VERSION 5.8 ;
BUSBITCHARS "[]" ;
DIVIDERCHAR "/" ;
UNITS
    DATABASE MICRONS 1000 ;
END UNITS

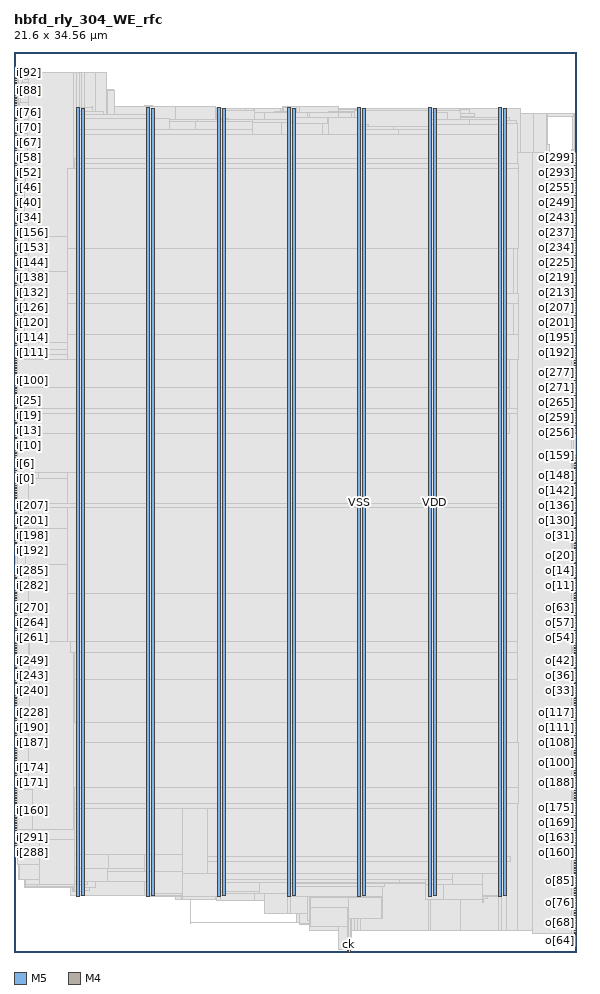
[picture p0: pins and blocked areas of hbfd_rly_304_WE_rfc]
MACRO hbfd_rly_304_WE_rfc
  FOREIGN hbfd_rly_304_WE_rfc 0 0 ;
  CLASS BLOCK ;
  SIZE 21.6 BY 34.56 ;
  PIN ck
    DIRECTION INPUT ;
    USE SIGNAL ;
    PORT
      LAYER M5 ;
        RECT  12.816 0 12.84 0.084 ;
    END
  END ck
  PIN i[0]
    DIRECTION INPUT ;
    USE SIGNAL ;
    PORT
      LAYER M4 ;
        RECT  0 18.48 0.084 18.504 ;
    END
  END i[0]
  PIN i[100]
    DIRECTION INPUT ;
    USE SIGNAL ;
    PORT
      LAYER M4 ;
        RECT  0 21.936 0.084 21.96 ;
    END
  END i[100]
  PIN i[101]
    DIRECTION INPUT ;
    USE SIGNAL ;
    PORT
      LAYER M4 ;
        RECT  0 22.032 0.084 22.056 ;
    END
  END i[101]
  PIN i[102]
    DIRECTION INPUT ;
    USE SIGNAL ;
    PORT
      LAYER M4 ;
        RECT  0 22.128 0.084 22.152 ;
    END
  END i[102]
  PIN i[103]
    DIRECTION INPUT ;
    USE SIGNAL ;
    PORT
      LAYER M4 ;
        RECT  0 22.224 0.084 22.248 ;
    END
  END i[103]
  PIN i[104]
    DIRECTION INPUT ;
    USE SIGNAL ;
    PORT
      LAYER M4 ;
        RECT  0 22.32 0.084 22.344 ;
    END
  END i[104]
  PIN i[105]
    DIRECTION INPUT ;
    USE SIGNAL ;
    PORT
      LAYER M4 ;
        RECT  0 22.416 0.084 22.44 ;
    END
  END i[105]
  PIN i[106]
    DIRECTION INPUT ;
    USE SIGNAL ;
    PORT
      LAYER M4 ;
        RECT  0 22.512 0.084 22.536 ;
    END
  END i[106]
  PIN i[107]
    DIRECTION INPUT ;
    USE SIGNAL ;
    PORT
      LAYER M4 ;
        RECT  0 22.608 0.084 22.632 ;
    END
  END i[107]
  PIN i[108]
    DIRECTION INPUT ;
    USE SIGNAL ;
    PORT
      LAYER M4 ;
        RECT  0 22.704 0.084 22.728 ;
    END
  END i[108]
  PIN i[109]
    DIRECTION INPUT ;
    USE SIGNAL ;
    PORT
      LAYER M4 ;
        RECT  0 22.8 0.084 22.824 ;
    END
  END i[109]
  PIN i[10]
    DIRECTION INPUT ;
    USE SIGNAL ;
    PORT
      LAYER M4 ;
        RECT  0 19.44 0.084 19.464 ;
    END
  END i[10]
  PIN i[110]
    DIRECTION INPUT ;
    USE SIGNAL ;
    PORT
      LAYER M4 ;
        RECT  0 22.896 0.084 22.92 ;
    END
  END i[110]
  PIN i[111]
    DIRECTION INPUT ;
    USE SIGNAL ;
    PORT
      LAYER M4 ;
        RECT  0 22.992 0.084 23.016 ;
    END
  END i[111]
  PIN i[112]
    DIRECTION INPUT ;
    USE SIGNAL ;
    PORT
      LAYER M4 ;
        RECT  0 23.088 0.084 23.112 ;
    END
  END i[112]
  PIN i[113]
    DIRECTION INPUT ;
    USE SIGNAL ;
    PORT
      LAYER M4 ;
        RECT  0 23.184 0.084 23.208 ;
    END
  END i[113]
  PIN i[114]
    DIRECTION INPUT ;
    USE SIGNAL ;
    PORT
      LAYER M4 ;
        RECT  0 23.28 0.084 23.304 ;
    END
  END i[114]
  PIN i[115]
    DIRECTION INPUT ;
    USE SIGNAL ;
    PORT
      LAYER M4 ;
        RECT  0 23.376 0.084 23.4 ;
    END
  END i[115]
  PIN i[116]
    DIRECTION INPUT ;
    USE SIGNAL ;
    PORT
      LAYER M4 ;
        RECT  0 23.472 0.084 23.496 ;
    END
  END i[116]
  PIN i[117]
    DIRECTION INPUT ;
    USE SIGNAL ;
    PORT
      LAYER M4 ;
        RECT  0 23.568 0.084 23.592 ;
    END
  END i[117]
  PIN i[118]
    DIRECTION INPUT ;
    USE SIGNAL ;
    PORT
      LAYER M4 ;
        RECT  0 23.664 0.084 23.688 ;
    END
  END i[118]
  PIN i[119]
    DIRECTION INPUT ;
    USE SIGNAL ;
    PORT
      LAYER M4 ;
        RECT  0 23.76 0.084 23.784 ;
    END
  END i[119]
  PIN i[11]
    DIRECTION INPUT ;
    USE SIGNAL ;
    PORT
      LAYER M4 ;
        RECT  0 19.536 0.084 19.56 ;
    END
  END i[11]
  PIN i[120]
    DIRECTION INPUT ;
    USE SIGNAL ;
    PORT
      LAYER M4 ;
        RECT  0 23.856 0.084 23.88 ;
    END
  END i[120]
  PIN i[121]
    DIRECTION INPUT ;
    USE SIGNAL ;
    PORT
      LAYER M4 ;
        RECT  0 23.952 0.084 23.976 ;
    END
  END i[121]
  PIN i[122]
    DIRECTION INPUT ;
    USE SIGNAL ;
    PORT
      LAYER M4 ;
        RECT  0 24.048 0.084 24.072 ;
    END
  END i[122]
  PIN i[123]
    DIRECTION INPUT ;
    USE SIGNAL ;
    PORT
      LAYER M4 ;
        RECT  0 24.144 0.084 24.168 ;
    END
  END i[123]
  PIN i[124]
    DIRECTION INPUT ;
    USE SIGNAL ;
    PORT
      LAYER M4 ;
        RECT  0 24.24 0.084 24.264 ;
    END
  END i[124]
  PIN i[125]
    DIRECTION INPUT ;
    USE SIGNAL ;
    PORT
      LAYER M4 ;
        RECT  0 24.336 0.084 24.36 ;
    END
  END i[125]
  PIN i[126]
    DIRECTION INPUT ;
    USE SIGNAL ;
    PORT
      LAYER M4 ;
        RECT  0 24.432 0.084 24.456 ;
    END
  END i[126]
  PIN i[127]
    DIRECTION INPUT ;
    USE SIGNAL ;
    PORT
      LAYER M4 ;
        RECT  0 24.528 0.084 24.552 ;
    END
  END i[127]
  PIN i[128]
    DIRECTION INPUT ;
    USE SIGNAL ;
    PORT
      LAYER M4 ;
        RECT  0 24.624 0.084 24.648 ;
    END
  END i[128]
  PIN i[129]
    DIRECTION INPUT ;
    USE SIGNAL ;
    PORT
      LAYER M4 ;
        RECT  0 24.72 0.084 24.744 ;
    END
  END i[129]
  PIN i[12]
    DIRECTION INPUT ;
    USE SIGNAL ;
    PORT
      LAYER M4 ;
        RECT  0 19.632 0.084 19.656 ;
    END
  END i[12]
  PIN i[130]
    DIRECTION INPUT ;
    USE SIGNAL ;
    PORT
      LAYER M4 ;
        RECT  0 24.816 0.084 24.84 ;
    END
  END i[130]
  PIN i[131]
    DIRECTION INPUT ;
    USE SIGNAL ;
    PORT
      LAYER M4 ;
        RECT  0 24.912 0.084 24.936 ;
    END
  END i[131]
  PIN i[132]
    DIRECTION INPUT ;
    USE SIGNAL ;
    PORT
      LAYER M4 ;
        RECT  0 25.008 0.084 25.032 ;
    END
  END i[132]
  PIN i[133]
    DIRECTION INPUT ;
    USE SIGNAL ;
    PORT
      LAYER M4 ;
        RECT  0 25.104 0.084 25.128 ;
    END
  END i[133]
  PIN i[134]
    DIRECTION INPUT ;
    USE SIGNAL ;
    PORT
      LAYER M4 ;
        RECT  0 25.2 0.084 25.224 ;
    END
  END i[134]
  PIN i[135]
    DIRECTION INPUT ;
    USE SIGNAL ;
    PORT
      LAYER M4 ;
        RECT  0 25.296 0.084 25.32 ;
    END
  END i[135]
  PIN i[136]
    DIRECTION INPUT ;
    USE SIGNAL ;
    PORT
      LAYER M4 ;
        RECT  0 25.392 0.084 25.416 ;
    END
  END i[136]
  PIN i[137]
    DIRECTION INPUT ;
    USE SIGNAL ;
    PORT
      LAYER M4 ;
        RECT  0 25.488 0.084 25.512 ;
    END
  END i[137]
  PIN i[138]
    DIRECTION INPUT ;
    USE SIGNAL ;
    PORT
      LAYER M4 ;
        RECT  0 25.584 0.084 25.608 ;
    END
  END i[138]
  PIN i[139]
    DIRECTION INPUT ;
    USE SIGNAL ;
    PORT
      LAYER M4 ;
        RECT  0 25.68 0.084 25.704 ;
    END
  END i[139]
  PIN i[13]
    DIRECTION INPUT ;
    USE SIGNAL ;
    PORT
      LAYER M4 ;
        RECT  0 19.728 0.084 19.752 ;
    END
  END i[13]
  PIN i[140]
    DIRECTION INPUT ;
    USE SIGNAL ;
    PORT
      LAYER M4 ;
        RECT  0 25.776 0.084 25.8 ;
    END
  END i[140]
  PIN i[141]
    DIRECTION INPUT ;
    USE SIGNAL ;
    PORT
      LAYER M4 ;
        RECT  0 25.872 0.084 25.896 ;
    END
  END i[141]
  PIN i[142]
    DIRECTION INPUT ;
    USE SIGNAL ;
    PORT
      LAYER M4 ;
        RECT  0 25.968 0.084 25.992 ;
    END
  END i[142]
  PIN i[143]
    DIRECTION INPUT ;
    USE SIGNAL ;
    PORT
      LAYER M4 ;
        RECT  0 26.064 0.084 26.088 ;
    END
  END i[143]
  PIN i[144]
    DIRECTION INPUT ;
    USE SIGNAL ;
    PORT
      LAYER M4 ;
        RECT  0 26.16 0.084 26.184 ;
    END
  END i[144]
  PIN i[145]
    DIRECTION INPUT ;
    USE SIGNAL ;
    PORT
      LAYER M4 ;
        RECT  0 26.256 0.084 26.28 ;
    END
  END i[145]
  PIN i[146]
    DIRECTION INPUT ;
    USE SIGNAL ;
    PORT
      LAYER M4 ;
        RECT  0 26.352 0.084 26.376 ;
    END
  END i[146]
  PIN i[147]
    DIRECTION INPUT ;
    USE SIGNAL ;
    PORT
      LAYER M4 ;
        RECT  0 26.448 0.084 26.472 ;
    END
  END i[147]
  PIN i[148]
    DIRECTION INPUT ;
    USE SIGNAL ;
    PORT
      LAYER M4 ;
        RECT  0 26.544 0.084 26.568 ;
    END
  END i[148]
  PIN i[149]
    DIRECTION INPUT ;
    USE SIGNAL ;
    PORT
      LAYER M4 ;
        RECT  0 26.64 0.084 26.664 ;
    END
  END i[149]
  PIN i[14]
    DIRECTION INPUT ;
    USE SIGNAL ;
    PORT
      LAYER M4 ;
        RECT  0 19.824 0.084 19.848 ;
    END
  END i[14]
  PIN i[150]
    DIRECTION INPUT ;
    USE SIGNAL ;
    PORT
      LAYER M4 ;
        RECT  0 26.736 0.084 26.76 ;
    END
  END i[150]
  PIN i[151]
    DIRECTION INPUT ;
    USE SIGNAL ;
    PORT
      LAYER M4 ;
        RECT  0 26.832 0.084 26.856 ;
    END
  END i[151]
  PIN i[152]
    DIRECTION INPUT ;
    USE SIGNAL ;
    PORT
      LAYER M4 ;
        RECT  0 26.928 0.084 26.952 ;
    END
  END i[152]
  PIN i[153]
    DIRECTION INPUT ;
    USE SIGNAL ;
    PORT
      LAYER M4 ;
        RECT  0 27.024 0.084 27.048 ;
    END
  END i[153]
  PIN i[154]
    DIRECTION INPUT ;
    USE SIGNAL ;
    PORT
      LAYER M4 ;
        RECT  0 27.12 0.084 27.144 ;
    END
  END i[154]
  PIN i[155]
    DIRECTION INPUT ;
    USE SIGNAL ;
    PORT
      LAYER M4 ;
        RECT  0 27.216 0.084 27.24 ;
    END
  END i[155]
  PIN i[156]
    DIRECTION INPUT ;
    USE SIGNAL ;
    PORT
      LAYER M4 ;
        RECT  0 27.312 0.084 27.336 ;
    END
  END i[156]
  PIN i[157]
    DIRECTION INPUT ;
    USE SIGNAL ;
    PORT
      LAYER M4 ;
        RECT  0 27.408 0.084 27.432 ;
    END
  END i[157]
  PIN i[158]
    DIRECTION INPUT ;
    USE SIGNAL ;
    PORT
      LAYER M4 ;
        RECT  0 27.504 0.084 27.528 ;
    END
  END i[158]
  PIN i[159]
    DIRECTION INPUT ;
    USE SIGNAL ;
    PORT
      LAYER M4 ;
        RECT  0 27.6 0.084 27.624 ;
    END
  END i[159]
  PIN i[15]
    DIRECTION INPUT ;
    USE SIGNAL ;
    PORT
      LAYER M4 ;
        RECT  0 19.92 0.084 19.944 ;
    END
  END i[15]
  PIN i[160]
    DIRECTION INPUT ;
    USE SIGNAL ;
    PORT
      LAYER M4 ;
        RECT  0 5.424 0.084 5.448 ;
    END
  END i[160]
  PIN i[161]
    DIRECTION INPUT ;
    USE SIGNAL ;
    PORT
      LAYER M4 ;
        RECT  0 5.52 0.084 5.544 ;
    END
  END i[161]
  PIN i[162]
    DIRECTION INPUT ;
    USE SIGNAL ;
    PORT
      LAYER M4 ;
        RECT  0 5.616 0.084 5.64 ;
    END
  END i[162]
  PIN i[163]
    DIRECTION INPUT ;
    USE SIGNAL ;
    PORT
      LAYER M4 ;
        RECT  0 5.712 0.084 5.736 ;
    END
  END i[163]
  PIN i[164]
    DIRECTION INPUT ;
    USE SIGNAL ;
    PORT
      LAYER M4 ;
        RECT  0 5.808 0.084 5.832 ;
    END
  END i[164]
  PIN i[165]
    DIRECTION INPUT ;
    USE SIGNAL ;
    PORT
      LAYER M4 ;
        RECT  0 5.904 0.084 5.928 ;
    END
  END i[165]
  PIN i[166]
    DIRECTION INPUT ;
    USE SIGNAL ;
    PORT
      LAYER M4 ;
        RECT  0 6 0.084 6.024 ;
    END
  END i[166]
  PIN i[167]
    DIRECTION INPUT ;
    USE SIGNAL ;
    PORT
      LAYER M4 ;
        RECT  0 6.096 0.084 6.12 ;
    END
  END i[167]
  PIN i[168]
    DIRECTION INPUT ;
    USE SIGNAL ;
    PORT
      LAYER M4 ;
        RECT  0 6.192 0.084 6.216 ;
    END
  END i[168]
  PIN i[169]
    DIRECTION INPUT ;
    USE SIGNAL ;
    PORT
      LAYER M4 ;
        RECT  0 6.288 0.084 6.312 ;
    END
  END i[169]
  PIN i[16]
    DIRECTION INPUT ;
    USE SIGNAL ;
    PORT
      LAYER M4 ;
        RECT  0 20.016 0.084 20.04 ;
    END
  END i[16]
  PIN i[170]
    DIRECTION INPUT ;
    USE SIGNAL ;
    PORT
      LAYER M4 ;
        RECT  0 6.384 0.084 6.408 ;
    END
  END i[170]
  PIN i[171]
    DIRECTION INPUT ;
    USE SIGNAL ;
    PORT
      LAYER M4 ;
        RECT  0 6.48 0.084 6.504 ;
    END
  END i[171]
  PIN i[172]
    DIRECTION INPUT ;
    USE SIGNAL ;
    PORT
      LAYER M4 ;
        RECT  0 6.576 0.084 6.6 ;
    END
  END i[172]
  PIN i[173]
    DIRECTION INPUT ;
    USE SIGNAL ;
    PORT
      LAYER M4 ;
        RECT  0 6.672 0.084 6.696 ;
    END
  END i[173]
  PIN i[174]
    DIRECTION INPUT ;
    USE SIGNAL ;
    PORT
      LAYER M4 ;
        RECT  0 6.768 0.084 6.792 ;
    END
  END i[174]
  PIN i[175]
    DIRECTION INPUT ;
    USE SIGNAL ;
    PORT
      LAYER M4 ;
        RECT  0 6.864 0.084 6.888 ;
    END
  END i[175]
  PIN i[176]
    DIRECTION INPUT ;
    USE SIGNAL ;
    PORT
      LAYER M4 ;
        RECT  0 6.96 0.084 6.984 ;
    END
  END i[176]
  PIN i[177]
    DIRECTION INPUT ;
    USE SIGNAL ;
    PORT
      LAYER M4 ;
        RECT  0 7.056 0.084 7.08 ;
    END
  END i[177]
  PIN i[178]
    DIRECTION INPUT ;
    USE SIGNAL ;
    PORT
      LAYER M4 ;
        RECT  0 7.152 0.084 7.176 ;
    END
  END i[178]
  PIN i[179]
    DIRECTION INPUT ;
    USE SIGNAL ;
    PORT
      LAYER M4 ;
        RECT  0 7.248 0.084 7.272 ;
    END
  END i[179]
  PIN i[17]
    DIRECTION INPUT ;
    USE SIGNAL ;
    PORT
      LAYER M4 ;
        RECT  0 20.112 0.084 20.136 ;
    END
  END i[17]
  PIN i[180]
    DIRECTION INPUT ;
    USE SIGNAL ;
    PORT
      LAYER M4 ;
        RECT  0 7.344 0.084 7.368 ;
    END
  END i[180]
  PIN i[181]
    DIRECTION INPUT ;
    USE SIGNAL ;
    PORT
      LAYER M4 ;
        RECT  0 7.44 0.084 7.464 ;
    END
  END i[181]
  PIN i[182]
    DIRECTION INPUT ;
    USE SIGNAL ;
    PORT
      LAYER M4 ;
        RECT  0 7.536 0.084 7.56 ;
    END
  END i[182]
  PIN i[183]
    DIRECTION INPUT ;
    USE SIGNAL ;
    PORT
      LAYER M4 ;
        RECT  0 7.632 0.084 7.656 ;
    END
  END i[183]
  PIN i[184]
    DIRECTION INPUT ;
    USE SIGNAL ;
    PORT
      LAYER M4 ;
        RECT  0 7.728 0.084 7.752 ;
    END
  END i[184]
  PIN i[185]
    DIRECTION INPUT ;
    USE SIGNAL ;
    PORT
      LAYER M4 ;
        RECT  0 7.824 0.084 7.848 ;
    END
  END i[185]
  PIN i[186]
    DIRECTION INPUT ;
    USE SIGNAL ;
    PORT
      LAYER M4 ;
        RECT  0 7.92 0.084 7.944 ;
    END
  END i[186]
  PIN i[187]
    DIRECTION INPUT ;
    USE SIGNAL ;
    PORT
      LAYER M4 ;
        RECT  0 8.016 0.084 8.04 ;
    END
  END i[187]
  PIN i[188]
    DIRECTION INPUT ;
    USE SIGNAL ;
    PORT
      LAYER M4 ;
        RECT  0 8.112 0.084 8.136 ;
    END
  END i[188]
  PIN i[189]
    DIRECTION INPUT ;
    USE SIGNAL ;
    PORT
      LAYER M4 ;
        RECT  0 8.208 0.084 8.232 ;
    END
  END i[189]
  PIN i[18]
    DIRECTION INPUT ;
    USE SIGNAL ;
    PORT
      LAYER M4 ;
        RECT  0 20.208 0.084 20.232 ;
    END
  END i[18]
  PIN i[190]
    DIRECTION INPUT ;
    USE SIGNAL ;
    PORT
      LAYER M4 ;
        RECT  0 8.304 0.084 8.328 ;
    END
  END i[190]
  PIN i[191]
    DIRECTION INPUT ;
    USE SIGNAL ;
    PORT
      LAYER M4 ;
        RECT  0 8.4 0.084 8.424 ;
    END
  END i[191]
  PIN i[192]
    DIRECTION INPUT ;
    USE SIGNAL ;
    PORT
      LAYER M4 ;
        RECT  0 15.408 0.084 15.432 ;
    END
  END i[192]
  PIN i[193]
    DIRECTION INPUT ;
    USE SIGNAL ;
    PORT
      LAYER M4 ;
        RECT  0 15.504 0.084 15.528 ;
    END
  END i[193]
  PIN i[194]
    DIRECTION INPUT ;
    USE SIGNAL ;
    PORT
      LAYER M4 ;
        RECT  0 15.6 0.084 15.624 ;
    END
  END i[194]
  PIN i[195]
    DIRECTION INPUT ;
    USE SIGNAL ;
    PORT
      LAYER M4 ;
        RECT  0 15.696 0.084 15.72 ;
    END
  END i[195]
  PIN i[196]
    DIRECTION INPUT ;
    USE SIGNAL ;
    PORT
      LAYER M4 ;
        RECT  0 15.792 0.084 15.816 ;
    END
  END i[196]
  PIN i[197]
    DIRECTION INPUT ;
    USE SIGNAL ;
    PORT
      LAYER M4 ;
        RECT  0 15.888 0.084 15.912 ;
    END
  END i[197]
  PIN i[198]
    DIRECTION INPUT ;
    USE SIGNAL ;
    PORT
      LAYER M4 ;
        RECT  0 15.984 0.084 16.008 ;
    END
  END i[198]
  PIN i[199]
    DIRECTION INPUT ;
    USE SIGNAL ;
    PORT
      LAYER M4 ;
        RECT  0 16.08 0.084 16.104 ;
    END
  END i[199]
  PIN i[19]
    DIRECTION INPUT ;
    USE SIGNAL ;
    PORT
      LAYER M4 ;
        RECT  0 20.304 0.084 20.328 ;
    END
  END i[19]
  PIN i[1]
    DIRECTION INPUT ;
    USE SIGNAL ;
    PORT
      LAYER M4 ;
        RECT  0 18.576 0.084 18.6 ;
    END
  END i[1]
  PIN i[200]
    DIRECTION INPUT ;
    USE SIGNAL ;
    PORT
      LAYER M4 ;
        RECT  0 16.176 0.084 16.2 ;
    END
  END i[200]
  PIN i[201]
    DIRECTION INPUT ;
    USE SIGNAL ;
    PORT
      LAYER M4 ;
        RECT  0 16.272 0.084 16.296 ;
    END
  END i[201]
  PIN i[202]
    DIRECTION INPUT ;
    USE SIGNAL ;
    PORT
      LAYER M4 ;
        RECT  0 16.368 0.084 16.392 ;
    END
  END i[202]
  PIN i[203]
    DIRECTION INPUT ;
    USE SIGNAL ;
    PORT
      LAYER M4 ;
        RECT  0 16.464 0.084 16.488 ;
    END
  END i[203]
  PIN i[204]
    DIRECTION INPUT ;
    USE SIGNAL ;
    PORT
      LAYER M4 ;
        RECT  0 16.56 0.084 16.584 ;
    END
  END i[204]
  PIN i[205]
    DIRECTION INPUT ;
    USE SIGNAL ;
    PORT
      LAYER M4 ;
        RECT  0 16.656 0.084 16.68 ;
    END
  END i[205]
  PIN i[206]
    DIRECTION INPUT ;
    USE SIGNAL ;
    PORT
      LAYER M4 ;
        RECT  0 16.752 0.084 16.776 ;
    END
  END i[206]
  PIN i[207]
    DIRECTION INPUT ;
    USE SIGNAL ;
    PORT
      LAYER M4 ;
        RECT  0 16.848 0.084 16.872 ;
    END
  END i[207]
  PIN i[208]
    DIRECTION INPUT ;
    USE SIGNAL ;
    PORT
      LAYER M4 ;
        RECT  0 16.944 0.084 16.968 ;
    END
  END i[208]
  PIN i[209]
    DIRECTION INPUT ;
    USE SIGNAL ;
    PORT
      LAYER M4 ;
        RECT  0 17.04 0.084 17.064 ;
    END
  END i[209]
  PIN i[20]
    DIRECTION INPUT ;
    USE SIGNAL ;
    PORT
      LAYER M4 ;
        RECT  0 20.4 0.084 20.424 ;
    END
  END i[20]
  PIN i[210]
    DIRECTION INPUT ;
    USE SIGNAL ;
    PORT
      LAYER M4 ;
        RECT  0 17.136 0.084 17.16 ;
    END
  END i[210]
  PIN i[211]
    DIRECTION INPUT ;
    USE SIGNAL ;
    PORT
      LAYER M4 ;
        RECT  0 17.232 0.084 17.256 ;
    END
  END i[211]
  PIN i[212]
    DIRECTION INPUT ;
    USE SIGNAL ;
    PORT
      LAYER M4 ;
        RECT  0 17.328 0.084 17.352 ;
    END
  END i[212]
  PIN i[213]
    DIRECTION INPUT ;
    USE SIGNAL ;
    PORT
      LAYER M4 ;
        RECT  0 17.424 0.084 17.448 ;
    END
  END i[213]
  PIN i[214]
    DIRECTION INPUT ;
    USE SIGNAL ;
    PORT
      LAYER M4 ;
        RECT  0 17.52 0.084 17.544 ;
    END
  END i[214]
  PIN i[215]
    DIRECTION INPUT ;
    USE SIGNAL ;
    PORT
      LAYER M4 ;
        RECT  0 17.616 0.084 17.64 ;
    END
  END i[215]
  PIN i[216]
    DIRECTION INPUT ;
    USE SIGNAL ;
    PORT
      LAYER M4 ;
        RECT  0 17.712 0.084 17.736 ;
    END
  END i[216]
  PIN i[217]
    DIRECTION INPUT ;
    USE SIGNAL ;
    PORT
      LAYER M4 ;
        RECT  0 17.808 0.084 17.832 ;
    END
  END i[217]
  PIN i[218]
    DIRECTION INPUT ;
    USE SIGNAL ;
    PORT
      LAYER M4 ;
        RECT  0 17.904 0.084 17.928 ;
    END
  END i[218]
  PIN i[219]
    DIRECTION INPUT ;
    USE SIGNAL ;
    PORT
      LAYER M4 ;
        RECT  0 18 0.084 18.024 ;
    END
  END i[219]
  PIN i[21]
    DIRECTION INPUT ;
    USE SIGNAL ;
    PORT
      LAYER M4 ;
        RECT  0 20.496 0.084 20.52 ;
    END
  END i[21]
  PIN i[220]
    DIRECTION INPUT ;
    USE SIGNAL ;
    PORT
      LAYER M4 ;
        RECT  0 18.096 0.084 18.12 ;
    END
  END i[220]
  PIN i[221]
    DIRECTION INPUT ;
    USE SIGNAL ;
    PORT
      LAYER M4 ;
        RECT  0 18.192 0.084 18.216 ;
    END
  END i[221]
  PIN i[222]
    DIRECTION INPUT ;
    USE SIGNAL ;
    PORT
      LAYER M4 ;
        RECT  0 18.288 0.084 18.312 ;
    END
  END i[222]
  PIN i[223]
    DIRECTION INPUT ;
    USE SIGNAL ;
    PORT
      LAYER M4 ;
        RECT  0 18.384 0.084 18.408 ;
    END
  END i[223]
  PIN i[224]
    DIRECTION INPUT ;
    USE SIGNAL ;
    PORT
      LAYER M4 ;
        RECT  0 8.496 0.084 8.52 ;
    END
  END i[224]
  PIN i[225]
    DIRECTION INPUT ;
    USE SIGNAL ;
    PORT
      LAYER M4 ;
        RECT  0 8.592 0.084 8.616 ;
    END
  END i[225]
  PIN i[226]
    DIRECTION INPUT ;
    USE SIGNAL ;
    PORT
      LAYER M4 ;
        RECT  0 8.688 0.084 8.712 ;
    END
  END i[226]
  PIN i[227]
    DIRECTION INPUT ;
    USE SIGNAL ;
    PORT
      LAYER M4 ;
        RECT  0 8.784 0.084 8.808 ;
    END
  END i[227]
  PIN i[228]
    DIRECTION INPUT ;
    USE SIGNAL ;
    PORT
      LAYER M4 ;
        RECT  0 8.88 0.084 8.904 ;
    END
  END i[228]
  PIN i[229]
    DIRECTION INPUT ;
    USE SIGNAL ;
    PORT
      LAYER M4 ;
        RECT  0 8.976 0.084 9 ;
    END
  END i[229]
  PIN i[22]
    DIRECTION INPUT ;
    USE SIGNAL ;
    PORT
      LAYER M4 ;
        RECT  0 20.592 0.084 20.616 ;
    END
  END i[22]
  PIN i[230]
    DIRECTION INPUT ;
    USE SIGNAL ;
    PORT
      LAYER M4 ;
        RECT  0 9.072 0.084 9.096 ;
    END
  END i[230]
  PIN i[231]
    DIRECTION INPUT ;
    USE SIGNAL ;
    PORT
      LAYER M4 ;
        RECT  0 9.168 0.084 9.192 ;
    END
  END i[231]
  PIN i[232]
    DIRECTION INPUT ;
    USE SIGNAL ;
    PORT
      LAYER M4 ;
        RECT  0 9.264 0.084 9.288 ;
    END
  END i[232]
  PIN i[233]
    DIRECTION INPUT ;
    USE SIGNAL ;
    PORT
      LAYER M4 ;
        RECT  0 9.36 0.084 9.384 ;
    END
  END i[233]
  PIN i[234]
    DIRECTION INPUT ;
    USE SIGNAL ;
    PORT
      LAYER M4 ;
        RECT  0 9.456 0.084 9.48 ;
    END
  END i[234]
  PIN i[235]
    DIRECTION INPUT ;
    USE SIGNAL ;
    PORT
      LAYER M4 ;
        RECT  0 9.552 0.084 9.576 ;
    END
  END i[235]
  PIN i[236]
    DIRECTION INPUT ;
    USE SIGNAL ;
    PORT
      LAYER M4 ;
        RECT  0 9.648 0.084 9.672 ;
    END
  END i[236]
  PIN i[237]
    DIRECTION INPUT ;
    USE SIGNAL ;
    PORT
      LAYER M4 ;
        RECT  0 9.744 0.084 9.768 ;
    END
  END i[237]
  PIN i[238]
    DIRECTION INPUT ;
    USE SIGNAL ;
    PORT
      LAYER M4 ;
        RECT  0 9.84 0.084 9.864 ;
    END
  END i[238]
  PIN i[239]
    DIRECTION INPUT ;
    USE SIGNAL ;
    PORT
      LAYER M4 ;
        RECT  0 9.936 0.084 9.96 ;
    END
  END i[239]
  PIN i[23]
    DIRECTION INPUT ;
    USE SIGNAL ;
    PORT
      LAYER M4 ;
        RECT  0 20.688 0.084 20.712 ;
    END
  END i[23]
  PIN i[240]
    DIRECTION INPUT ;
    USE SIGNAL ;
    PORT
      LAYER M4 ;
        RECT  0 10.032 0.084 10.056 ;
    END
  END i[240]
  PIN i[241]
    DIRECTION INPUT ;
    USE SIGNAL ;
    PORT
      LAYER M4 ;
        RECT  0 10.128 0.084 10.152 ;
    END
  END i[241]
  PIN i[242]
    DIRECTION INPUT ;
    USE SIGNAL ;
    PORT
      LAYER M4 ;
        RECT  0 10.224 0.084 10.248 ;
    END
  END i[242]
  PIN i[243]
    DIRECTION INPUT ;
    USE SIGNAL ;
    PORT
      LAYER M4 ;
        RECT  0 10.32 0.084 10.344 ;
    END
  END i[243]
  PIN i[244]
    DIRECTION INPUT ;
    USE SIGNAL ;
    PORT
      LAYER M4 ;
        RECT  0 10.416 0.084 10.44 ;
    END
  END i[244]
  PIN i[245]
    DIRECTION INPUT ;
    USE SIGNAL ;
    PORT
      LAYER M4 ;
        RECT  0 10.512 0.084 10.536 ;
    END
  END i[245]
  PIN i[246]
    DIRECTION INPUT ;
    USE SIGNAL ;
    PORT
      LAYER M4 ;
        RECT  0 10.608 0.084 10.632 ;
    END
  END i[246]
  PIN i[247]
    DIRECTION INPUT ;
    USE SIGNAL ;
    PORT
      LAYER M4 ;
        RECT  0 10.704 0.084 10.728 ;
    END
  END i[247]
  PIN i[248]
    DIRECTION INPUT ;
    USE SIGNAL ;
    PORT
      LAYER M4 ;
        RECT  0 10.8 0.084 10.824 ;
    END
  END i[248]
  PIN i[249]
    DIRECTION INPUT ;
    USE SIGNAL ;
    PORT
      LAYER M4 ;
        RECT  0 10.896 0.084 10.92 ;
    END
  END i[249]
  PIN i[24]
    DIRECTION INPUT ;
    USE SIGNAL ;
    PORT
      LAYER M4 ;
        RECT  0 20.784 0.084 20.808 ;
    END
  END i[24]
  PIN i[250]
    DIRECTION INPUT ;
    USE SIGNAL ;
    PORT
      LAYER M4 ;
        RECT  0 10.992 0.084 11.016 ;
    END
  END i[250]
  PIN i[251]
    DIRECTION INPUT ;
    USE SIGNAL ;
    PORT
      LAYER M4 ;
        RECT  0 11.088 0.084 11.112 ;
    END
  END i[251]
  PIN i[252]
    DIRECTION INPUT ;
    USE SIGNAL ;
    PORT
      LAYER M4 ;
        RECT  0 11.184 0.084 11.208 ;
    END
  END i[252]
  PIN i[253]
    DIRECTION INPUT ;
    USE SIGNAL ;
    PORT
      LAYER M4 ;
        RECT  0 11.28 0.084 11.304 ;
    END
  END i[253]
  PIN i[254]
    DIRECTION INPUT ;
    USE SIGNAL ;
    PORT
      LAYER M4 ;
        RECT  0 11.376 0.084 11.4 ;
    END
  END i[254]
  PIN i[255]
    DIRECTION INPUT ;
    USE SIGNAL ;
    PORT
      LAYER M4 ;
        RECT  0 11.472 0.084 11.496 ;
    END
  END i[255]
  PIN i[256]
    DIRECTION INPUT ;
    USE SIGNAL ;
    PORT
      LAYER M4 ;
        RECT  0 11.568 0.084 11.592 ;
    END
  END i[256]
  PIN i[257]
    DIRECTION INPUT ;
    USE SIGNAL ;
    PORT
      LAYER M4 ;
        RECT  0 11.664 0.084 11.688 ;
    END
  END i[257]
  PIN i[258]
    DIRECTION INPUT ;
    USE SIGNAL ;
    PORT
      LAYER M4 ;
        RECT  0 11.76 0.084 11.784 ;
    END
  END i[258]
  PIN i[259]
    DIRECTION INPUT ;
    USE SIGNAL ;
    PORT
      LAYER M4 ;
        RECT  0 11.856 0.084 11.88 ;
    END
  END i[259]
  PIN i[25]
    DIRECTION INPUT ;
    USE SIGNAL ;
    PORT
      LAYER M4 ;
        RECT  0 20.88 0.084 20.904 ;
    END
  END i[25]
  PIN i[260]
    DIRECTION INPUT ;
    USE SIGNAL ;
    PORT
      LAYER M4 ;
        RECT  0 11.952 0.084 11.976 ;
    END
  END i[260]
  PIN i[261]
    DIRECTION INPUT ;
    USE SIGNAL ;
    PORT
      LAYER M4 ;
        RECT  0 12.048 0.084 12.072 ;
    END
  END i[261]
  PIN i[262]
    DIRECTION INPUT ;
    USE SIGNAL ;
    PORT
      LAYER M4 ;
        RECT  0 12.144 0.084 12.168 ;
    END
  END i[262]
  PIN i[263]
    DIRECTION INPUT ;
    USE SIGNAL ;
    PORT
      LAYER M4 ;
        RECT  0 12.24 0.084 12.264 ;
    END
  END i[263]
  PIN i[264]
    DIRECTION INPUT ;
    USE SIGNAL ;
    PORT
      LAYER M4 ;
        RECT  0 12.336 0.084 12.36 ;
    END
  END i[264]
  PIN i[265]
    DIRECTION INPUT ;
    USE SIGNAL ;
    PORT
      LAYER M4 ;
        RECT  0 12.432 0.084 12.456 ;
    END
  END i[265]
  PIN i[266]
    DIRECTION INPUT ;
    USE SIGNAL ;
    PORT
      LAYER M4 ;
        RECT  0 12.528 0.084 12.552 ;
    END
  END i[266]
  PIN i[267]
    DIRECTION INPUT ;
    USE SIGNAL ;
    PORT
      LAYER M4 ;
        RECT  0 12.624 0.084 12.648 ;
    END
  END i[267]
  PIN i[268]
    DIRECTION INPUT ;
    USE SIGNAL ;
    PORT
      LAYER M4 ;
        RECT  0 12.72 0.084 12.744 ;
    END
  END i[268]
  PIN i[269]
    DIRECTION INPUT ;
    USE SIGNAL ;
    PORT
      LAYER M4 ;
        RECT  0 12.816 0.084 12.84 ;
    END
  END i[269]
  PIN i[26]
    DIRECTION INPUT ;
    USE SIGNAL ;
    PORT
      LAYER M4 ;
        RECT  0 20.976 0.084 21 ;
    END
  END i[26]
  PIN i[270]
    DIRECTION INPUT ;
    USE SIGNAL ;
    PORT
      LAYER M4 ;
        RECT  0 12.912 0.084 12.936 ;
    END
  END i[270]
  PIN i[271]
    DIRECTION INPUT ;
    USE SIGNAL ;
    PORT
      LAYER M4 ;
        RECT  0 13.008 0.084 13.032 ;
    END
  END i[271]
  PIN i[272]
    DIRECTION INPUT ;
    USE SIGNAL ;
    PORT
      LAYER M4 ;
        RECT  0 13.104 0.084 13.128 ;
    END
  END i[272]
  PIN i[273]
    DIRECTION INPUT ;
    USE SIGNAL ;
    PORT
      LAYER M4 ;
        RECT  0 13.2 0.084 13.224 ;
    END
  END i[273]
  PIN i[274]
    DIRECTION INPUT ;
    USE SIGNAL ;
    PORT
      LAYER M4 ;
        RECT  0 13.296 0.084 13.32 ;
    END
  END i[274]
  PIN i[275]
    DIRECTION INPUT ;
    USE SIGNAL ;
    PORT
      LAYER M4 ;
        RECT  0 13.392 0.084 13.416 ;
    END
  END i[275]
  PIN i[276]
    DIRECTION INPUT ;
    USE SIGNAL ;
    PORT
      LAYER M4 ;
        RECT  0 13.488 0.084 13.512 ;
    END
  END i[276]
  PIN i[277]
    DIRECTION INPUT ;
    USE SIGNAL ;
    PORT
      LAYER M4 ;
        RECT  0 13.584 0.084 13.608 ;
    END
  END i[277]
  PIN i[278]
    DIRECTION INPUT ;
    USE SIGNAL ;
    PORT
      LAYER M4 ;
        RECT  0 13.68 0.084 13.704 ;
    END
  END i[278]
  PIN i[279]
    DIRECTION INPUT ;
    USE SIGNAL ;
    PORT
      LAYER M4 ;
        RECT  0 13.776 0.084 13.8 ;
    END
  END i[279]
  PIN i[27]
    DIRECTION INPUT ;
    USE SIGNAL ;
    PORT
      LAYER M4 ;
        RECT  0 21.072 0.084 21.096 ;
    END
  END i[27]
  PIN i[280]
    DIRECTION INPUT ;
    USE SIGNAL ;
    PORT
      LAYER M4 ;
        RECT  0 13.872 0.084 13.896 ;
    END
  END i[280]
  PIN i[281]
    DIRECTION INPUT ;
    USE SIGNAL ;
    PORT
      LAYER M4 ;
        RECT  0 13.968 0.084 13.992 ;
    END
  END i[281]
  PIN i[282]
    DIRECTION INPUT ;
    USE SIGNAL ;
    PORT
      LAYER M4 ;
        RECT  0 14.064 0.084 14.088 ;
    END
  END i[282]
  PIN i[283]
    DIRECTION INPUT ;
    USE SIGNAL ;
    PORT
      LAYER M4 ;
        RECT  0 14.16 0.084 14.184 ;
    END
  END i[283]
  PIN i[284]
    DIRECTION INPUT ;
    USE SIGNAL ;
    PORT
      LAYER M4 ;
        RECT  0 14.256 0.084 14.28 ;
    END
  END i[284]
  PIN i[285]
    DIRECTION INPUT ;
    USE SIGNAL ;
    PORT
      LAYER M4 ;
        RECT  0 14.352 0.084 14.376 ;
    END
  END i[285]
  PIN i[286]
    DIRECTION INPUT ;
    USE SIGNAL ;
    PORT
      LAYER M4 ;
        RECT  0 14.448 0.084 14.472 ;
    END
  END i[286]
  PIN i[287]
    DIRECTION INPUT ;
    USE SIGNAL ;
    PORT
      LAYER M4 ;
        RECT  0 14.544 0.084 14.568 ;
    END
  END i[287]
  PIN i[288]
    DIRECTION INPUT ;
    USE SIGNAL ;
    PORT
      LAYER M4 ;
        RECT  0 3.792 0.084 3.816 ;
    END
  END i[288]
  PIN i[289]
    DIRECTION INPUT ;
    USE SIGNAL ;
    PORT
      LAYER M4 ;
        RECT  0 3.888 0.084 3.912 ;
    END
  END i[289]
  PIN i[28]
    DIRECTION INPUT ;
    USE SIGNAL ;
    PORT
      LAYER M4 ;
        RECT  0 21.168 0.084 21.192 ;
    END
  END i[28]
  PIN i[290]
    DIRECTION INPUT ;
    USE SIGNAL ;
    PORT
      LAYER M4 ;
        RECT  0 3.984 0.084 4.008 ;
    END
  END i[290]
  PIN i[291]
    DIRECTION INPUT ;
    USE SIGNAL ;
    PORT
      LAYER M4 ;
        RECT  0 4.08 0.084 4.104 ;
    END
  END i[291]
  PIN i[292]
    DIRECTION INPUT ;
    USE SIGNAL ;
    PORT
      LAYER M4 ;
        RECT  0 4.176 0.084 4.2 ;
    END
  END i[292]
  PIN i[293]
    DIRECTION INPUT ;
    USE SIGNAL ;
    PORT
      LAYER M4 ;
        RECT  0 4.272 0.084 4.296 ;
    END
  END i[293]
  PIN i[294]
    DIRECTION INPUT ;
    USE SIGNAL ;
    PORT
      LAYER M4 ;
        RECT  0 4.368 0.084 4.392 ;
    END
  END i[294]
  PIN i[295]
    DIRECTION INPUT ;
    USE SIGNAL ;
    PORT
      LAYER M4 ;
        RECT  0 4.464 0.084 4.488 ;
    END
  END i[295]
  PIN i[296]
    DIRECTION INPUT ;
    USE SIGNAL ;
    PORT
      LAYER M4 ;
        RECT  0 4.56 0.084 4.584 ;
    END
  END i[296]
  PIN i[297]
    DIRECTION INPUT ;
    USE SIGNAL ;
    PORT
      LAYER M4 ;
        RECT  0 4.656 0.084 4.68 ;
    END
  END i[297]
  PIN i[298]
    DIRECTION INPUT ;
    USE SIGNAL ;
    PORT
      LAYER M4 ;
        RECT  0 4.752 0.084 4.776 ;
    END
  END i[298]
  PIN i[299]
    DIRECTION INPUT ;
    USE SIGNAL ;
    PORT
      LAYER M4 ;
        RECT  0 4.848 0.084 4.872 ;
    END
  END i[299]
  PIN i[29]
    DIRECTION INPUT ;
    USE SIGNAL ;
    PORT
      LAYER M4 ;
        RECT  0 21.264 0.084 21.288 ;
    END
  END i[29]
  PIN i[2]
    DIRECTION INPUT ;
    USE SIGNAL ;
    PORT
      LAYER M4 ;
        RECT  0 18.672 0.084 18.696 ;
    END
  END i[2]
  PIN i[300]
    DIRECTION INPUT ;
    USE SIGNAL ;
    PORT
      LAYER M4 ;
        RECT  0 4.944 0.084 4.968 ;
    END
  END i[300]
  PIN i[301]
    DIRECTION INPUT ;
    USE SIGNAL ;
    PORT
      LAYER M4 ;
        RECT  0 5.04 0.084 5.064 ;
    END
  END i[301]
  PIN i[302]
    DIRECTION INPUT ;
    USE SIGNAL ;
    PORT
      LAYER M4 ;
        RECT  0 5.136 0.084 5.16 ;
    END
  END i[302]
  PIN i[303]
    DIRECTION INPUT ;
    USE SIGNAL ;
    PORT
      LAYER M4 ;
        RECT  0 5.232 0.084 5.256 ;
    END
  END i[303]
  PIN i[30]
    DIRECTION INPUT ;
    USE SIGNAL ;
    PORT
      LAYER M4 ;
        RECT  0 21.36 0.084 21.384 ;
    END
  END i[30]
  PIN i[31]
    DIRECTION INPUT ;
    USE SIGNAL ;
    PORT
      LAYER M4 ;
        RECT  0 21.456 0.084 21.48 ;
    END
  END i[31]
  PIN i[32]
    DIRECTION INPUT ;
    USE SIGNAL ;
    PORT
      LAYER M4 ;
        RECT  0 27.696 0.084 27.72 ;
    END
  END i[32]
  PIN i[33]
    DIRECTION INPUT ;
    USE SIGNAL ;
    PORT
      LAYER M4 ;
        RECT  0 27.792 0.084 27.816 ;
    END
  END i[33]
  PIN i[34]
    DIRECTION INPUT ;
    USE SIGNAL ;
    PORT
      LAYER M4 ;
        RECT  0 27.888 0.084 27.912 ;
    END
  END i[34]
  PIN i[35]
    DIRECTION INPUT ;
    USE SIGNAL ;
    PORT
      LAYER M4 ;
        RECT  0 27.984 0.084 28.008 ;
    END
  END i[35]
  PIN i[36]
    DIRECTION INPUT ;
    USE SIGNAL ;
    PORT
      LAYER M4 ;
        RECT  0 28.08 0.084 28.104 ;
    END
  END i[36]
  PIN i[37]
    DIRECTION INPUT ;
    USE SIGNAL ;
    PORT
      LAYER M4 ;
        RECT  0 28.176 0.084 28.2 ;
    END
  END i[37]
  PIN i[38]
    DIRECTION INPUT ;
    USE SIGNAL ;
    PORT
      LAYER M4 ;
        RECT  0 28.272 0.084 28.296 ;
    END
  END i[38]
  PIN i[39]
    DIRECTION INPUT ;
    USE SIGNAL ;
    PORT
      LAYER M4 ;
        RECT  0 28.368 0.084 28.392 ;
    END
  END i[39]
  PIN i[3]
    DIRECTION INPUT ;
    USE SIGNAL ;
    PORT
      LAYER M4 ;
        RECT  0 18.768 0.084 18.792 ;
    END
  END i[3]
  PIN i[40]
    DIRECTION INPUT ;
    USE SIGNAL ;
    PORT
      LAYER M4 ;
        RECT  0 28.464 0.084 28.488 ;
    END
  END i[40]
  PIN i[41]
    DIRECTION INPUT ;
    USE SIGNAL ;
    PORT
      LAYER M4 ;
        RECT  0 28.56 0.084 28.584 ;
    END
  END i[41]
  PIN i[42]
    DIRECTION INPUT ;
    USE SIGNAL ;
    PORT
      LAYER M4 ;
        RECT  0 28.656 0.084 28.68 ;
    END
  END i[42]
  PIN i[43]
    DIRECTION INPUT ;
    USE SIGNAL ;
    PORT
      LAYER M4 ;
        RECT  0 28.752 0.084 28.776 ;
    END
  END i[43]
  PIN i[44]
    DIRECTION INPUT ;
    USE SIGNAL ;
    PORT
      LAYER M4 ;
        RECT  0 28.848 0.084 28.872 ;
    END
  END i[44]
  PIN i[45]
    DIRECTION INPUT ;
    USE SIGNAL ;
    PORT
      LAYER M4 ;
        RECT  0 28.944 0.084 28.968 ;
    END
  END i[45]
  PIN i[46]
    DIRECTION INPUT ;
    USE SIGNAL ;
    PORT
      LAYER M4 ;
        RECT  0 29.04 0.084 29.064 ;
    END
  END i[46]
  PIN i[47]
    DIRECTION INPUT ;
    USE SIGNAL ;
    PORT
      LAYER M4 ;
        RECT  0 29.136 0.084 29.16 ;
    END
  END i[47]
  PIN i[48]
    DIRECTION INPUT ;
    USE SIGNAL ;
    PORT
      LAYER M4 ;
        RECT  0 29.232 0.084 29.256 ;
    END
  END i[48]
  PIN i[49]
    DIRECTION INPUT ;
    USE SIGNAL ;
    PORT
      LAYER M4 ;
        RECT  0 29.328 0.084 29.352 ;
    END
  END i[49]
  PIN i[4]
    DIRECTION INPUT ;
    USE SIGNAL ;
    PORT
      LAYER M4 ;
        RECT  0 18.864 0.084 18.888 ;
    END
  END i[4]
  PIN i[50]
    DIRECTION INPUT ;
    USE SIGNAL ;
    PORT
      LAYER M4 ;
        RECT  0 29.424 0.084 29.448 ;
    END
  END i[50]
  PIN i[51]
    DIRECTION INPUT ;
    USE SIGNAL ;
    PORT
      LAYER M4 ;
        RECT  0 29.52 0.084 29.544 ;
    END
  END i[51]
  PIN i[52]
    DIRECTION INPUT ;
    USE SIGNAL ;
    PORT
      LAYER M4 ;
        RECT  0 29.616 0.084 29.64 ;
    END
  END i[52]
  PIN i[53]
    DIRECTION INPUT ;
    USE SIGNAL ;
    PORT
      LAYER M4 ;
        RECT  0 29.712 0.084 29.736 ;
    END
  END i[53]
  PIN i[54]
    DIRECTION INPUT ;
    USE SIGNAL ;
    PORT
      LAYER M4 ;
        RECT  0 29.808 0.084 29.832 ;
    END
  END i[54]
  PIN i[55]
    DIRECTION INPUT ;
    USE SIGNAL ;
    PORT
      LAYER M4 ;
        RECT  0 29.904 0.084 29.928 ;
    END
  END i[55]
  PIN i[56]
    DIRECTION INPUT ;
    USE SIGNAL ;
    PORT
      LAYER M4 ;
        RECT  0 30 0.084 30.024 ;
    END
  END i[56]
  PIN i[57]
    DIRECTION INPUT ;
    USE SIGNAL ;
    PORT
      LAYER M4 ;
        RECT  0 30.096 0.084 30.12 ;
    END
  END i[57]
  PIN i[58]
    DIRECTION INPUT ;
    USE SIGNAL ;
    PORT
      LAYER M4 ;
        RECT  0 30.192 0.084 30.216 ;
    END
  END i[58]
  PIN i[59]
    DIRECTION INPUT ;
    USE SIGNAL ;
    PORT
      LAYER M4 ;
        RECT  0 30.288 0.084 30.312 ;
    END
  END i[59]
  PIN i[5]
    DIRECTION INPUT ;
    USE SIGNAL ;
    PORT
      LAYER M4 ;
        RECT  0 18.96 0.084 18.984 ;
    END
  END i[5]
  PIN i[60]
    DIRECTION INPUT ;
    USE SIGNAL ;
    PORT
      LAYER M4 ;
        RECT  0 30.384 0.084 30.408 ;
    END
  END i[60]
  PIN i[61]
    DIRECTION INPUT ;
    USE SIGNAL ;
    PORT
      LAYER M4 ;
        RECT  0 30.48 0.084 30.504 ;
    END
  END i[61]
  PIN i[62]
    DIRECTION INPUT ;
    USE SIGNAL ;
    PORT
      LAYER M4 ;
        RECT  0 30.576 0.084 30.6 ;
    END
  END i[62]
  PIN i[63]
    DIRECTION INPUT ;
    USE SIGNAL ;
    PORT
      LAYER M4 ;
        RECT  0 30.672 0.084 30.696 ;
    END
  END i[63]
  PIN i[64]
    DIRECTION INPUT ;
    USE SIGNAL ;
    PORT
      LAYER M4 ;
        RECT  0 30.768 0.084 30.792 ;
    END
  END i[64]
  PIN i[65]
    DIRECTION INPUT ;
    USE SIGNAL ;
    PORT
      LAYER M4 ;
        RECT  0 30.864 0.084 30.888 ;
    END
  END i[65]
  PIN i[66]
    DIRECTION INPUT ;
    USE SIGNAL ;
    PORT
      LAYER M4 ;
        RECT  0 30.96 0.084 30.984 ;
    END
  END i[66]
  PIN i[67]
    DIRECTION INPUT ;
    USE SIGNAL ;
    PORT
      LAYER M4 ;
        RECT  0 31.056 0.084 31.08 ;
    END
  END i[67]
  PIN i[68]
    DIRECTION INPUT ;
    USE SIGNAL ;
    PORT
      LAYER M4 ;
        RECT  0 31.152 0.084 31.176 ;
    END
  END i[68]
  PIN i[69]
    DIRECTION INPUT ;
    USE SIGNAL ;
    PORT
      LAYER M4 ;
        RECT  0 31.248 0.084 31.272 ;
    END
  END i[69]
  PIN i[6]
    DIRECTION INPUT ;
    USE SIGNAL ;
    PORT
      LAYER M4 ;
        RECT  0 19.056 0.084 19.08 ;
    END
  END i[6]
  PIN i[70]
    DIRECTION INPUT ;
    USE SIGNAL ;
    PORT
      LAYER M4 ;
        RECT  0 31.344 0.084 31.368 ;
    END
  END i[70]
  PIN i[71]
    DIRECTION INPUT ;
    USE SIGNAL ;
    PORT
      LAYER M4 ;
        RECT  0 31.44 0.084 31.464 ;
    END
  END i[71]
  PIN i[72]
    DIRECTION INPUT ;
    USE SIGNAL ;
    PORT
      LAYER M4 ;
        RECT  0 31.536 0.084 31.56 ;
    END
  END i[72]
  PIN i[73]
    DIRECTION INPUT ;
    USE SIGNAL ;
    PORT
      LAYER M4 ;
        RECT  0 31.632 0.084 31.656 ;
    END
  END i[73]
  PIN i[74]
    DIRECTION INPUT ;
    USE SIGNAL ;
    PORT
      LAYER M4 ;
        RECT  0 31.728 0.084 31.752 ;
    END
  END i[74]
  PIN i[75]
    DIRECTION INPUT ;
    USE SIGNAL ;
    PORT
      LAYER M4 ;
        RECT  0 31.824 0.084 31.848 ;
    END
  END i[75]
  PIN i[76]
    DIRECTION INPUT ;
    USE SIGNAL ;
    PORT
      LAYER M4 ;
        RECT  0 31.92 0.084 31.944 ;
    END
  END i[76]
  PIN i[77]
    DIRECTION INPUT ;
    USE SIGNAL ;
    PORT
      LAYER M4 ;
        RECT  0 32.016 0.084 32.04 ;
    END
  END i[77]
  PIN i[78]
    DIRECTION INPUT ;
    USE SIGNAL ;
    PORT
      LAYER M4 ;
        RECT  0 32.112 0.084 32.136 ;
    END
  END i[78]
  PIN i[79]
    DIRECTION INPUT ;
    USE SIGNAL ;
    PORT
      LAYER M4 ;
        RECT  0 32.208 0.084 32.232 ;
    END
  END i[79]
  PIN i[7]
    DIRECTION INPUT ;
    USE SIGNAL ;
    PORT
      LAYER M4 ;
        RECT  0 19.152 0.084 19.176 ;
    END
  END i[7]
  PIN i[80]
    DIRECTION INPUT ;
    USE SIGNAL ;
    PORT
      LAYER M4 ;
        RECT  0 32.304 0.084 32.328 ;
    END
  END i[80]
  PIN i[81]
    DIRECTION INPUT ;
    USE SIGNAL ;
    PORT
      LAYER M4 ;
        RECT  0 32.4 0.084 32.424 ;
    END
  END i[81]
  PIN i[82]
    DIRECTION INPUT ;
    USE SIGNAL ;
    PORT
      LAYER M4 ;
        RECT  0 32.496 0.084 32.52 ;
    END
  END i[82]
  PIN i[83]
    DIRECTION INPUT ;
    USE SIGNAL ;
    PORT
      LAYER M4 ;
        RECT  0 32.592 0.084 32.616 ;
    END
  END i[83]
  PIN i[84]
    DIRECTION INPUT ;
    USE SIGNAL ;
    PORT
      LAYER M4 ;
        RECT  0 32.688 0.084 32.712 ;
    END
  END i[84]
  PIN i[85]
    DIRECTION INPUT ;
    USE SIGNAL ;
    PORT
      LAYER M4 ;
        RECT  0 32.784 0.084 32.808 ;
    END
  END i[85]
  PIN i[86]
    DIRECTION INPUT ;
    USE SIGNAL ;
    PORT
      LAYER M4 ;
        RECT  0 32.88 0.084 32.904 ;
    END
  END i[86]
  PIN i[87]
    DIRECTION INPUT ;
    USE SIGNAL ;
    PORT
      LAYER M4 ;
        RECT  0 32.976 0.084 33 ;
    END
  END i[87]
  PIN i[88]
    DIRECTION INPUT ;
    USE SIGNAL ;
    PORT
      LAYER M4 ;
        RECT  0 33.072 0.084 33.096 ;
    END
  END i[88]
  PIN i[89]
    DIRECTION INPUT ;
    USE SIGNAL ;
    PORT
      LAYER M4 ;
        RECT  0 33.168 0.084 33.192 ;
    END
  END i[89]
  PIN i[8]
    DIRECTION INPUT ;
    USE SIGNAL ;
    PORT
      LAYER M4 ;
        RECT  0 19.248 0.084 19.272 ;
    END
  END i[8]
  PIN i[90]
    DIRECTION INPUT ;
    USE SIGNAL ;
    PORT
      LAYER M4 ;
        RECT  0 33.264 0.084 33.288 ;
    END
  END i[90]
  PIN i[91]
    DIRECTION INPUT ;
    USE SIGNAL ;
    PORT
      LAYER M4 ;
        RECT  0 33.36 0.084 33.384 ;
    END
  END i[91]
  PIN i[92]
    DIRECTION INPUT ;
    USE SIGNAL ;
    PORT
      LAYER M4 ;
        RECT  0 33.456 0.084 33.48 ;
    END
  END i[92]
  PIN i[93]
    DIRECTION INPUT ;
    USE SIGNAL ;
    PORT
      LAYER M4 ;
        RECT  0 33.552 0.084 33.576 ;
    END
  END i[93]
  PIN i[94]
    DIRECTION INPUT ;
    USE SIGNAL ;
    PORT
      LAYER M4 ;
        RECT  0 33.648 0.084 33.672 ;
    END
  END i[94]
  PIN i[95]
    DIRECTION INPUT ;
    USE SIGNAL ;
    PORT
      LAYER M4 ;
        RECT  0 33.744 0.084 33.768 ;
    END
  END i[95]
  PIN i[96]
    DIRECTION INPUT ;
    USE SIGNAL ;
    PORT
      LAYER M4 ;
        RECT  0 21.552 0.084 21.576 ;
    END
  END i[96]
  PIN i[97]
    DIRECTION INPUT ;
    USE SIGNAL ;
    PORT
      LAYER M4 ;
        RECT  0 21.648 0.084 21.672 ;
    END
  END i[97]
  PIN i[98]
    DIRECTION INPUT ;
    USE SIGNAL ;
    PORT
      LAYER M4 ;
        RECT  0 21.744 0.084 21.768 ;
    END
  END i[98]
  PIN i[99]
    DIRECTION INPUT ;
    USE SIGNAL ;
    PORT
      LAYER M4 ;
        RECT  0 21.84 0.084 21.864 ;
    END
  END i[99]
  PIN i[9]
    DIRECTION INPUT ;
    USE SIGNAL ;
    PORT
      LAYER M4 ;
        RECT  0 19.344 0.084 19.368 ;
    END
  END i[9]
  PIN o[0]
    DIRECTION OUTPUT ;
    USE SIGNAL ;
    PORT
      LAYER M4 ;
        RECT  21.516 13.008 21.6 13.032 ;
    END
  END o[0]
  PIN o[100]
    DIRECTION OUTPUT ;
    USE SIGNAL ;
    PORT
      LAYER M4 ;
        RECT  21.516 7.248 21.6 7.272 ;
    END
  END o[100]
  PIN o[101]
    DIRECTION OUTPUT ;
    USE SIGNAL ;
    PORT
      LAYER M4 ;
        RECT  21.516 7.344 21.6 7.368 ;
    END
  END o[101]
  PIN o[102]
    DIRECTION OUTPUT ;
    USE SIGNAL ;
    PORT
      LAYER M4 ;
        RECT  21.516 7.44 21.6 7.464 ;
    END
  END o[102]
  PIN o[103]
    DIRECTION OUTPUT ;
    USE SIGNAL ;
    PORT
      LAYER M4 ;
        RECT  21.516 7.536 21.6 7.56 ;
    END
  END o[103]
  PIN o[104]
    DIRECTION OUTPUT ;
    USE SIGNAL ;
    PORT
      LAYER M4 ;
        RECT  21.516 7.632 21.6 7.656 ;
    END
  END o[104]
  PIN o[105]
    DIRECTION OUTPUT ;
    USE SIGNAL ;
    PORT
      LAYER M4 ;
        RECT  21.516 7.728 21.6 7.752 ;
    END
  END o[105]
  PIN o[106]
    DIRECTION OUTPUT ;
    USE SIGNAL ;
    PORT
      LAYER M4 ;
        RECT  21.516 7.824 21.6 7.848 ;
    END
  END o[106]
  PIN o[107]
    DIRECTION OUTPUT ;
    USE SIGNAL ;
    PORT
      LAYER M4 ;
        RECT  21.516 7.92 21.6 7.944 ;
    END
  END o[107]
  PIN o[108]
    DIRECTION OUTPUT ;
    USE SIGNAL ;
    PORT
      LAYER M4 ;
        RECT  21.516 8.016 21.6 8.04 ;
    END
  END o[108]
  PIN o[109]
    DIRECTION OUTPUT ;
    USE SIGNAL ;
    PORT
      LAYER M4 ;
        RECT  21.516 8.112 21.6 8.136 ;
    END
  END o[109]
  PIN o[10]
    DIRECTION OUTPUT ;
    USE SIGNAL ;
    PORT
      LAYER M4 ;
        RECT  21.516 13.968 21.6 13.992 ;
    END
  END o[10]
  PIN o[110]
    DIRECTION OUTPUT ;
    USE SIGNAL ;
    PORT
      LAYER M4 ;
        RECT  21.516 8.208 21.6 8.232 ;
    END
  END o[110]
  PIN o[111]
    DIRECTION OUTPUT ;
    USE SIGNAL ;
    PORT
      LAYER M4 ;
        RECT  21.516 8.304 21.6 8.328 ;
    END
  END o[111]
  PIN o[112]
    DIRECTION OUTPUT ;
    USE SIGNAL ;
    PORT
      LAYER M4 ;
        RECT  21.516 8.4 21.6 8.424 ;
    END
  END o[112]
  PIN o[113]
    DIRECTION OUTPUT ;
    USE SIGNAL ;
    PORT
      LAYER M4 ;
        RECT  21.516 8.496 21.6 8.52 ;
    END
  END o[113]
  PIN o[114]
    DIRECTION OUTPUT ;
    USE SIGNAL ;
    PORT
      LAYER M4 ;
        RECT  21.516 8.592 21.6 8.616 ;
    END
  END o[114]
  PIN o[115]
    DIRECTION OUTPUT ;
    USE SIGNAL ;
    PORT
      LAYER M4 ;
        RECT  21.516 8.688 21.6 8.712 ;
    END
  END o[115]
  PIN o[116]
    DIRECTION OUTPUT ;
    USE SIGNAL ;
    PORT
      LAYER M4 ;
        RECT  21.516 8.784 21.6 8.808 ;
    END
  END o[116]
  PIN o[117]
    DIRECTION OUTPUT ;
    USE SIGNAL ;
    PORT
      LAYER M4 ;
        RECT  21.516 8.88 21.6 8.904 ;
    END
  END o[117]
  PIN o[118]
    DIRECTION OUTPUT ;
    USE SIGNAL ;
    PORT
      LAYER M4 ;
        RECT  21.516 8.976 21.6 9 ;
    END
  END o[118]
  PIN o[119]
    DIRECTION OUTPUT ;
    USE SIGNAL ;
    PORT
      LAYER M4 ;
        RECT  21.516 9.072 21.6 9.096 ;
    END
  END o[119]
  PIN o[11]
    DIRECTION OUTPUT ;
    USE SIGNAL ;
    PORT
      LAYER M4 ;
        RECT  21.516 14.064 21.6 14.088 ;
    END
  END o[11]
  PIN o[120]
    DIRECTION OUTPUT ;
    USE SIGNAL ;
    PORT
      LAYER M4 ;
        RECT  21.516 9.168 21.6 9.192 ;
    END
  END o[120]
  PIN o[121]
    DIRECTION OUTPUT ;
    USE SIGNAL ;
    PORT
      LAYER M4 ;
        RECT  21.516 9.264 21.6 9.288 ;
    END
  END o[121]
  PIN o[122]
    DIRECTION OUTPUT ;
    USE SIGNAL ;
    PORT
      LAYER M4 ;
        RECT  21.516 9.36 21.6 9.384 ;
    END
  END o[122]
  PIN o[123]
    DIRECTION OUTPUT ;
    USE SIGNAL ;
    PORT
      LAYER M4 ;
        RECT  21.516 9.456 21.6 9.48 ;
    END
  END o[123]
  PIN o[124]
    DIRECTION OUTPUT ;
    USE SIGNAL ;
    PORT
      LAYER M4 ;
        RECT  21.516 9.552 21.6 9.576 ;
    END
  END o[124]
  PIN o[125]
    DIRECTION OUTPUT ;
    USE SIGNAL ;
    PORT
      LAYER M4 ;
        RECT  21.516 9.648 21.6 9.672 ;
    END
  END o[125]
  PIN o[126]
    DIRECTION OUTPUT ;
    USE SIGNAL ;
    PORT
      LAYER M4 ;
        RECT  21.516 9.744 21.6 9.768 ;
    END
  END o[126]
  PIN o[127]
    DIRECTION OUTPUT ;
    USE SIGNAL ;
    PORT
      LAYER M4 ;
        RECT  21.516 9.84 21.6 9.864 ;
    END
  END o[127]
  PIN o[128]
    DIRECTION OUTPUT ;
    USE SIGNAL ;
    PORT
      LAYER M4 ;
        RECT  21.516 16.08 21.6 16.104 ;
    END
  END o[128]
  PIN o[129]
    DIRECTION OUTPUT ;
    USE SIGNAL ;
    PORT
      LAYER M4 ;
        RECT  21.516 16.176 21.6 16.2 ;
    END
  END o[129]
  PIN o[12]
    DIRECTION OUTPUT ;
    USE SIGNAL ;
    PORT
      LAYER M4 ;
        RECT  21.516 14.16 21.6 14.184 ;
    END
  END o[12]
  PIN o[130]
    DIRECTION OUTPUT ;
    USE SIGNAL ;
    PORT
      LAYER M4 ;
        RECT  21.516 16.272 21.6 16.296 ;
    END
  END o[130]
  PIN o[131]
    DIRECTION OUTPUT ;
    USE SIGNAL ;
    PORT
      LAYER M4 ;
        RECT  21.516 16.368 21.6 16.392 ;
    END
  END o[131]
  PIN o[132]
    DIRECTION OUTPUT ;
    USE SIGNAL ;
    PORT
      LAYER M4 ;
        RECT  21.516 16.464 21.6 16.488 ;
    END
  END o[132]
  PIN o[133]
    DIRECTION OUTPUT ;
    USE SIGNAL ;
    PORT
      LAYER M4 ;
        RECT  21.516 16.56 21.6 16.584 ;
    END
  END o[133]
  PIN o[134]
    DIRECTION OUTPUT ;
    USE SIGNAL ;
    PORT
      LAYER M4 ;
        RECT  21.516 16.656 21.6 16.68 ;
    END
  END o[134]
  PIN o[135]
    DIRECTION OUTPUT ;
    USE SIGNAL ;
    PORT
      LAYER M4 ;
        RECT  21.516 16.752 21.6 16.776 ;
    END
  END o[135]
  PIN o[136]
    DIRECTION OUTPUT ;
    USE SIGNAL ;
    PORT
      LAYER M4 ;
        RECT  21.516 16.848 21.6 16.872 ;
    END
  END o[136]
  PIN o[137]
    DIRECTION OUTPUT ;
    USE SIGNAL ;
    PORT
      LAYER M4 ;
        RECT  21.516 16.944 21.6 16.968 ;
    END
  END o[137]
  PIN o[138]
    DIRECTION OUTPUT ;
    USE SIGNAL ;
    PORT
      LAYER M4 ;
        RECT  21.516 17.04 21.6 17.064 ;
    END
  END o[138]
  PIN o[139]
    DIRECTION OUTPUT ;
    USE SIGNAL ;
    PORT
      LAYER M4 ;
        RECT  21.516 17.136 21.6 17.16 ;
    END
  END o[139]
  PIN o[13]
    DIRECTION OUTPUT ;
    USE SIGNAL ;
    PORT
      LAYER M4 ;
        RECT  21.516 14.256 21.6 14.28 ;
    END
  END o[13]
  PIN o[140]
    DIRECTION OUTPUT ;
    USE SIGNAL ;
    PORT
      LAYER M4 ;
        RECT  21.516 17.232 21.6 17.256 ;
    END
  END o[140]
  PIN o[141]
    DIRECTION OUTPUT ;
    USE SIGNAL ;
    PORT
      LAYER M4 ;
        RECT  21.516 17.328 21.6 17.352 ;
    END
  END o[141]
  PIN o[142]
    DIRECTION OUTPUT ;
    USE SIGNAL ;
    PORT
      LAYER M4 ;
        RECT  21.516 17.424 21.6 17.448 ;
    END
  END o[142]
  PIN o[143]
    DIRECTION OUTPUT ;
    USE SIGNAL ;
    PORT
      LAYER M4 ;
        RECT  21.516 17.52 21.6 17.544 ;
    END
  END o[143]
  PIN o[144]
    DIRECTION OUTPUT ;
    USE SIGNAL ;
    PORT
      LAYER M4 ;
        RECT  21.516 17.616 21.6 17.64 ;
    END
  END o[144]
  PIN o[145]
    DIRECTION OUTPUT ;
    USE SIGNAL ;
    PORT
      LAYER M4 ;
        RECT  21.516 17.712 21.6 17.736 ;
    END
  END o[145]
  PIN o[146]
    DIRECTION OUTPUT ;
    USE SIGNAL ;
    PORT
      LAYER M4 ;
        RECT  21.516 17.808 21.6 17.832 ;
    END
  END o[146]
  PIN o[147]
    DIRECTION OUTPUT ;
    USE SIGNAL ;
    PORT
      LAYER M4 ;
        RECT  21.516 17.904 21.6 17.928 ;
    END
  END o[147]
  PIN o[148]
    DIRECTION OUTPUT ;
    USE SIGNAL ;
    PORT
      LAYER M4 ;
        RECT  21.516 18 21.6 18.024 ;
    END
  END o[148]
  PIN o[149]
    DIRECTION OUTPUT ;
    USE SIGNAL ;
    PORT
      LAYER M4 ;
        RECT  21.516 18.096 21.6 18.12 ;
    END
  END o[149]
  PIN o[14]
    DIRECTION OUTPUT ;
    USE SIGNAL ;
    PORT
      LAYER M4 ;
        RECT  21.516 14.352 21.6 14.376 ;
    END
  END o[14]
  PIN o[150]
    DIRECTION OUTPUT ;
    USE SIGNAL ;
    PORT
      LAYER M4 ;
        RECT  21.516 18.192 21.6 18.216 ;
    END
  END o[150]
  PIN o[151]
    DIRECTION OUTPUT ;
    USE SIGNAL ;
    PORT
      LAYER M4 ;
        RECT  21.516 18.288 21.6 18.312 ;
    END
  END o[151]
  PIN o[152]
    DIRECTION OUTPUT ;
    USE SIGNAL ;
    PORT
      LAYER M4 ;
        RECT  21.516 18.384 21.6 18.408 ;
    END
  END o[152]
  PIN o[153]
    DIRECTION OUTPUT ;
    USE SIGNAL ;
    PORT
      LAYER M4 ;
        RECT  21.516 18.48 21.6 18.504 ;
    END
  END o[153]
  PIN o[154]
    DIRECTION OUTPUT ;
    USE SIGNAL ;
    PORT
      LAYER M4 ;
        RECT  21.516 18.576 21.6 18.6 ;
    END
  END o[154]
  PIN o[155]
    DIRECTION OUTPUT ;
    USE SIGNAL ;
    PORT
      LAYER M4 ;
        RECT  21.516 18.672 21.6 18.696 ;
    END
  END o[155]
  PIN o[156]
    DIRECTION OUTPUT ;
    USE SIGNAL ;
    PORT
      LAYER M4 ;
        RECT  21.516 18.768 21.6 18.792 ;
    END
  END o[156]
  PIN o[157]
    DIRECTION OUTPUT ;
    USE SIGNAL ;
    PORT
      LAYER M4 ;
        RECT  21.516 18.864 21.6 18.888 ;
    END
  END o[157]
  PIN o[158]
    DIRECTION OUTPUT ;
    USE SIGNAL ;
    PORT
      LAYER M4 ;
        RECT  21.516 18.96 21.6 18.984 ;
    END
  END o[158]
  PIN o[159]
    DIRECTION OUTPUT ;
    USE SIGNAL ;
    PORT
      LAYER M4 ;
        RECT  21.516 19.056 21.6 19.08 ;
    END
  END o[159]
  PIN o[15]
    DIRECTION OUTPUT ;
    USE SIGNAL ;
    PORT
      LAYER M4 ;
        RECT  21.516 14.448 21.6 14.472 ;
    END
  END o[15]
  PIN o[160]
    DIRECTION OUTPUT ;
    USE SIGNAL ;
    PORT
      LAYER M4 ;
        RECT  21.516 3.792 21.6 3.816 ;
    END
  END o[160]
  PIN o[161]
    DIRECTION OUTPUT ;
    USE SIGNAL ;
    PORT
      LAYER M4 ;
        RECT  21.516 3.888 21.6 3.912 ;
    END
  END o[161]
  PIN o[162]
    DIRECTION OUTPUT ;
    USE SIGNAL ;
    PORT
      LAYER M4 ;
        RECT  21.516 3.984 21.6 4.008 ;
    END
  END o[162]
  PIN o[163]
    DIRECTION OUTPUT ;
    USE SIGNAL ;
    PORT
      LAYER M4 ;
        RECT  21.516 4.08 21.6 4.104 ;
    END
  END o[163]
  PIN o[164]
    DIRECTION OUTPUT ;
    USE SIGNAL ;
    PORT
      LAYER M4 ;
        RECT  21.516 4.176 21.6 4.2 ;
    END
  END o[164]
  PIN o[165]
    DIRECTION OUTPUT ;
    USE SIGNAL ;
    PORT
      LAYER M4 ;
        RECT  21.516 4.272 21.6 4.296 ;
    END
  END o[165]
  PIN o[166]
    DIRECTION OUTPUT ;
    USE SIGNAL ;
    PORT
      LAYER M4 ;
        RECT  21.516 4.368 21.6 4.392 ;
    END
  END o[166]
  PIN o[167]
    DIRECTION OUTPUT ;
    USE SIGNAL ;
    PORT
      LAYER M4 ;
        RECT  21.516 4.464 21.6 4.488 ;
    END
  END o[167]
  PIN o[168]
    DIRECTION OUTPUT ;
    USE SIGNAL ;
    PORT
      LAYER M4 ;
        RECT  21.516 4.56 21.6 4.584 ;
    END
  END o[168]
  PIN o[169]
    DIRECTION OUTPUT ;
    USE SIGNAL ;
    PORT
      LAYER M4 ;
        RECT  21.516 4.656 21.6 4.68 ;
    END
  END o[169]
  PIN o[16]
    DIRECTION OUTPUT ;
    USE SIGNAL ;
    PORT
      LAYER M4 ;
        RECT  21.516 14.544 21.6 14.568 ;
    END
  END o[16]
  PIN o[170]
    DIRECTION OUTPUT ;
    USE SIGNAL ;
    PORT
      LAYER M4 ;
        RECT  21.516 4.752 21.6 4.776 ;
    END
  END o[170]
  PIN o[171]
    DIRECTION OUTPUT ;
    USE SIGNAL ;
    PORT
      LAYER M4 ;
        RECT  21.516 4.848 21.6 4.872 ;
    END
  END o[171]
  PIN o[172]
    DIRECTION OUTPUT ;
    USE SIGNAL ;
    PORT
      LAYER M4 ;
        RECT  21.516 4.944 21.6 4.968 ;
    END
  END o[172]
  PIN o[173]
    DIRECTION OUTPUT ;
    USE SIGNAL ;
    PORT
      LAYER M4 ;
        RECT  21.516 5.04 21.6 5.064 ;
    END
  END o[173]
  PIN o[174]
    DIRECTION OUTPUT ;
    USE SIGNAL ;
    PORT
      LAYER M4 ;
        RECT  21.516 5.136 21.6 5.16 ;
    END
  END o[174]
  PIN o[175]
    DIRECTION OUTPUT ;
    USE SIGNAL ;
    PORT
      LAYER M4 ;
        RECT  21.516 5.232 21.6 5.256 ;
    END
  END o[175]
  PIN o[176]
    DIRECTION OUTPUT ;
    USE SIGNAL ;
    PORT
      LAYER M4 ;
        RECT  21.516 5.328 21.6 5.352 ;
    END
  END o[176]
  PIN o[177]
    DIRECTION OUTPUT ;
    USE SIGNAL ;
    PORT
      LAYER M4 ;
        RECT  21.516 5.424 21.6 5.448 ;
    END
  END o[177]
  PIN o[178]
    DIRECTION OUTPUT ;
    USE SIGNAL ;
    PORT
      LAYER M4 ;
        RECT  21.516 5.52 21.6 5.544 ;
    END
  END o[178]
  PIN o[179]
    DIRECTION OUTPUT ;
    USE SIGNAL ;
    PORT
      LAYER M4 ;
        RECT  21.516 5.616 21.6 5.64 ;
    END
  END o[179]
  PIN o[17]
    DIRECTION OUTPUT ;
    USE SIGNAL ;
    PORT
      LAYER M4 ;
        RECT  21.516 14.64 21.6 14.664 ;
    END
  END o[17]
  PIN o[180]
    DIRECTION OUTPUT ;
    USE SIGNAL ;
    PORT
      LAYER M4 ;
        RECT  21.516 5.712 21.6 5.736 ;
    END
  END o[180]
  PIN o[181]
    DIRECTION OUTPUT ;
    USE SIGNAL ;
    PORT
      LAYER M4 ;
        RECT  21.516 5.808 21.6 5.832 ;
    END
  END o[181]
  PIN o[182]
    DIRECTION OUTPUT ;
    USE SIGNAL ;
    PORT
      LAYER M4 ;
        RECT  21.516 5.904 21.6 5.928 ;
    END
  END o[182]
  PIN o[183]
    DIRECTION OUTPUT ;
    USE SIGNAL ;
    PORT
      LAYER M4 ;
        RECT  21.516 6 21.6 6.024 ;
    END
  END o[183]
  PIN o[184]
    DIRECTION OUTPUT ;
    USE SIGNAL ;
    PORT
      LAYER M4 ;
        RECT  21.516 6.096 21.6 6.12 ;
    END
  END o[184]
  PIN o[185]
    DIRECTION OUTPUT ;
    USE SIGNAL ;
    PORT
      LAYER M4 ;
        RECT  21.516 6.192 21.6 6.216 ;
    END
  END o[185]
  PIN o[186]
    DIRECTION OUTPUT ;
    USE SIGNAL ;
    PORT
      LAYER M4 ;
        RECT  21.516 6.288 21.6 6.312 ;
    END
  END o[186]
  PIN o[187]
    DIRECTION OUTPUT ;
    USE SIGNAL ;
    PORT
      LAYER M4 ;
        RECT  21.516 6.384 21.6 6.408 ;
    END
  END o[187]
  PIN o[188]
    DIRECTION OUTPUT ;
    USE SIGNAL ;
    PORT
      LAYER M4 ;
        RECT  21.516 6.48 21.6 6.504 ;
    END
  END o[188]
  PIN o[189]
    DIRECTION OUTPUT ;
    USE SIGNAL ;
    PORT
      LAYER M4 ;
        RECT  21.516 6.576 21.6 6.6 ;
    END
  END o[189]
  PIN o[18]
    DIRECTION OUTPUT ;
    USE SIGNAL ;
    PORT
      LAYER M4 ;
        RECT  21.516 14.736 21.6 14.76 ;
    END
  END o[18]
  PIN o[190]
    DIRECTION OUTPUT ;
    USE SIGNAL ;
    PORT
      LAYER M4 ;
        RECT  21.516 6.672 21.6 6.696 ;
    END
  END o[190]
  PIN o[191]
    DIRECTION OUTPUT ;
    USE SIGNAL ;
    PORT
      LAYER M4 ;
        RECT  21.516 6.768 21.6 6.792 ;
    END
  END o[191]
  PIN o[192]
    DIRECTION OUTPUT ;
    USE SIGNAL ;
    PORT
      LAYER M4 ;
        RECT  21.516 22.992 21.6 23.016 ;
    END
  END o[192]
  PIN o[193]
    DIRECTION OUTPUT ;
    USE SIGNAL ;
    PORT
      LAYER M4 ;
        RECT  21.516 23.088 21.6 23.112 ;
    END
  END o[193]
  PIN o[194]
    DIRECTION OUTPUT ;
    USE SIGNAL ;
    PORT
      LAYER M4 ;
        RECT  21.516 23.184 21.6 23.208 ;
    END
  END o[194]
  PIN o[195]
    DIRECTION OUTPUT ;
    USE SIGNAL ;
    PORT
      LAYER M4 ;
        RECT  21.516 23.28 21.6 23.304 ;
    END
  END o[195]
  PIN o[196]
    DIRECTION OUTPUT ;
    USE SIGNAL ;
    PORT
      LAYER M4 ;
        RECT  21.516 23.376 21.6 23.4 ;
    END
  END o[196]
  PIN o[197]
    DIRECTION OUTPUT ;
    USE SIGNAL ;
    PORT
      LAYER M4 ;
        RECT  21.516 23.472 21.6 23.496 ;
    END
  END o[197]
  PIN o[198]
    DIRECTION OUTPUT ;
    USE SIGNAL ;
    PORT
      LAYER M4 ;
        RECT  21.516 23.568 21.6 23.592 ;
    END
  END o[198]
  PIN o[199]
    DIRECTION OUTPUT ;
    USE SIGNAL ;
    PORT
      LAYER M4 ;
        RECT  21.516 23.664 21.6 23.688 ;
    END
  END o[199]
  PIN o[19]
    DIRECTION OUTPUT ;
    USE SIGNAL ;
    PORT
      LAYER M4 ;
        RECT  21.516 14.832 21.6 14.856 ;
    END
  END o[19]
  PIN o[1]
    DIRECTION OUTPUT ;
    USE SIGNAL ;
    PORT
      LAYER M4 ;
        RECT  21.516 13.104 21.6 13.128 ;
    END
  END o[1]
  PIN o[200]
    DIRECTION OUTPUT ;
    USE SIGNAL ;
    PORT
      LAYER M4 ;
        RECT  21.516 23.76 21.6 23.784 ;
    END
  END o[200]
  PIN o[201]
    DIRECTION OUTPUT ;
    USE SIGNAL ;
    PORT
      LAYER M4 ;
        RECT  21.516 23.856 21.6 23.88 ;
    END
  END o[201]
  PIN o[202]
    DIRECTION OUTPUT ;
    USE SIGNAL ;
    PORT
      LAYER M4 ;
        RECT  21.516 23.952 21.6 23.976 ;
    END
  END o[202]
  PIN o[203]
    DIRECTION OUTPUT ;
    USE SIGNAL ;
    PORT
      LAYER M4 ;
        RECT  21.516 24.048 21.6 24.072 ;
    END
  END o[203]
  PIN o[204]
    DIRECTION OUTPUT ;
    USE SIGNAL ;
    PORT
      LAYER M4 ;
        RECT  21.516 24.144 21.6 24.168 ;
    END
  END o[204]
  PIN o[205]
    DIRECTION OUTPUT ;
    USE SIGNAL ;
    PORT
      LAYER M4 ;
        RECT  21.516 24.24 21.6 24.264 ;
    END
  END o[205]
  PIN o[206]
    DIRECTION OUTPUT ;
    USE SIGNAL ;
    PORT
      LAYER M4 ;
        RECT  21.516 24.336 21.6 24.36 ;
    END
  END o[206]
  PIN o[207]
    DIRECTION OUTPUT ;
    USE SIGNAL ;
    PORT
      LAYER M4 ;
        RECT  21.516 24.432 21.6 24.456 ;
    END
  END o[207]
  PIN o[208]
    DIRECTION OUTPUT ;
    USE SIGNAL ;
    PORT
      LAYER M4 ;
        RECT  21.516 24.528 21.6 24.552 ;
    END
  END o[208]
  PIN o[209]
    DIRECTION OUTPUT ;
    USE SIGNAL ;
    PORT
      LAYER M4 ;
        RECT  21.516 24.624 21.6 24.648 ;
    END
  END o[209]
  PIN o[20]
    DIRECTION OUTPUT ;
    USE SIGNAL ;
    PORT
      LAYER M4 ;
        RECT  21.516 14.928 21.6 14.952 ;
    END
  END o[20]
  PIN o[210]
    DIRECTION OUTPUT ;
    USE SIGNAL ;
    PORT
      LAYER M4 ;
        RECT  21.516 24.72 21.6 24.744 ;
    END
  END o[210]
  PIN o[211]
    DIRECTION OUTPUT ;
    USE SIGNAL ;
    PORT
      LAYER M4 ;
        RECT  21.516 24.816 21.6 24.84 ;
    END
  END o[211]
  PIN o[212]
    DIRECTION OUTPUT ;
    USE SIGNAL ;
    PORT
      LAYER M4 ;
        RECT  21.516 24.912 21.6 24.936 ;
    END
  END o[212]
  PIN o[213]
    DIRECTION OUTPUT ;
    USE SIGNAL ;
    PORT
      LAYER M4 ;
        RECT  21.516 25.008 21.6 25.032 ;
    END
  END o[213]
  PIN o[214]
    DIRECTION OUTPUT ;
    USE SIGNAL ;
    PORT
      LAYER M4 ;
        RECT  21.516 25.104 21.6 25.128 ;
    END
  END o[214]
  PIN o[215]
    DIRECTION OUTPUT ;
    USE SIGNAL ;
    PORT
      LAYER M4 ;
        RECT  21.516 25.2 21.6 25.224 ;
    END
  END o[215]
  PIN o[216]
    DIRECTION OUTPUT ;
    USE SIGNAL ;
    PORT
      LAYER M4 ;
        RECT  21.516 25.296 21.6 25.32 ;
    END
  END o[216]
  PIN o[217]
    DIRECTION OUTPUT ;
    USE SIGNAL ;
    PORT
      LAYER M4 ;
        RECT  21.516 25.392 21.6 25.416 ;
    END
  END o[217]
  PIN o[218]
    DIRECTION OUTPUT ;
    USE SIGNAL ;
    PORT
      LAYER M4 ;
        RECT  21.516 25.488 21.6 25.512 ;
    END
  END o[218]
  PIN o[219]
    DIRECTION OUTPUT ;
    USE SIGNAL ;
    PORT
      LAYER M4 ;
        RECT  21.516 25.584 21.6 25.608 ;
    END
  END o[219]
  PIN o[21]
    DIRECTION OUTPUT ;
    USE SIGNAL ;
    PORT
      LAYER M4 ;
        RECT  21.516 15.024 21.6 15.048 ;
    END
  END o[21]
  PIN o[220]
    DIRECTION OUTPUT ;
    USE SIGNAL ;
    PORT
      LAYER M4 ;
        RECT  21.516 25.68 21.6 25.704 ;
    END
  END o[220]
  PIN o[221]
    DIRECTION OUTPUT ;
    USE SIGNAL ;
    PORT
      LAYER M4 ;
        RECT  21.516 25.776 21.6 25.8 ;
    END
  END o[221]
  PIN o[222]
    DIRECTION OUTPUT ;
    USE SIGNAL ;
    PORT
      LAYER M4 ;
        RECT  21.516 25.872 21.6 25.896 ;
    END
  END o[222]
  PIN o[223]
    DIRECTION OUTPUT ;
    USE SIGNAL ;
    PORT
      LAYER M4 ;
        RECT  21.516 25.968 21.6 25.992 ;
    END
  END o[223]
  PIN o[224]
    DIRECTION OUTPUT ;
    USE SIGNAL ;
    PORT
      LAYER M4 ;
        RECT  21.516 26.064 21.6 26.088 ;
    END
  END o[224]
  PIN o[225]
    DIRECTION OUTPUT ;
    USE SIGNAL ;
    PORT
      LAYER M4 ;
        RECT  21.516 26.16 21.6 26.184 ;
    END
  END o[225]
  PIN o[226]
    DIRECTION OUTPUT ;
    USE SIGNAL ;
    PORT
      LAYER M4 ;
        RECT  21.516 26.256 21.6 26.28 ;
    END
  END o[226]
  PIN o[227]
    DIRECTION OUTPUT ;
    USE SIGNAL ;
    PORT
      LAYER M4 ;
        RECT  21.516 26.352 21.6 26.376 ;
    END
  END o[227]
  PIN o[228]
    DIRECTION OUTPUT ;
    USE SIGNAL ;
    PORT
      LAYER M4 ;
        RECT  21.516 26.448 21.6 26.472 ;
    END
  END o[228]
  PIN o[229]
    DIRECTION OUTPUT ;
    USE SIGNAL ;
    PORT
      LAYER M4 ;
        RECT  21.516 26.544 21.6 26.568 ;
    END
  END o[229]
  PIN o[22]
    DIRECTION OUTPUT ;
    USE SIGNAL ;
    PORT
      LAYER M4 ;
        RECT  21.516 15.12 21.6 15.144 ;
    END
  END o[22]
  PIN o[230]
    DIRECTION OUTPUT ;
    USE SIGNAL ;
    PORT
      LAYER M4 ;
        RECT  21.516 26.64 21.6 26.664 ;
    END
  END o[230]
  PIN o[231]
    DIRECTION OUTPUT ;
    USE SIGNAL ;
    PORT
      LAYER M4 ;
        RECT  21.516 26.736 21.6 26.76 ;
    END
  END o[231]
  PIN o[232]
    DIRECTION OUTPUT ;
    USE SIGNAL ;
    PORT
      LAYER M4 ;
        RECT  21.516 26.832 21.6 26.856 ;
    END
  END o[232]
  PIN o[233]
    DIRECTION OUTPUT ;
    USE SIGNAL ;
    PORT
      LAYER M4 ;
        RECT  21.516 26.928 21.6 26.952 ;
    END
  END o[233]
  PIN o[234]
    DIRECTION OUTPUT ;
    USE SIGNAL ;
    PORT
      LAYER M4 ;
        RECT  21.516 27.024 21.6 27.048 ;
    END
  END o[234]
  PIN o[235]
    DIRECTION OUTPUT ;
    USE SIGNAL ;
    PORT
      LAYER M4 ;
        RECT  21.516 27.12 21.6 27.144 ;
    END
  END o[235]
  PIN o[236]
    DIRECTION OUTPUT ;
    USE SIGNAL ;
    PORT
      LAYER M4 ;
        RECT  21.516 27.216 21.6 27.24 ;
    END
  END o[236]
  PIN o[237]
    DIRECTION OUTPUT ;
    USE SIGNAL ;
    PORT
      LAYER M4 ;
        RECT  21.516 27.312 21.6 27.336 ;
    END
  END o[237]
  PIN o[238]
    DIRECTION OUTPUT ;
    USE SIGNAL ;
    PORT
      LAYER M4 ;
        RECT  21.516 27.408 21.6 27.432 ;
    END
  END o[238]
  PIN o[239]
    DIRECTION OUTPUT ;
    USE SIGNAL ;
    PORT
      LAYER M4 ;
        RECT  21.516 27.504 21.6 27.528 ;
    END
  END o[239]
  PIN o[23]
    DIRECTION OUTPUT ;
    USE SIGNAL ;
    PORT
      LAYER M4 ;
        RECT  21.516 15.216 21.6 15.24 ;
    END
  END o[23]
  PIN o[240]
    DIRECTION OUTPUT ;
    USE SIGNAL ;
    PORT
      LAYER M4 ;
        RECT  21.516 27.6 21.6 27.624 ;
    END
  END o[240]
  PIN o[241]
    DIRECTION OUTPUT ;
    USE SIGNAL ;
    PORT
      LAYER M4 ;
        RECT  21.516 27.696 21.6 27.72 ;
    END
  END o[241]
  PIN o[242]
    DIRECTION OUTPUT ;
    USE SIGNAL ;
    PORT
      LAYER M4 ;
        RECT  21.516 27.792 21.6 27.816 ;
    END
  END o[242]
  PIN o[243]
    DIRECTION OUTPUT ;
    USE SIGNAL ;
    PORT
      LAYER M4 ;
        RECT  21.516 27.888 21.6 27.912 ;
    END
  END o[243]
  PIN o[244]
    DIRECTION OUTPUT ;
    USE SIGNAL ;
    PORT
      LAYER M4 ;
        RECT  21.516 27.984 21.6 28.008 ;
    END
  END o[244]
  PIN o[245]
    DIRECTION OUTPUT ;
    USE SIGNAL ;
    PORT
      LAYER M4 ;
        RECT  21.516 28.08 21.6 28.104 ;
    END
  END o[245]
  PIN o[246]
    DIRECTION OUTPUT ;
    USE SIGNAL ;
    PORT
      LAYER M4 ;
        RECT  21.516 28.176 21.6 28.2 ;
    END
  END o[246]
  PIN o[247]
    DIRECTION OUTPUT ;
    USE SIGNAL ;
    PORT
      LAYER M4 ;
        RECT  21.516 28.272 21.6 28.296 ;
    END
  END o[247]
  PIN o[248]
    DIRECTION OUTPUT ;
    USE SIGNAL ;
    PORT
      LAYER M4 ;
        RECT  21.516 28.368 21.6 28.392 ;
    END
  END o[248]
  PIN o[249]
    DIRECTION OUTPUT ;
    USE SIGNAL ;
    PORT
      LAYER M4 ;
        RECT  21.516 28.464 21.6 28.488 ;
    END
  END o[249]
  PIN o[24]
    DIRECTION OUTPUT ;
    USE SIGNAL ;
    PORT
      LAYER M4 ;
        RECT  21.516 15.312 21.6 15.336 ;
    END
  END o[24]
  PIN o[250]
    DIRECTION OUTPUT ;
    USE SIGNAL ;
    PORT
      LAYER M4 ;
        RECT  21.516 28.56 21.6 28.584 ;
    END
  END o[250]
  PIN o[251]
    DIRECTION OUTPUT ;
    USE SIGNAL ;
    PORT
      LAYER M4 ;
        RECT  21.516 28.656 21.6 28.68 ;
    END
  END o[251]
  PIN o[252]
    DIRECTION OUTPUT ;
    USE SIGNAL ;
    PORT
      LAYER M4 ;
        RECT  21.516 28.752 21.6 28.776 ;
    END
  END o[252]
  PIN o[253]
    DIRECTION OUTPUT ;
    USE SIGNAL ;
    PORT
      LAYER M4 ;
        RECT  21.516 28.848 21.6 28.872 ;
    END
  END o[253]
  PIN o[254]
    DIRECTION OUTPUT ;
    USE SIGNAL ;
    PORT
      LAYER M4 ;
        RECT  21.516 28.944 21.6 28.968 ;
    END
  END o[254]
  PIN o[255]
    DIRECTION OUTPUT ;
    USE SIGNAL ;
    PORT
      LAYER M4 ;
        RECT  21.516 29.04 21.6 29.064 ;
    END
  END o[255]
  PIN o[256]
    DIRECTION OUTPUT ;
    USE SIGNAL ;
    PORT
      LAYER M4 ;
        RECT  21.516 19.92 21.6 19.944 ;
    END
  END o[256]
  PIN o[257]
    DIRECTION OUTPUT ;
    USE SIGNAL ;
    PORT
      LAYER M4 ;
        RECT  21.516 20.016 21.6 20.04 ;
    END
  END o[257]
  PIN o[258]
    DIRECTION OUTPUT ;
    USE SIGNAL ;
    PORT
      LAYER M4 ;
        RECT  21.516 20.112 21.6 20.136 ;
    END
  END o[258]
  PIN o[259]
    DIRECTION OUTPUT ;
    USE SIGNAL ;
    PORT
      LAYER M4 ;
        RECT  21.516 20.208 21.6 20.232 ;
    END
  END o[259]
  PIN o[25]
    DIRECTION OUTPUT ;
    USE SIGNAL ;
    PORT
      LAYER M4 ;
        RECT  21.516 15.408 21.6 15.432 ;
    END
  END o[25]
  PIN o[260]
    DIRECTION OUTPUT ;
    USE SIGNAL ;
    PORT
      LAYER M4 ;
        RECT  21.516 20.304 21.6 20.328 ;
    END
  END o[260]
  PIN o[261]
    DIRECTION OUTPUT ;
    USE SIGNAL ;
    PORT
      LAYER M4 ;
        RECT  21.516 20.4 21.6 20.424 ;
    END
  END o[261]
  PIN o[262]
    DIRECTION OUTPUT ;
    USE SIGNAL ;
    PORT
      LAYER M4 ;
        RECT  21.516 20.496 21.6 20.52 ;
    END
  END o[262]
  PIN o[263]
    DIRECTION OUTPUT ;
    USE SIGNAL ;
    PORT
      LAYER M4 ;
        RECT  21.516 20.592 21.6 20.616 ;
    END
  END o[263]
  PIN o[264]
    DIRECTION OUTPUT ;
    USE SIGNAL ;
    PORT
      LAYER M4 ;
        RECT  21.516 20.688 21.6 20.712 ;
    END
  END o[264]
  PIN o[265]
    DIRECTION OUTPUT ;
    USE SIGNAL ;
    PORT
      LAYER M4 ;
        RECT  21.516 20.784 21.6 20.808 ;
    END
  END o[265]
  PIN o[266]
    DIRECTION OUTPUT ;
    USE SIGNAL ;
    PORT
      LAYER M4 ;
        RECT  21.516 20.88 21.6 20.904 ;
    END
  END o[266]
  PIN o[267]
    DIRECTION OUTPUT ;
    USE SIGNAL ;
    PORT
      LAYER M4 ;
        RECT  21.516 20.976 21.6 21 ;
    END
  END o[267]
  PIN o[268]
    DIRECTION OUTPUT ;
    USE SIGNAL ;
    PORT
      LAYER M4 ;
        RECT  21.516 21.072 21.6 21.096 ;
    END
  END o[268]
  PIN o[269]
    DIRECTION OUTPUT ;
    USE SIGNAL ;
    PORT
      LAYER M4 ;
        RECT  21.516 21.168 21.6 21.192 ;
    END
  END o[269]
  PIN o[26]
    DIRECTION OUTPUT ;
    USE SIGNAL ;
    PORT
      LAYER M4 ;
        RECT  21.516 15.504 21.6 15.528 ;
    END
  END o[26]
  PIN o[270]
    DIRECTION OUTPUT ;
    USE SIGNAL ;
    PORT
      LAYER M4 ;
        RECT  21.516 21.264 21.6 21.288 ;
    END
  END o[270]
  PIN o[271]
    DIRECTION OUTPUT ;
    USE SIGNAL ;
    PORT
      LAYER M4 ;
        RECT  21.516 21.36 21.6 21.384 ;
    END
  END o[271]
  PIN o[272]
    DIRECTION OUTPUT ;
    USE SIGNAL ;
    PORT
      LAYER M4 ;
        RECT  21.516 21.456 21.6 21.48 ;
    END
  END o[272]
  PIN o[273]
    DIRECTION OUTPUT ;
    USE SIGNAL ;
    PORT
      LAYER M4 ;
        RECT  21.516 21.552 21.6 21.576 ;
    END
  END o[273]
  PIN o[274]
    DIRECTION OUTPUT ;
    USE SIGNAL ;
    PORT
      LAYER M4 ;
        RECT  21.516 21.648 21.6 21.672 ;
    END
  END o[274]
  PIN o[275]
    DIRECTION OUTPUT ;
    USE SIGNAL ;
    PORT
      LAYER M4 ;
        RECT  21.516 21.744 21.6 21.768 ;
    END
  END o[275]
  PIN o[276]
    DIRECTION OUTPUT ;
    USE SIGNAL ;
    PORT
      LAYER M4 ;
        RECT  21.516 21.84 21.6 21.864 ;
    END
  END o[276]
  PIN o[277]
    DIRECTION OUTPUT ;
    USE SIGNAL ;
    PORT
      LAYER M4 ;
        RECT  21.516 21.936 21.6 21.96 ;
    END
  END o[277]
  PIN o[278]
    DIRECTION OUTPUT ;
    USE SIGNAL ;
    PORT
      LAYER M4 ;
        RECT  21.516 22.032 21.6 22.056 ;
    END
  END o[278]
  PIN o[279]
    DIRECTION OUTPUT ;
    USE SIGNAL ;
    PORT
      LAYER M4 ;
        RECT  21.516 22.128 21.6 22.152 ;
    END
  END o[279]
  PIN o[27]
    DIRECTION OUTPUT ;
    USE SIGNAL ;
    PORT
      LAYER M4 ;
        RECT  21.516 15.6 21.6 15.624 ;
    END
  END o[27]
  PIN o[280]
    DIRECTION OUTPUT ;
    USE SIGNAL ;
    PORT
      LAYER M4 ;
        RECT  21.516 22.224 21.6 22.248 ;
    END
  END o[280]
  PIN o[281]
    DIRECTION OUTPUT ;
    USE SIGNAL ;
    PORT
      LAYER M4 ;
        RECT  21.516 22.32 21.6 22.344 ;
    END
  END o[281]
  PIN o[282]
    DIRECTION OUTPUT ;
    USE SIGNAL ;
    PORT
      LAYER M4 ;
        RECT  21.516 22.416 21.6 22.44 ;
    END
  END o[282]
  PIN o[283]
    DIRECTION OUTPUT ;
    USE SIGNAL ;
    PORT
      LAYER M4 ;
        RECT  21.516 22.512 21.6 22.536 ;
    END
  END o[283]
  PIN o[284]
    DIRECTION OUTPUT ;
    USE SIGNAL ;
    PORT
      LAYER M4 ;
        RECT  21.516 22.608 21.6 22.632 ;
    END
  END o[284]
  PIN o[285]
    DIRECTION OUTPUT ;
    USE SIGNAL ;
    PORT
      LAYER M4 ;
        RECT  21.516 22.704 21.6 22.728 ;
    END
  END o[285]
  PIN o[286]
    DIRECTION OUTPUT ;
    USE SIGNAL ;
    PORT
      LAYER M4 ;
        RECT  21.516 22.8 21.6 22.824 ;
    END
  END o[286]
  PIN o[287]
    DIRECTION OUTPUT ;
    USE SIGNAL ;
    PORT
      LAYER M4 ;
        RECT  21.516 22.896 21.6 22.92 ;
    END
  END o[287]
  PIN o[288]
    DIRECTION OUTPUT ;
    USE SIGNAL ;
    PORT
      LAYER M4 ;
        RECT  21.516 29.136 21.6 29.16 ;
    END
  END o[288]
  PIN o[289]
    DIRECTION OUTPUT ;
    USE SIGNAL ;
    PORT
      LAYER M4 ;
        RECT  21.516 29.232 21.6 29.256 ;
    END
  END o[289]
  PIN o[28]
    DIRECTION OUTPUT ;
    USE SIGNAL ;
    PORT
      LAYER M4 ;
        RECT  21.516 15.696 21.6 15.72 ;
    END
  END o[28]
  PIN o[290]
    DIRECTION OUTPUT ;
    USE SIGNAL ;
    PORT
      LAYER M4 ;
        RECT  21.516 29.328 21.6 29.352 ;
    END
  END o[290]
  PIN o[291]
    DIRECTION OUTPUT ;
    USE SIGNAL ;
    PORT
      LAYER M4 ;
        RECT  21.516 29.424 21.6 29.448 ;
    END
  END o[291]
  PIN o[292]
    DIRECTION OUTPUT ;
    USE SIGNAL ;
    PORT
      LAYER M4 ;
        RECT  21.516 29.52 21.6 29.544 ;
    END
  END o[292]
  PIN o[293]
    DIRECTION OUTPUT ;
    USE SIGNAL ;
    PORT
      LAYER M4 ;
        RECT  21.516 29.616 21.6 29.64 ;
    END
  END o[293]
  PIN o[294]
    DIRECTION OUTPUT ;
    USE SIGNAL ;
    PORT
      LAYER M4 ;
        RECT  21.516 29.712 21.6 29.736 ;
    END
  END o[294]
  PIN o[295]
    DIRECTION OUTPUT ;
    USE SIGNAL ;
    PORT
      LAYER M4 ;
        RECT  21.516 29.808 21.6 29.832 ;
    END
  END o[295]
  PIN o[296]
    DIRECTION OUTPUT ;
    USE SIGNAL ;
    PORT
      LAYER M4 ;
        RECT  21.516 29.904 21.6 29.928 ;
    END
  END o[296]
  PIN o[297]
    DIRECTION OUTPUT ;
    USE SIGNAL ;
    PORT
      LAYER M4 ;
        RECT  21.516 30 21.6 30.024 ;
    END
  END o[297]
  PIN o[298]
    DIRECTION OUTPUT ;
    USE SIGNAL ;
    PORT
      LAYER M4 ;
        RECT  21.516 30.096 21.6 30.12 ;
    END
  END o[298]
  PIN o[299]
    DIRECTION OUTPUT ;
    USE SIGNAL ;
    PORT
      LAYER M4 ;
        RECT  21.516 30.192 21.6 30.216 ;
    END
  END o[299]
  PIN o[29]
    DIRECTION OUTPUT ;
    USE SIGNAL ;
    PORT
      LAYER M4 ;
        RECT  21.516 15.792 21.6 15.816 ;
    END
  END o[29]
  PIN o[2]
    DIRECTION OUTPUT ;
    USE SIGNAL ;
    PORT
      LAYER M4 ;
        RECT  21.516 13.2 21.6 13.224 ;
    END
  END o[2]
  PIN o[300]
    DIRECTION OUTPUT ;
    USE SIGNAL ;
    PORT
      LAYER M4 ;
        RECT  21.516 30.288 21.6 30.312 ;
    END
  END o[300]
  PIN o[301]
    DIRECTION OUTPUT ;
    USE SIGNAL ;
    PORT
      LAYER M4 ;
        RECT  21.516 30.384 21.6 30.408 ;
    END
  END o[301]
  PIN o[302]
    DIRECTION OUTPUT ;
    USE SIGNAL ;
    PORT
      LAYER M4 ;
        RECT  21.516 30.48 21.6 30.504 ;
    END
  END o[302]
  PIN o[303]
    DIRECTION OUTPUT ;
    USE SIGNAL ;
    PORT
      LAYER M4 ;
        RECT  21.516 30.576 21.6 30.6 ;
    END
  END o[303]
  PIN o[30]
    DIRECTION OUTPUT ;
    USE SIGNAL ;
    PORT
      LAYER M4 ;
        RECT  21.516 15.888 21.6 15.912 ;
    END
  END o[30]
  PIN o[31]
    DIRECTION OUTPUT ;
    USE SIGNAL ;
    PORT
      LAYER M4 ;
        RECT  21.516 15.984 21.6 16.008 ;
    END
  END o[31]
  PIN o[32]
    DIRECTION OUTPUT ;
    USE SIGNAL ;
    PORT
      LAYER M4 ;
        RECT  21.516 9.936 21.6 9.96 ;
    END
  END o[32]
  PIN o[33]
    DIRECTION OUTPUT ;
    USE SIGNAL ;
    PORT
      LAYER M4 ;
        RECT  21.516 10.032 21.6 10.056 ;
    END
  END o[33]
  PIN o[34]
    DIRECTION OUTPUT ;
    USE SIGNAL ;
    PORT
      LAYER M4 ;
        RECT  21.516 10.128 21.6 10.152 ;
    END
  END o[34]
  PIN o[35]
    DIRECTION OUTPUT ;
    USE SIGNAL ;
    PORT
      LAYER M4 ;
        RECT  21.516 10.224 21.6 10.248 ;
    END
  END o[35]
  PIN o[36]
    DIRECTION OUTPUT ;
    USE SIGNAL ;
    PORT
      LAYER M4 ;
        RECT  21.516 10.32 21.6 10.344 ;
    END
  END o[36]
  PIN o[37]
    DIRECTION OUTPUT ;
    USE SIGNAL ;
    PORT
      LAYER M4 ;
        RECT  21.516 10.416 21.6 10.44 ;
    END
  END o[37]
  PIN o[38]
    DIRECTION OUTPUT ;
    USE SIGNAL ;
    PORT
      LAYER M4 ;
        RECT  21.516 10.512 21.6 10.536 ;
    END
  END o[38]
  PIN o[39]
    DIRECTION OUTPUT ;
    USE SIGNAL ;
    PORT
      LAYER M4 ;
        RECT  21.516 10.608 21.6 10.632 ;
    END
  END o[39]
  PIN o[3]
    DIRECTION OUTPUT ;
    USE SIGNAL ;
    PORT
      LAYER M4 ;
        RECT  21.516 13.296 21.6 13.32 ;
    END
  END o[3]
  PIN o[40]
    DIRECTION OUTPUT ;
    USE SIGNAL ;
    PORT
      LAYER M4 ;
        RECT  21.516 10.704 21.6 10.728 ;
    END
  END o[40]
  PIN o[41]
    DIRECTION OUTPUT ;
    USE SIGNAL ;
    PORT
      LAYER M4 ;
        RECT  21.516 10.8 21.6 10.824 ;
    END
  END o[41]
  PIN o[42]
    DIRECTION OUTPUT ;
    USE SIGNAL ;
    PORT
      LAYER M4 ;
        RECT  21.516 10.896 21.6 10.92 ;
    END
  END o[42]
  PIN o[43]
    DIRECTION OUTPUT ;
    USE SIGNAL ;
    PORT
      LAYER M4 ;
        RECT  21.516 10.992 21.6 11.016 ;
    END
  END o[43]
  PIN o[44]
    DIRECTION OUTPUT ;
    USE SIGNAL ;
    PORT
      LAYER M4 ;
        RECT  21.516 11.088 21.6 11.112 ;
    END
  END o[44]
  PIN o[45]
    DIRECTION OUTPUT ;
    USE SIGNAL ;
    PORT
      LAYER M4 ;
        RECT  21.516 11.184 21.6 11.208 ;
    END
  END o[45]
  PIN o[46]
    DIRECTION OUTPUT ;
    USE SIGNAL ;
    PORT
      LAYER M4 ;
        RECT  21.516 11.28 21.6 11.304 ;
    END
  END o[46]
  PIN o[47]
    DIRECTION OUTPUT ;
    USE SIGNAL ;
    PORT
      LAYER M4 ;
        RECT  21.516 11.376 21.6 11.4 ;
    END
  END o[47]
  PIN o[48]
    DIRECTION OUTPUT ;
    USE SIGNAL ;
    PORT
      LAYER M4 ;
        RECT  21.516 11.472 21.6 11.496 ;
    END
  END o[48]
  PIN o[49]
    DIRECTION OUTPUT ;
    USE SIGNAL ;
    PORT
      LAYER M4 ;
        RECT  21.516 11.568 21.6 11.592 ;
    END
  END o[49]
  PIN o[4]
    DIRECTION OUTPUT ;
    USE SIGNAL ;
    PORT
      LAYER M4 ;
        RECT  21.516 13.392 21.6 13.416 ;
    END
  END o[4]
  PIN o[50]
    DIRECTION OUTPUT ;
    USE SIGNAL ;
    PORT
      LAYER M4 ;
        RECT  21.516 11.664 21.6 11.688 ;
    END
  END o[50]
  PIN o[51]
    DIRECTION OUTPUT ;
    USE SIGNAL ;
    PORT
      LAYER M4 ;
        RECT  21.516 11.76 21.6 11.784 ;
    END
  END o[51]
  PIN o[52]
    DIRECTION OUTPUT ;
    USE SIGNAL ;
    PORT
      LAYER M4 ;
        RECT  21.516 11.856 21.6 11.88 ;
    END
  END o[52]
  PIN o[53]
    DIRECTION OUTPUT ;
    USE SIGNAL ;
    PORT
      LAYER M4 ;
        RECT  21.516 11.952 21.6 11.976 ;
    END
  END o[53]
  PIN o[54]
    DIRECTION OUTPUT ;
    USE SIGNAL ;
    PORT
      LAYER M4 ;
        RECT  21.516 12.048 21.6 12.072 ;
    END
  END o[54]
  PIN o[55]
    DIRECTION OUTPUT ;
    USE SIGNAL ;
    PORT
      LAYER M4 ;
        RECT  21.516 12.144 21.6 12.168 ;
    END
  END o[55]
  PIN o[56]
    DIRECTION OUTPUT ;
    USE SIGNAL ;
    PORT
      LAYER M4 ;
        RECT  21.516 12.24 21.6 12.264 ;
    END
  END o[56]
  PIN o[57]
    DIRECTION OUTPUT ;
    USE SIGNAL ;
    PORT
      LAYER M4 ;
        RECT  21.516 12.336 21.6 12.36 ;
    END
  END o[57]
  PIN o[58]
    DIRECTION OUTPUT ;
    USE SIGNAL ;
    PORT
      LAYER M4 ;
        RECT  21.516 12.432 21.6 12.456 ;
    END
  END o[58]
  PIN o[59]
    DIRECTION OUTPUT ;
    USE SIGNAL ;
    PORT
      LAYER M4 ;
        RECT  21.516 12.528 21.6 12.552 ;
    END
  END o[59]
  PIN o[5]
    DIRECTION OUTPUT ;
    USE SIGNAL ;
    PORT
      LAYER M4 ;
        RECT  21.516 13.488 21.6 13.512 ;
    END
  END o[5]
  PIN o[60]
    DIRECTION OUTPUT ;
    USE SIGNAL ;
    PORT
      LAYER M4 ;
        RECT  21.516 12.624 21.6 12.648 ;
    END
  END o[60]
  PIN o[61]
    DIRECTION OUTPUT ;
    USE SIGNAL ;
    PORT
      LAYER M4 ;
        RECT  21.516 12.72 21.6 12.744 ;
    END
  END o[61]
  PIN o[62]
    DIRECTION OUTPUT ;
    USE SIGNAL ;
    PORT
      LAYER M4 ;
        RECT  21.516 12.816 21.6 12.84 ;
    END
  END o[62]
  PIN o[63]
    DIRECTION OUTPUT ;
    USE SIGNAL ;
    PORT
      LAYER M4 ;
        RECT  21.516 12.912 21.6 12.936 ;
    END
  END o[63]
  PIN o[64]
    DIRECTION OUTPUT ;
    USE SIGNAL ;
    PORT
      LAYER M4 ;
        RECT  21.516 0.72 21.6 0.744 ;
    END
  END o[64]
  PIN o[65]
    DIRECTION OUTPUT ;
    USE SIGNAL ;
    PORT
      LAYER M4 ;
        RECT  21.516 0.816 21.6 0.84 ;
    END
  END o[65]
  PIN o[66]
    DIRECTION OUTPUT ;
    USE SIGNAL ;
    PORT
      LAYER M4 ;
        RECT  21.516 0.912 21.6 0.936 ;
    END
  END o[66]
  PIN o[67]
    DIRECTION OUTPUT ;
    USE SIGNAL ;
    PORT
      LAYER M4 ;
        RECT  21.516 1.008 21.6 1.032 ;
    END
  END o[67]
  PIN o[68]
    DIRECTION OUTPUT ;
    USE SIGNAL ;
    PORT
      LAYER M4 ;
        RECT  21.516 1.104 21.6 1.128 ;
    END
  END o[68]
  PIN o[69]
    DIRECTION OUTPUT ;
    USE SIGNAL ;
    PORT
      LAYER M4 ;
        RECT  21.516 1.2 21.6 1.224 ;
    END
  END o[69]
  PIN o[6]
    DIRECTION OUTPUT ;
    USE SIGNAL ;
    PORT
      LAYER M4 ;
        RECT  21.516 13.584 21.6 13.608 ;
    END
  END o[6]
  PIN o[70]
    DIRECTION OUTPUT ;
    USE SIGNAL ;
    PORT
      LAYER M4 ;
        RECT  21.516 1.296 21.6 1.32 ;
    END
  END o[70]
  PIN o[71]
    DIRECTION OUTPUT ;
    USE SIGNAL ;
    PORT
      LAYER M4 ;
        RECT  21.516 1.392 21.6 1.416 ;
    END
  END o[71]
  PIN o[72]
    DIRECTION OUTPUT ;
    USE SIGNAL ;
    PORT
      LAYER M4 ;
        RECT  21.516 1.488 21.6 1.512 ;
    END
  END o[72]
  PIN o[73]
    DIRECTION OUTPUT ;
    USE SIGNAL ;
    PORT
      LAYER M4 ;
        RECT  21.516 1.584 21.6 1.608 ;
    END
  END o[73]
  PIN o[74]
    DIRECTION OUTPUT ;
    USE SIGNAL ;
    PORT
      LAYER M4 ;
        RECT  21.516 1.68 21.6 1.704 ;
    END
  END o[74]
  PIN o[75]
    DIRECTION OUTPUT ;
    USE SIGNAL ;
    PORT
      LAYER M4 ;
        RECT  21.516 1.776 21.6 1.8 ;
    END
  END o[75]
  PIN o[76]
    DIRECTION OUTPUT ;
    USE SIGNAL ;
    PORT
      LAYER M4 ;
        RECT  21.516 1.872 21.6 1.896 ;
    END
  END o[76]
  PIN o[77]
    DIRECTION OUTPUT ;
    USE SIGNAL ;
    PORT
      LAYER M4 ;
        RECT  21.516 1.968 21.6 1.992 ;
    END
  END o[77]
  PIN o[78]
    DIRECTION OUTPUT ;
    USE SIGNAL ;
    PORT
      LAYER M4 ;
        RECT  21.516 2.064 21.6 2.088 ;
    END
  END o[78]
  PIN o[79]
    DIRECTION OUTPUT ;
    USE SIGNAL ;
    PORT
      LAYER M4 ;
        RECT  21.516 2.16 21.6 2.184 ;
    END
  END o[79]
  PIN o[7]
    DIRECTION OUTPUT ;
    USE SIGNAL ;
    PORT
      LAYER M4 ;
        RECT  21.516 13.68 21.6 13.704 ;
    END
  END o[7]
  PIN o[80]
    DIRECTION OUTPUT ;
    USE SIGNAL ;
    PORT
      LAYER M4 ;
        RECT  21.516 2.256 21.6 2.28 ;
    END
  END o[80]
  PIN o[81]
    DIRECTION OUTPUT ;
    USE SIGNAL ;
    PORT
      LAYER M4 ;
        RECT  21.516 2.352 21.6 2.376 ;
    END
  END o[81]
  PIN o[82]
    DIRECTION OUTPUT ;
    USE SIGNAL ;
    PORT
      LAYER M4 ;
        RECT  21.516 2.448 21.6 2.472 ;
    END
  END o[82]
  PIN o[83]
    DIRECTION OUTPUT ;
    USE SIGNAL ;
    PORT
      LAYER M4 ;
        RECT  21.516 2.544 21.6 2.568 ;
    END
  END o[83]
  PIN o[84]
    DIRECTION OUTPUT ;
    USE SIGNAL ;
    PORT
      LAYER M4 ;
        RECT  21.516 2.64 21.6 2.664 ;
    END
  END o[84]
  PIN o[85]
    DIRECTION OUTPUT ;
    USE SIGNAL ;
    PORT
      LAYER M4 ;
        RECT  21.516 2.736 21.6 2.76 ;
    END
  END o[85]
  PIN o[86]
    DIRECTION OUTPUT ;
    USE SIGNAL ;
    PORT
      LAYER M4 ;
        RECT  21.516 2.832 21.6 2.856 ;
    END
  END o[86]
  PIN o[87]
    DIRECTION OUTPUT ;
    USE SIGNAL ;
    PORT
      LAYER M4 ;
        RECT  21.516 2.928 21.6 2.952 ;
    END
  END o[87]
  PIN o[88]
    DIRECTION OUTPUT ;
    USE SIGNAL ;
    PORT
      LAYER M4 ;
        RECT  21.516 3.024 21.6 3.048 ;
    END
  END o[88]
  PIN o[89]
    DIRECTION OUTPUT ;
    USE SIGNAL ;
    PORT
      LAYER M4 ;
        RECT  21.516 3.12 21.6 3.144 ;
    END
  END o[89]
  PIN o[8]
    DIRECTION OUTPUT ;
    USE SIGNAL ;
    PORT
      LAYER M4 ;
        RECT  21.516 13.776 21.6 13.8 ;
    END
  END o[8]
  PIN o[90]
    DIRECTION OUTPUT ;
    USE SIGNAL ;
    PORT
      LAYER M4 ;
        RECT  21.516 3.216 21.6 3.24 ;
    END
  END o[90]
  PIN o[91]
    DIRECTION OUTPUT ;
    USE SIGNAL ;
    PORT
      LAYER M4 ;
        RECT  21.516 3.312 21.6 3.336 ;
    END
  END o[91]
  PIN o[92]
    DIRECTION OUTPUT ;
    USE SIGNAL ;
    PORT
      LAYER M4 ;
        RECT  21.516 3.408 21.6 3.432 ;
    END
  END o[92]
  PIN o[93]
    DIRECTION OUTPUT ;
    USE SIGNAL ;
    PORT
      LAYER M4 ;
        RECT  21.516 3.504 21.6 3.528 ;
    END
  END o[93]
  PIN o[94]
    DIRECTION OUTPUT ;
    USE SIGNAL ;
    PORT
      LAYER M4 ;
        RECT  21.516 3.6 21.6 3.624 ;
    END
  END o[94]
  PIN o[95]
    DIRECTION OUTPUT ;
    USE SIGNAL ;
    PORT
      LAYER M4 ;
        RECT  21.516 3.696 21.6 3.72 ;
    END
  END o[95]
  PIN o[96]
    DIRECTION OUTPUT ;
    USE SIGNAL ;
    PORT
      LAYER M4 ;
        RECT  21.516 6.864 21.6 6.888 ;
    END
  END o[96]
  PIN o[97]
    DIRECTION OUTPUT ;
    USE SIGNAL ;
    PORT
      LAYER M4 ;
        RECT  21.516 6.96 21.6 6.984 ;
    END
  END o[97]
  PIN o[98]
    DIRECTION OUTPUT ;
    USE SIGNAL ;
    PORT
      LAYER M4 ;
        RECT  21.516 7.056 21.6 7.08 ;
    END
  END o[98]
  PIN o[99]
    DIRECTION OUTPUT ;
    USE SIGNAL ;
    PORT
      LAYER M4 ;
        RECT  21.516 7.152 21.6 7.176 ;
    END
  END o[99]
  PIN o[9]
    DIRECTION OUTPUT ;
    USE SIGNAL ;
    PORT
      LAYER M4 ;
        RECT  21.516 13.872 21.6 13.896 ;
    END
  END o[9]
  PIN rfi
    DIRECTION INPUT ;
    USE SIGNAL ;
    PORT
      LAYER M4 ;
        RECT  0 5.328 0.084 5.352 ;
    END
  END rfi
  PIN rfo
    DIRECTION OUTPUT ;
    USE SIGNAL ;
    PORT
      LAYER M4 ;
        RECT  21.516 30.672 21.6 30.696 ;
    END
  END rfo
  PIN rs
    DIRECTION INPUT ;
    USE SIGNAL ;
    PORT
      LAYER M5 ;
        RECT  12.912 0 12.936 0.084 ;
    END
  END rs
  PIN VDD
    DIRECTION INOUT ;
    USE POWER ;
    PORT
      LAYER M5 ;
        RECT  18.792 2.151 18.912 32.409 ;
        RECT  16.092 2.151 16.212 32.409 ;
        RECT  13.392 2.151 13.512 32.409 ;
        RECT  10.692 2.151 10.812 32.409 ;
        RECT  7.992 2.151 8.112 32.409 ;
        RECT  5.292 2.151 5.412 32.409 ;
        RECT  2.592 2.151 2.712 32.409 ;
    END
  END VDD
  PIN VSS
    DIRECTION INOUT ;
    USE GROUND ;
    PORT
      LAYER M5 ;
        RECT  18.6 2.137 18.72 32.423 ;
        RECT  15.9 2.137 16.02 32.423 ;
        RECT  13.2 2.137 13.32 32.423 ;
        RECT  10.5 2.137 10.62 32.423 ;
        RECT  7.8 2.137 7.92 32.423 ;
        RECT  5.1 2.137 5.22 32.423 ;
        RECT  2.4 2.137 2.52 32.423 ;
    END
  END VSS
  # OT_OBS_CLOSED layer=M5 d_um=1.536 added=47
  OBS
    LAYER RVTN ;
     RECT  2.16 2.16 19.44 2.295 ;
     RECT  2.16 2.565 19.44 2.835 ;
     RECT  2.16 3.105 19.44 3.375 ;
     RECT  2.16 3.645 19.44 3.915 ;
     RECT  2.16 4.185 19.44 4.455 ;
     RECT  2.16 4.725 19.44 4.995 ;
     RECT  2.16 5.265 19.44 5.535 ;
     RECT  2.16 5.805 19.44 6.075 ;
     RECT  2.16 6.345 19.44 6.615 ;
     RECT  2.16 6.885 19.44 7.155 ;
     RECT  2.16 7.425 19.44 7.695 ;
     RECT  2.16 7.965 19.44 8.235 ;
     RECT  2.16 8.505 19.44 8.775 ;
     RECT  2.16 9.045 19.44 9.315 ;
     RECT  2.16 9.585 19.44 9.855 ;
     RECT  2.16 10.125 19.44 10.395 ;
     RECT  2.16 10.665 19.44 10.935 ;
     RECT  2.16 11.205 19.44 11.475 ;
     RECT  2.16 11.745 19.44 12.015 ;
     RECT  2.16 12.285 19.44 12.555 ;
     RECT  2.16 12.825 19.44 13.095 ;
     RECT  2.16 13.365 19.44 13.635 ;
     RECT  2.16 13.905 19.44 14.175 ;
     RECT  2.16 14.445 19.44 14.715 ;
     RECT  2.16 14.985 19.44 15.255 ;
     RECT  2.16 15.525 19.44 15.795 ;
     RECT  2.16 16.065 19.44 16.335 ;
     RECT  2.16 16.605 19.44 16.875 ;
     RECT  2.16 17.145 19.44 17.415 ;
     RECT  2.16 17.685 19.44 17.955 ;
     RECT  2.16 18.225 19.44 18.495 ;
     RECT  2.16 18.765 19.44 19.035 ;
     RECT  2.16 19.305 19.44 19.575 ;
     RECT  2.16 19.845 19.44 20.115 ;
     RECT  2.16 20.385 19.44 20.655 ;
     RECT  2.16 20.925 19.44 21.195 ;
     RECT  2.16 21.465 19.44 21.735 ;
     RECT  2.16 22.005 19.44 22.275 ;
     RECT  2.16 22.545 19.44 22.815 ;
     RECT  2.16 23.085 19.44 23.355 ;
     RECT  2.16 23.625 19.44 23.895 ;
     RECT  2.16 24.165 19.44 24.435 ;
     RECT  2.16 24.705 19.44 24.975 ;
     RECT  2.16 25.245 19.44 25.515 ;
     RECT  2.16 25.785 19.44 26.055 ;
     RECT  2.16 26.325 19.44 26.595 ;
     RECT  2.16 26.865 19.44 27.135 ;
     RECT  2.16 27.405 19.44 27.675 ;
     RECT  2.16 27.945 19.44 28.215 ;
     RECT  2.16 28.485 19.44 28.755 ;
     RECT  2.16 29.025 19.44 29.295 ;
     RECT  2.16 29.565 19.44 29.835 ;
     RECT  2.16 30.105 19.44 30.375 ;
     RECT  2.16 30.645 19.44 30.915 ;
     RECT  2.16 31.185 19.44 31.455 ;
     RECT  2.16 31.725 19.44 31.995 ;
     RECT  2.16 32.265 19.44 32.4 ;
    LAYER RVTP ;
     RECT  2.16 2.295 19.44 2.565 ;
     RECT  2.16 2.835 19.44 3.105 ;
     RECT  2.16 3.375 19.44 3.645 ;
     RECT  2.16 3.915 19.44 4.185 ;
     RECT  2.16 4.455 19.44 4.725 ;
     RECT  2.16 4.995 19.44 5.265 ;
     RECT  2.16 5.535 19.44 5.805 ;
     RECT  2.16 6.075 19.44 6.345 ;
     RECT  2.16 6.615 19.44 6.885 ;
     RECT  2.16 7.155 19.44 7.425 ;
     RECT  2.16 7.695 19.44 7.965 ;
     RECT  2.16 8.235 19.44 8.505 ;
     RECT  2.16 8.775 19.44 9.045 ;
     RECT  2.16 9.315 19.44 9.585 ;
     RECT  2.16 9.855 19.44 10.125 ;
     RECT  2.16 10.395 19.44 10.665 ;
     RECT  2.16 10.935 19.44 11.205 ;
     RECT  2.16 11.475 19.44 11.745 ;
     RECT  2.16 12.015 19.44 12.285 ;
     RECT  2.16 12.555 19.44 12.825 ;
     RECT  2.16 13.095 19.44 13.365 ;
     RECT  2.16 13.635 19.44 13.905 ;
     RECT  2.16 14.175 19.44 14.445 ;
     RECT  2.16 14.715 19.44 14.985 ;
     RECT  2.16 15.255 19.44 15.525 ;
     RECT  2.16 15.795 19.44 16.065 ;
     RECT  2.16 16.335 19.44 16.605 ;
     RECT  2.16 16.875 19.44 17.145 ;
     RECT  2.16 17.415 19.44 17.685 ;
     RECT  2.16 17.955 19.44 18.225 ;
     RECT  2.16 18.495 19.44 18.765 ;
     RECT  2.16 19.035 19.44 19.305 ;
     RECT  2.16 19.575 19.44 19.845 ;
     RECT  2.16 20.115 19.44 20.385 ;
     RECT  2.16 20.655 19.44 20.925 ;
     RECT  2.16 21.195 19.44 21.465 ;
     RECT  2.16 21.735 19.44 22.005 ;
     RECT  2.16 22.275 19.44 22.545 ;
     RECT  2.16 22.815 19.44 23.085 ;
     RECT  2.16 23.355 19.44 23.625 ;
     RECT  2.16 23.895 19.44 24.165 ;
     RECT  2.16 24.435 19.44 24.705 ;
     RECT  2.16 24.975 19.44 25.245 ;
     RECT  2.16 25.515 19.44 25.785 ;
     RECT  2.16 26.055 19.44 26.325 ;
     RECT  2.16 26.595 19.44 26.865 ;
     RECT  2.16 27.135 19.44 27.405 ;
     RECT  2.16 27.675 19.44 27.945 ;
     RECT  2.16 28.215 19.44 28.485 ;
     RECT  2.16 28.755 19.44 29.025 ;
     RECT  2.16 29.295 19.44 29.565 ;
     RECT  2.16 29.835 19.44 30.105 ;
     RECT  2.16 30.375 19.44 30.645 ;
     RECT  2.16 30.915 19.44 31.185 ;
     RECT  2.16 31.455 19.44 31.725 ;
     RECT  2.16 31.995 19.44 32.265 ;
    LAYER M1 ;
     RECT  2.16 2.151 19.44 32.409 ;
    LAYER M2 ;
     RECT  0.103 11.601 0.139 12.429 ;
     RECT  0.103 21.204 0.175 21.762 ;
     RECT  0.175 19.044 0.211 19.062 ;
     RECT  0.139 27.108 0.211 27.126 ;
     RECT  0.139 11.601 0.239 12.969 ;
     RECT  0.139 13.842 0.239 13.86 ;
     RECT  0.211 18.972 0.319 19.404 ;
     RECT  0.211 10.296 0.347 10.314 ;
     RECT  0.239 11.754 0.347 11.772 ;
     RECT  0.239 12.951 0.347 12.969 ;
     RECT  0.319 18.81 0.347 19.404 ;
     RECT  0.175 21.204 0.347 21.834 ;
     RECT  0.211 27.108 0.347 27.198 ;
     RECT  0.283 16.578 0.383 16.596 ;
     RECT  0.347 21.744 0.383 21.834 ;
     RECT  0.347 27.18 0.419 27.198 ;
     RECT  0.347 18.81 0.491 18.828 ;
     RECT  0.103 32.31 0.499 32.328 ;
     RECT  0.383 21.744 0.527 21.762 ;
     RECT  0.499 32.31 0.535 32.454 ;
     RECT  1.147 17.082 2.16 17.1 ;
     RECT  0.535 31.968 2.16 32.454 ;
     RECT  2.16 2.151 4.999 32.454 ;
     RECT  4.999 2.151 5.315 32.49 ;
     RECT  5.315 2.151 6.359 32.454 ;
     RECT  6.359 2.151 7.951 32.409 ;
     RECT  7.951 2.106 8.879 32.409 ;
     RECT  8.879 2.151 10.219 32.409 ;
     RECT  10.219 2.034 10.327 32.409 ;
     RECT  6.763 1.116 10.831 1.134 ;
     RECT  10.327 2.034 10.831 32.454 ;
     RECT  10.831 1.116 10.975 32.454 ;
     RECT  10.975 1.071 12.479 32.454 ;
     RECT  12.479 1.071 19.44 32.409 ;
     RECT  19.44 10.026 19.931 11.394 ;
     RECT  19.44 20.16 19.931 21.492 ;
     RECT  19.44 24.75 19.931 29.124 ;
     RECT  19.44 30.114 19.931 32.184 ;
     RECT  19.44 14.454 19.967 15.048 ;
     RECT  19.44 16.11 19.967 18.216 ;
     RECT  19.967 14.454 20.003 14.976 ;
     RECT  19.931 26.262 20.219 29.124 ;
     RECT  20.219 26.64 20.291 29.124 ;
     RECT  19.931 11.016 20.371 11.394 ;
     RECT  20.291 27.846 20.407 29.124 ;
     RECT  19.967 16.11 20.435 18.144 ;
     RECT  20.291 26.64 20.435 26.694 ;
     RECT  19.931 30.546 20.435 32.184 ;
     RECT  19.44 3.384 20.471 3.402 ;
     RECT  19.44 12.186 20.471 13.59 ;
     RECT  19.44 19.044 20.471 19.062 ;
     RECT  20.407 27.846 20.471 29.628 ;
     RECT  20.435 30.654 20.471 32.184 ;
     RECT  19.44 1.071 20.507 2.628 ;
     RECT  19.44 4.266 20.507 5.904 ;
     RECT  19.931 10.026 20.507 10.044 ;
     RECT  20.471 12.186 20.507 12.204 ;
     RECT  20.471 13.176 20.507 13.59 ;
     RECT  20.435 16.11 20.507 17.442 ;
     RECT  19.931 20.16 20.507 20.844 ;
     RECT  19.931 24.75 20.507 25.344 ;
     RECT  20.471 27.846 20.507 27.864 ;
     RECT  20.471 30.654 20.507 31.014 ;
     RECT  20.507 4.266 20.543 5.058 ;
     RECT  19.44 7.236 20.543 8.532 ;
     RECT  20.371 11.016 20.543 11.43 ;
     RECT  20.003 14.886 20.543 14.976 ;
     RECT  20.507 20.16 20.543 20.178 ;
     RECT  20.507 24.75 20.543 24.768 ;
     RECT  20.471 28.8 20.543 29.628 ;
     RECT  20.507 30.924 20.543 31.014 ;
     RECT  20.507 1.071 20.579 2.052 ;
     RECT  20.507 17.388 20.579 17.442 ;
     RECT  20.435 26.676 20.579 26.694 ;
     RECT  20.543 30.996 20.579 31.014 ;
     RECT  20.579 1.071 20.615 1.71 ;
     RECT  19.44 23.166 21.199 23.184 ;
     RECT  19.44 23.976 21.199 23.994 ;
     RECT  20.543 29.106 21.271 29.628 ;
     RECT  20.543 14.886 21.307 14.904 ;
     RECT  20.507 5.886 21.379 5.904 ;
     RECT  21.307 20.196 21.379 20.214 ;
     RECT  21.271 20.97 21.379 20.988 ;
     RECT  21.307 14.652 21.407 14.904 ;
     RECT  21.199 23.058 21.407 23.184 ;
     RECT  21.199 23.976 21.407 24.66 ;
     RECT  21.379 5.886 21.415 6.84 ;
     RECT  20.543 7.776 21.415 8.532 ;
     RECT  21.407 14.652 21.415 14.67 ;
     RECT  20.507 16.416 21.415 16.434 ;
     RECT  21.379 20.196 21.415 20.988 ;
     RECT  21.379 25.488 21.415 25.506 ;
     RECT  21.343 3.114 21.443 3.132 ;
     RECT  21.415 20.196 21.443 21.186 ;
     RECT  21.407 23.166 21.443 23.184 ;
     RECT  21.271 28.881 21.443 29.628 ;
     RECT  20.543 4.266 21.479 4.284 ;
     RECT  21.415 5.886 21.479 8.532 ;
     RECT  20.543 11.016 21.479 11.394 ;
     RECT  21.415 14.076 21.479 14.67 ;
     RECT  21.443 28.926 21.479 29.628 ;
     RECT  20.471 32.076 21.479 32.184 ;
     RECT  20.615 1.071 21.515 1.089 ;
     RECT  21.379 5.04 21.515 5.058 ;
     RECT  21.479 5.886 21.515 5.904 ;
     RECT  21.479 6.822 21.515 8.532 ;
     RECT  21.415 10.206 21.515 10.224 ;
     RECT  21.479 11.214 21.515 11.232 ;
     RECT  20.507 13.176 21.515 13.194 ;
     RECT  21.479 14.076 21.515 14.508 ;
     RECT  21.415 16.002 21.515 16.434 ;
     RECT  20.579 17.424 21.515 17.442 ;
     RECT  21.443 20.322 21.515 21.186 ;
     RECT  21.415 21.942 21.515 21.96 ;
     RECT  21.407 23.976 21.515 23.994 ;
     RECT  21.415 25.488 21.515 26.154 ;
     RECT  21.235 27.684 21.515 27.702 ;
     RECT  21.479 29.106 21.515 29.124 ;
     RECT  21.479 32.166 21.515 32.184 ;
    LAYER M3 ;
     RECT  11.34 0.811 11.358 1.066 ;
     RECT  10.98 1.066 11.358 1.099 ;
     RECT  12.456 0.091 12.474 1.099 ;
     RECT  9.648 1.483 9.666 1.579 ;
     RECT  13.644 0.907 13.662 1.675 ;
     RECT  9.648 1.579 10.206 1.687 ;
     RECT  10.98 1.099 12.474 1.687 ;
     RECT  19.908 0.715 19.926 1.687 ;
     RECT  18.396 1.111 18.414 1.723 ;
     RECT  18.396 1.723 18.45 1.759 ;
     RECT  15.192 1.759 15.21 1.771 ;
     RECT  15.192 1.771 15.894 1.819 ;
     RECT  21.492 1.066 21.51 1.819 ;
     RECT  13.536 1.675 13.662 1.831 ;
     RECT  14.796 1.819 15.894 1.831 ;
     RECT  18.072 1.759 18.45 1.831 ;
     RECT  9.648 1.687 12.474 1.867 ;
     RECT  13.536 1.831 15.894 1.867 ;
     RECT  17.82 1.831 18.45 1.876 ;
     RECT  9.648 1.867 15.894 1.915 ;
     RECT  17.82 1.876 18.81 1.957 ;
     RECT  6.768 1.111 6.786 2.011 ;
     RECT  17.46 1.957 18.81 2.029 ;
     RECT  7.776 1.963 7.794 2.059 ;
     RECT  7.776 2.059 8.262 2.101 ;
     RECT  19.908 1.687 20.61 2.129 ;
     RECT  9.612 1.915 15.894 2.143 ;
     RECT  5.115 2.143 5.205 2.191 ;
     RECT  6.228 2.011 6.786 2.191 ;
     RECT  17.388 2.029 18.81 2.191 ;
     RECT  7.776 2.101 8.874 2.227 ;
     RECT  9.612 2.143 16.005 2.227 ;
     RECT  7.776 2.227 16.005 2.251 ;
     RECT  7.776 2.251 16.362 2.263 ;
     RECT  7.776 2.263 16.47 2.299 ;
     RECT  17.388 2.191 18.846 2.299 ;
     RECT  2.415 2.143 2.505 2.335 ;
     RECT  7.632 2.299 16.47 2.335 ;
     RECT  17.352 2.299 18.846 2.335 ;
     RECT  2.232 2.335 2.505 2.347 ;
     RECT  2.232 2.347 2.574 2.371 ;
     RECT  7.56 2.335 18.846 2.371 ;
     RECT  2.232 2.371 2.898 2.491 ;
     RECT  5.115 2.191 6.786 2.533 ;
     RECT  7.56 2.371 19.314 2.533 ;
     RECT  2.232 2.491 3.114 2.731 ;
     RECT  20.448 2.129 20.61 2.875 ;
     RECT  21.42 1.819 21.51 2.875 ;
     RECT  2.232 2.731 3.582 3.109 ;
     RECT  20.448 2.875 21.51 3.245 ;
     RECT  5.115 2.533 19.314 3.271 ;
     RECT  2.232 3.109 3.654 3.299 ;
     RECT  2.304 3.299 3.654 3.343 ;
     RECT  4.5 3.271 19.314 3.343 ;
     RECT  20.448 3.245 20.466 3.407 ;
     RECT  2.304 3.343 19.314 3.499 ;
     RECT  2.304 3.499 19.386 3.677 ;
     RECT  21.42 3.245 21.51 3.917 ;
     RECT  21.42 3.917 21.474 3.979 ;
     RECT  21.348 3.979 21.474 4.075 ;
     RECT  21.276 4.075 21.474 4.205 ;
     RECT  21.384 4.205 21.474 4.289 ;
     RECT  20.52 4.423 20.538 4.459 ;
     RECT  2.304 3.677 19.278 4.487 ;
     RECT  21.384 4.289 21.438 4.939 ;
     RECT  21.348 4.939 21.438 5.035 ;
     RECT  0.144 4.699 0.162 5.069 ;
     RECT  2.304 4.487 19.098 5.227 ;
     RECT  20.484 4.459 20.538 5.305 ;
     RECT  20.448 5.305 20.538 5.357 ;
     RECT  20.484 5.357 20.538 5.369 ;
     RECT  20.52 5.369 20.538 5.645 ;
     RECT  21.348 5.035 21.51 5.995 ;
     RECT  21.276 5.995 21.51 6.283 ;
     RECT  0.144 6.139 0.162 6.317 ;
     RECT  21.24 6.283 21.51 6.413 ;
     RECT  21.312 6.413 21.51 7.243 ;
     RECT  2.304 5.227 19.314 7.357 ;
     RECT  21.276 7.243 21.51 7.373 ;
     RECT  2.232 7.357 19.314 7.435 ;
     RECT  20.52 7.231 20.538 7.435 ;
     RECT  2.232 7.435 20.538 7.493 ;
     RECT  2.232 7.493 19.314 7.565 ;
     RECT  0.324 7.531 0.342 7.661 ;
     RECT  20.52 7.493 20.538 7.949 ;
     RECT  2.268 7.565 19.314 8.195 ;
     RECT  21.312 7.373 21.51 8.537 ;
     RECT  2.304 8.195 19.314 8.573 ;
     RECT  2.304 8.573 19.098 8.699 ;
     RECT  2.304 8.699 18.99 8.861 ;
     RECT  21.312 8.537 21.474 9.005 ;
     RECT  0.144 8.011 0.162 9.019 ;
     RECT  2.304 8.861 18.954 9.211 ;
     RECT  2.268 9.211 18.954 9.247 ;
     RECT  2.196 9.247 18.954 9.293 ;
     RECT  19.908 9.163 19.926 9.547 ;
     RECT  2.268 9.293 18.954 9.617 ;
     RECT  2.304 9.617 18.954 9.661 ;
     RECT  19.908 9.547 20.502 9.661 ;
     RECT  21.348 9.005 21.438 9.739 ;
     RECT  0.144 9.019 0.234 10.027 ;
     RECT  2.304 9.661 20.502 10.049 ;
     RECT  21.24 9.739 21.438 10.157 ;
     RECT  21.42 10.157 21.438 10.201 ;
     RECT  0.144 10.027 0.342 10.219 ;
     RECT  0.144 10.219 0.594 10.397 ;
     RECT  2.304 10.049 19.926 10.463 ;
     RECT  2.304 10.463 19.386 10.471 ;
     RECT  2.232 10.471 19.386 10.499 ;
     RECT  21.42 10.201 21.51 11.237 ;
     RECT  2.232 10.499 19.35 11.261 ;
     RECT  20.376 11.371 20.502 11.407 ;
     RECT  20.376 11.407 20.538 11.435 ;
     RECT  0.144 10.397 0.342 11.563 ;
     RECT  21.42 11.237 21.474 11.563 ;
     RECT  21.276 11.563 21.474 11.693 ;
     RECT  0.108 11.563 0.342 11.789 ;
     RECT  21.348 11.693 21.474 11.981 ;
     RECT  20.448 11.435 20.538 12.269 ;
     RECT  2.304 11.261 19.35 12.389 ;
     RECT  0.108 11.789 0.234 12.557 ;
     RECT  20.448 12.269 20.466 12.659 ;
     RECT  12.312 12.389 19.35 12.715 ;
     RECT  12.312 12.715 19.386 12.901 ;
     RECT  0.144 12.557 0.234 12.946 ;
     RECT  0.144 12.946 0.342 13.037 ;
     RECT  21.384 11.981 21.474 13.099 ;
     RECT  21.312 13.099 21.51 13.199 ;
     RECT  21.312 13.199 21.474 13.325 ;
     RECT  2.304 12.389 11.43 13.333 ;
     RECT  12.312 12.901 19.422 13.333 ;
     RECT  2.304 13.333 19.422 13.405 ;
     RECT  2.268 13.405 19.422 13.421 ;
     RECT  20.484 13.567 20.502 13.613 ;
     RECT  2.268 13.421 19.386 13.639 ;
     RECT  2.232 13.639 19.386 13.667 ;
     RECT  21.312 13.325 21.438 13.675 ;
     RECT  21.204 13.675 21.438 13.805 ;
     RECT  21.312 13.805 21.438 14.059 ;
     RECT  2.232 13.667 19.314 14.099 ;
     RECT  2.232 14.099 19.062 14.135 ;
     RECT  18.252 14.135 19.062 14.243 ;
     RECT  0.144 13.037 0.234 14.429 ;
     RECT  21.312 14.059 21.51 14.513 ;
     RECT  1.152 14.539 1.17 14.669 ;
     RECT  21.312 14.513 21.474 14.675 ;
     RECT  0.216 14.429 0.234 14.717 ;
     RECT  21.312 14.675 21.402 14.909 ;
     RECT  19.944 14.449 19.998 14.953 ;
     RECT  19.944 14.953 20.538 15.053 ;
     RECT  2.232 14.135 17.406 15.259 ;
     RECT  18.288 14.243 19.062 15.259 ;
     RECT  2.232 15.259 19.062 15.295 ;
     RECT  21.312 14.909 21.33 15.533 ;
     RECT  2.232 15.295 19.134 15.557 ;
     RECT  2.268 15.557 19.134 15.629 ;
     RECT  19.944 15.053 20.43 15.883 ;
     RECT  2.304 15.629 19.134 16.069 ;
     RECT  19.944 15.883 20.502 16.069 ;
     RECT  2.304 16.069 20.502 16.301 ;
     RECT  21.42 15.979 21.51 16.363 ;
     RECT  21.312 16.363 21.51 16.493 ;
     RECT  0.144 16.363 0.162 16.555 ;
     RECT  0.144 16.555 0.306 16.573 ;
     RECT  2.304 16.301 19.386 16.645 ;
     RECT  2.268 16.645 19.386 16.781 ;
     RECT  2.304 16.781 19.386 16.979 ;
     RECT  1.152 17.077 1.17 17.213 ;
     RECT  20.484 16.301 20.502 17.383 ;
     RECT  21.42 16.493 21.51 17.447 ;
     RECT  20.484 17.383 20.574 17.515 ;
     RECT  21.42 17.447 21.438 17.645 ;
     RECT  20.448 17.515 20.574 17.851 ;
     RECT  2.304 16.979 19.026 17.887 ;
     RECT  0.144 16.573 0.378 18.029 ;
     RECT  0.144 18.029 0.306 18.077 ;
     RECT  20.16 17.851 20.574 18.193 ;
     RECT  19.944 18.193 20.574 18.221 ;
     RECT  2.304 17.887 19.098 18.301 ;
     RECT  19.944 18.221 20.466 18.317 ;
     RECT  2.268 18.301 19.098 18.427 ;
     RECT  1.152 18.427 1.17 18.605 ;
     RECT  0.252 18.077 0.306 18.763 ;
     RECT  21.312 17.899 21.33 18.797 ;
     RECT  0.252 18.763 0.342 18.805 ;
     RECT  2.268 18.427 19.386 18.869 ;
     RECT  0.252 18.805 0.486 18.893 ;
     RECT  0.252 18.893 0.342 18.955 ;
     RECT  20.448 18.317 20.466 19.067 ;
     RECT  2.304 18.869 19.386 19.139 ;
     RECT  0.18 18.955 0.342 19.339 ;
     RECT  0.144 19.339 0.342 19.613 ;
     RECT  0.252 19.613 0.342 19.723 ;
     RECT  1.152 19.723 1.17 19.853 ;
     RECT  0.252 19.723 0.378 19.963 ;
     RECT  21.312 20.011 21.33 20.107 ;
     RECT  2.304 19.139 19.35 20.191 ;
     RECT  20.52 20.155 20.538 20.191 ;
     RECT  0.252 19.963 0.414 20.285 ;
     RECT  21.312 20.107 21.438 20.299 ;
     RECT  2.304 20.191 20.538 20.429 ;
     RECT  21.312 20.299 21.51 20.779 ;
     RECT  2.304 20.429 20.502 20.849 ;
     RECT  1.152 20.875 1.17 21.005 ;
     RECT  21.276 20.779 21.51 21.005 ;
     RECT  0.288 20.285 0.414 21.163 ;
     RECT  21.42 21.005 21.51 21.197 ;
     RECT  0.108 21.163 0.414 21.355 ;
     RECT  2.304 20.849 19.962 21.497 ;
     RECT  0.108 21.355 0.522 21.767 ;
     RECT  0.108 21.767 0.378 21.773 ;
     RECT  0.144 21.773 0.378 21.839 ;
     RECT  0.144 21.839 0.198 21.869 ;
     RECT  21.42 21.197 21.438 21.931 ;
     RECT  21.42 21.931 21.51 21.965 ;
     RECT  2.304 21.497 19.386 22.081 ;
     RECT  0.144 21.869 0.162 22.109 ;
     RECT  2.268 22.081 19.386 22.171 ;
     RECT  2.232 22.171 19.386 22.253 ;
     RECT  21.42 21.965 21.438 22.267 ;
     RECT  21.348 22.267 21.438 22.459 ;
     RECT  0.324 22.795 0.342 22.925 ;
     RECT  21.276 22.459 21.438 23.035 ;
     RECT  21.204 23.035 21.438 23.081 ;
     RECT  21.276 23.081 21.438 23.117 ;
     RECT  21.312 23.117 21.438 23.309 ;
     RECT  21.348 23.309 21.438 23.563 ;
     RECT  20.196 21.835 20.214 23.755 ;
     RECT  2.232 22.253 19.314 23.963 ;
     RECT  21.348 23.563 21.51 23.999 ;
     RECT  2.304 23.963 19.314 24.043 ;
     RECT  2.304 24.043 19.422 24.269 ;
     RECT  21.348 23.999 21.438 24.523 ;
     RECT  20.196 23.755 20.502 24.637 ;
     RECT  21.276 24.523 21.438 24.637 ;
     RECT  0.144 24.475 0.162 24.653 ;
     RECT  20.196 24.637 21.438 24.701 ;
     RECT  20.196 24.701 20.538 24.781 ;
     RECT  2.304 24.269 19.17 24.811 ;
     RECT  19.944 24.781 20.538 24.845 ;
     RECT  19.944 24.845 20.502 24.941 ;
     RECT  2.268 24.811 19.17 25.291 ;
     RECT  0.18 25.051 0.198 25.325 ;
     RECT  20.196 24.941 20.502 25.349 ;
     RECT  21.348 24.701 21.438 25.483 ;
     RECT  20.196 25.349 20.214 25.771 ;
     RECT  0.144 25.531 0.162 25.997 ;
     RECT  21.348 25.483 21.51 26.045 ;
     RECT  19.908 25.771 20.214 26.087 ;
     RECT  21.42 26.045 21.51 26.189 ;
     RECT  20.196 26.087 20.214 26.251 ;
     RECT  20.196 26.251 20.502 26.285 ;
     RECT  20.268 26.285 20.502 26.347 ;
     RECT  2.232 25.291 19.17 26.573 ;
     RECT  2.304 26.573 19.17 26.599 ;
     RECT  20.268 26.347 20.538 26.671 ;
     RECT  20.268 26.671 20.574 26.765 ;
     RECT  0.18 26.347 0.198 26.827 ;
     RECT  0.144 26.827 0.198 26.923 ;
     RECT  21.384 26.779 21.402 26.923 ;
     RECT  0.144 26.923 0.306 27.103 ;
     RECT  2.304 26.599 19.278 27.115 ;
     RECT  0.144 27.103 0.342 27.163 ;
     RECT  0.144 27.163 0.414 27.203 ;
     RECT  2.304 27.115 19.314 27.211 ;
     RECT  20.268 26.765 20.538 27.211 ;
     RECT  0.144 27.203 0.342 27.245 ;
     RECT  21.384 26.923 21.438 27.451 ;
     RECT  0.144 27.245 0.306 27.581 ;
     RECT  2.304 27.211 20.538 27.595 ;
     RECT  21.312 27.451 21.438 27.595 ;
     RECT  0.288 27.581 0.306 27.629 ;
     RECT  2.304 27.595 21.438 27.679 ;
     RECT  2.304 27.679 21.51 27.707 ;
     RECT  2.304 27.707 20.538 27.913 ;
     RECT  0.324 27.979 0.342 28.781 ;
     RECT  21.312 27.707 21.51 28.876 ;
     RECT  2.232 27.913 20.538 29.093 ;
     RECT  21.276 28.876 21.51 29.129 ;
     RECT  21.276 29.129 21.474 29.645 ;
     RECT  21.348 29.645 21.474 29.995 ;
     RECT  2.304 29.093 20.538 30.137 ;
     RECT  21.348 29.995 21.51 30.221 ;
     RECT  2.304 30.137 19.314 30.283 ;
     RECT  20.412 30.137 20.538 30.283 ;
     RECT  2.232 30.283 19.314 30.443 ;
     RECT  20.412 30.283 20.574 30.569 ;
     RECT  0.324 30.475 0.342 30.571 ;
     RECT  0.144 30.571 0.342 30.605 ;
     RECT  2.268 30.443 19.314 30.749 ;
     RECT  21.42 30.221 21.51 30.797 ;
     RECT  20.448 30.569 20.574 31.019 ;
     RECT  0.144 30.605 0.198 31.133 ;
     RECT  0.18 31.133 0.198 31.339 ;
     RECT  20.448 31.019 20.466 31.487 ;
     RECT  0.18 31.339 0.342 31.723 ;
     RECT  2.304 30.749 19.314 31.805 ;
     RECT  2.34 31.805 19.314 31.829 ;
     RECT  15.372 31.829 19.314 31.919 ;
     RECT  0.18 31.723 0.522 31.963 ;
     RECT  15.372 31.919 19.026 32.027 ;
     RECT  18.615 32.027 19.026 32.063 ;
     RECT  15.372 32.027 17.694 32.099 ;
     RECT  21.456 30.797 21.51 32.099 ;
     RECT  2.34 31.829 14.634 32.147 ;
     RECT  18.615 32.063 18.897 32.147 ;
     RECT  2.34 32.147 13.305 32.189 ;
     RECT  14.184 32.147 14.634 32.189 ;
     RECT  15.876 32.099 17.694 32.189 ;
     RECT  21.492 32.099 21.51 32.189 ;
     RECT  9.216 32.189 10.962 32.225 ;
     RECT  11.808 32.189 13.305 32.225 ;
     RECT  14.616 32.189 14.634 32.237 ;
     RECT  0.18 31.963 0.558 32.251 ;
     RECT  10.008 32.225 10.605 32.261 ;
     RECT  12.06 32.225 13.305 32.261 ;
     RECT  15.876 32.189 16.005 32.261 ;
     RECT  2.34 32.189 6.966 32.297 ;
     RECT  0.144 32.251 0.558 32.305 ;
     RECT  2.34 32.297 5.31 32.333 ;
     RECT  6.336 32.297 6.966 32.333 ;
     RECT  12.456 32.261 13.305 32.333 ;
     RECT  17.1 32.189 17.478 32.333 ;
     RECT  9.216 32.225 9.234 32.369 ;
     RECT  17.46 32.333 17.478 32.369 ;
     RECT  7.704 32.189 7.905 32.417 ;
     RECT  10.332 32.261 10.605 32.417 ;
     RECT  13.215 32.333 13.305 32.417 ;
     RECT  15.915 32.261 16.005 32.417 ;
     RECT  18.615 32.147 18.705 32.417 ;
     RECT  4.932 32.333 5.31 32.429 ;
     RECT  6.336 32.333 6.354 32.459 ;
     RECT  10.332 32.417 10.35 32.459 ;
     RECT  12.456 32.333 12.474 32.459 ;
     RECT  7.704 32.417 7.722 32.477 ;
     RECT  5.004 32.429 5.31 32.495 ;
     RECT  0.108 32.305 0.558 32.525 ;
     RECT  0.108 32.525 0.522 32.717 ;
     RECT  0.504 32.717 0.522 32.813 ;
     RECT  2.34 32.333 3.834 32.909 ;
     RECT  2.88 32.909 3.834 33.101 ;
     RECT  2.88 33.101 3.546 33.293 ;
     RECT  3.528 33.293 3.546 33.773 ;
    LAYER M4 ;
     RECT  0.084 3.792 0.133 3.816 ;
     RECT  0.06 3.816 0.133 3.888 ;
     RECT  0.084 3.888 0.133 3.912 ;
     RECT  0.06 3.912 0.133 3.984 ;
     RECT  0.084 3.984 0.133 4.008 ;
     RECT  0.06 4.008 0.133 4.08 ;
     RECT  0.084 4.08 0.133 4.104 ;
     RECT  0.06 4.104 0.133 4.176 ;
     RECT  0.084 4.176 0.133 4.2 ;
     RECT  0.06 4.2 0.133 4.272 ;
     RECT  0.084 4.272 0.133 4.296 ;
     RECT  0.06 4.296 0.133 4.368 ;
     RECT  0.084 4.368 0.133 4.392 ;
     RECT  0.06 4.392 0.133 4.464 ;
     RECT  0.084 4.464 0.133 4.488 ;
     RECT  0.06 4.488 0.133 4.56 ;
     RECT  0.084 4.56 0.133 4.584 ;
     RECT  0.06 4.584 0.133 4.656 ;
     RECT  0.084 4.656 0.133 4.68 ;
     RECT  0.06 4.68 0.133 4.752 ;
     RECT  0.084 4.752 0.133 4.776 ;
     RECT  0.06 4.776 0.133 4.848 ;
     RECT  0.084 4.848 0.133 4.872 ;
     RECT  0.06 4.872 0.133 4.944 ;
     RECT  0.084 4.944 0.133 4.968 ;
     RECT  0.06 4.968 0.133 5.04 ;
     RECT  0.084 5.04 0.133 5.064 ;
     RECT  0.06 5.064 0.133 5.136 ;
     RECT  0.084 5.136 0.133 5.16 ;
     RECT  0.06 5.16 0.133 5.232 ;
     RECT  0.084 5.232 0.133 5.256 ;
     RECT  0.06 5.256 0.133 5.328 ;
     RECT  0.084 5.328 0.133 5.352 ;
     RECT  0.06 5.352 0.133 5.424 ;
     RECT  0.084 5.424 0.133 5.448 ;
     RECT  0.06 5.448 0.133 5.52 ;
     RECT  0.084 5.52 0.133 5.544 ;
     RECT  0.06 5.544 0.133 5.616 ;
     RECT  0.084 5.616 0.133 5.64 ;
     RECT  0.06 5.64 0.133 5.712 ;
     RECT  0.084 5.712 0.133 5.736 ;
     RECT  0.06 5.736 0.133 5.808 ;
     RECT  0.084 5.808 0.133 5.832 ;
     RECT  0.06 5.832 0.133 5.904 ;
     RECT  0.084 5.904 0.133 5.928 ;
     RECT  0.06 5.928 0.133 6 ;
     RECT  0.084 6 0.133 6.024 ;
     RECT  0.06 6.024 0.133 6.096 ;
     RECT  0.084 6.096 0.133 6.12 ;
     RECT  0.06 6.12 0.133 6.192 ;
     RECT  0.084 6.192 0.133 6.216 ;
     RECT  0.06 6.216 0.133 6.288 ;
     RECT  0.084 6.288 0.133 6.312 ;
     RECT  0.06 6.312 0.133 6.384 ;
     RECT  0.084 6.384 0.133 6.408 ;
     RECT  0.06 6.408 0.133 6.48 ;
     RECT  0.084 6.48 0.133 6.504 ;
     RECT  0.06 6.504 0.133 6.576 ;
     RECT  0.084 6.576 0.133 6.6 ;
     RECT  0.06 6.6 0.133 6.672 ;
     RECT  0.084 6.672 0.133 6.696 ;
     RECT  0.06 6.696 0.133 6.768 ;
     RECT  0.084 6.768 0.133 6.792 ;
     RECT  0.06 6.792 0.133 6.864 ;
     RECT  0.084 6.864 0.133 6.888 ;
     RECT  0.06 6.888 0.133 6.96 ;
     RECT  0.084 6.96 0.133 6.984 ;
     RECT  0.06 6.984 0.133 7.056 ;
     RECT  0.084 7.056 0.133 7.08 ;
     RECT  0.06 7.08 0.133 7.152 ;
     RECT  0.084 7.152 0.133 7.176 ;
     RECT  0.06 7.176 0.133 7.248 ;
     RECT  0.084 7.248 0.133 7.272 ;
     RECT  0.06 7.272 0.133 7.344 ;
     RECT  0.084 7.344 0.133 7.368 ;
     RECT  0.06 7.368 0.133 7.44 ;
     RECT  0.084 7.44 0.133 7.464 ;
     RECT  0.06 7.464 0.133 7.536 ;
     RECT  0.084 7.536 0.133 7.56 ;
     RECT  0.06 7.56 0.133 7.632 ;
     RECT  0.084 7.632 0.133 7.656 ;
     RECT  0.06 7.656 0.133 7.728 ;
     RECT  0.084 7.728 0.133 7.752 ;
     RECT  0.06 7.752 0.133 7.824 ;
     RECT  0.084 7.824 0.133 7.848 ;
     RECT  0.06 7.848 0.133 7.92 ;
     RECT  0.084 7.92 0.133 7.944 ;
     RECT  0.06 7.944 0.133 8.016 ;
     RECT  0.084 8.016 0.133 8.04 ;
     RECT  0.06 8.04 0.133 8.112 ;
     RECT  0.084 8.112 0.133 8.136 ;
     RECT  0.06 8.136 0.133 8.208 ;
     RECT  0.084 8.208 0.133 8.232 ;
     RECT  0.06 8.232 0.133 8.304 ;
     RECT  0.084 8.304 0.133 8.328 ;
     RECT  0.06 8.328 0.133 8.4 ;
     RECT  0.084 8.4 0.133 8.424 ;
     RECT  0.06 8.424 0.133 8.496 ;
     RECT  0.084 8.496 0.133 8.52 ;
     RECT  0.06 8.52 0.133 8.592 ;
     RECT  0.084 8.592 0.133 8.616 ;
     RECT  0.06 8.616 0.133 8.688 ;
     RECT  0.084 8.688 0.133 8.712 ;
     RECT  0.06 8.712 0.133 8.784 ;
     RECT  0.084 8.784 0.133 8.808 ;
     RECT  0.06 8.808 0.133 8.88 ;
     RECT  0.084 8.88 0.133 8.904 ;
     RECT  0.06 8.904 0.133 8.976 ;
     RECT  0.084 8.976 0.133 9 ;
     RECT  0.06 9 0.133 9.072 ;
     RECT  0.084 9.072 0.133 9.096 ;
     RECT  0.06 9.096 0.133 9.168 ;
     RECT  0.084 9.168 0.133 9.192 ;
     RECT  0.06 9.192 0.133 9.264 ;
     RECT  0.084 9.264 0.133 9.288 ;
     RECT  0.06 9.288 0.133 9.36 ;
     RECT  0.084 9.36 0.133 9.384 ;
     RECT  0.06 9.384 0.133 9.456 ;
     RECT  0.084 9.456 0.133 9.48 ;
     RECT  0.06 9.48 0.133 9.552 ;
     RECT  0.084 9.552 0.133 9.576 ;
     RECT  0.06 9.576 0.133 9.648 ;
     RECT  0.084 9.648 0.133 9.672 ;
     RECT  0.06 9.672 0.133 9.744 ;
     RECT  0.084 9.744 0.133 9.768 ;
     RECT  0.06 9.768 0.133 9.84 ;
     RECT  0.084 9.84 0.133 9.864 ;
     RECT  0.06 9.864 0.133 9.936 ;
     RECT  0.084 9.936 0.133 9.96 ;
     RECT  0.06 9.96 0.133 10.032 ;
     RECT  0.084 10.032 0.133 10.056 ;
     RECT  0.06 10.056 0.133 10.128 ;
     RECT  0.084 10.128 0.133 10.152 ;
     RECT  0.06 10.152 0.133 10.224 ;
     RECT  0.084 10.224 0.133 10.248 ;
     RECT  0.06 10.248 0.133 10.32 ;
     RECT  0.084 10.32 0.133 10.344 ;
     RECT  0.06 10.344 0.133 10.416 ;
     RECT  0.084 10.416 0.133 10.44 ;
     RECT  0.06 10.44 0.133 10.512 ;
     RECT  0.084 10.512 0.133 10.536 ;
     RECT  0.06 10.536 0.133 10.608 ;
     RECT  0.084 10.608 0.133 10.632 ;
     RECT  0.06 10.632 0.133 10.704 ;
     RECT  0.084 10.704 0.133 10.728 ;
     RECT  0.06 10.728 0.133 10.8 ;
     RECT  0.084 10.8 0.133 10.824 ;
     RECT  0.06 10.824 0.133 10.896 ;
     RECT  0.084 10.896 0.133 10.92 ;
     RECT  0.06 10.92 0.133 10.992 ;
     RECT  0.084 10.992 0.133 11.016 ;
     RECT  0.06 11.016 0.133 11.088 ;
     RECT  0.084 11.088 0.133 11.112 ;
     RECT  0.06 11.112 0.133 11.184 ;
     RECT  0.084 11.184 0.133 11.208 ;
     RECT  0.06 11.208 0.133 11.28 ;
     RECT  0.084 11.28 0.133 11.304 ;
     RECT  0.06 11.304 0.133 11.376 ;
     RECT  0.084 11.376 0.133 11.4 ;
     RECT  0.06 11.4 0.133 11.472 ;
     RECT  0.084 11.472 0.133 11.496 ;
     RECT  0.06 11.496 0.133 11.568 ;
     RECT  0.084 11.568 0.133 11.592 ;
     RECT  0.06 11.592 0.133 11.664 ;
     RECT  0.084 11.664 0.133 11.688 ;
     RECT  0.06 11.688 0.133 11.76 ;
     RECT  0.084 11.76 0.133 11.784 ;
     RECT  0.06 11.784 0.133 11.856 ;
     RECT  0.084 11.856 0.133 11.88 ;
     RECT  0.06 11.88 0.133 11.952 ;
     RECT  0.084 11.952 0.133 11.976 ;
     RECT  0.06 11.976 0.133 12.048 ;
     RECT  0.084 12.048 0.133 12.072 ;
     RECT  0.06 12.072 0.133 12.144 ;
     RECT  0.084 12.144 0.133 12.168 ;
     RECT  0.06 12.168 0.133 12.24 ;
     RECT  0.084 12.24 0.133 12.264 ;
     RECT  0.06 12.264 0.133 12.336 ;
     RECT  0.084 12.336 0.133 12.36 ;
     RECT  0.06 12.36 0.133 12.432 ;
     RECT  0.084 12.432 0.133 12.456 ;
     RECT  0.06 12.456 0.133 12.528 ;
     RECT  0.084 12.528 0.133 12.552 ;
     RECT  0.06 12.552 0.133 12.624 ;
     RECT  0.084 12.624 0.133 12.648 ;
     RECT  0.06 12.648 0.133 12.72 ;
     RECT  0.084 12.72 0.133 12.744 ;
     RECT  0.06 12.744 0.133 12.816 ;
     RECT  0.084 12.816 0.133 12.84 ;
     RECT  0.06 12.84 0.133 12.912 ;
     RECT  0.084 12.912 0.133 12.936 ;
     RECT  0.06 12.936 0.133 13.008 ;
     RECT  0.084 13.008 0.133 13.032 ;
     RECT  0.06 13.032 0.133 13.104 ;
     RECT  0.084 13.104 0.133 13.128 ;
     RECT  0.06 13.128 0.133 13.2 ;
     RECT  0.084 13.2 0.133 13.224 ;
     RECT  0.06 13.224 0.133 13.296 ;
     RECT  0.084 13.296 0.133 13.32 ;
     RECT  0.06 13.32 0.133 13.392 ;
     RECT  0.084 13.392 0.133 13.416 ;
     RECT  0.06 13.416 0.133 13.488 ;
     RECT  0.084 13.488 0.133 13.512 ;
     RECT  0.06 13.512 0.133 13.584 ;
     RECT  0.084 13.584 0.133 13.608 ;
     RECT  0.06 13.608 0.133 13.68 ;
     RECT  0.084 13.68 0.133 13.704 ;
     RECT  0.06 13.704 0.133 13.776 ;
     RECT  0.084 13.776 0.133 13.8 ;
     RECT  0.06 13.8 0.133 13.872 ;
     RECT  0.084 13.872 0.133 13.896 ;
     RECT  0.06 13.896 0.133 13.968 ;
     RECT  0.084 13.968 0.133 13.992 ;
     RECT  0.06 13.992 0.133 14.064 ;
     RECT  0.084 14.064 0.133 14.088 ;
     RECT  0.06 14.088 0.133 14.16 ;
     RECT  0.084 14.16 0.133 14.184 ;
     RECT  0.06 14.184 0.133 14.256 ;
     RECT  0.084 14.256 0.133 14.28 ;
     RECT  0.06 14.28 0.133 14.352 ;
     RECT  0.084 14.352 0.133 14.376 ;
     RECT  0.06 14.376 0.133 14.448 ;
     RECT  0.084 14.448 0.133 14.472 ;
     RECT  0.06 14.472 0.133 14.544 ;
     RECT  0.084 14.544 0.133 14.568 ;
     RECT  0.06 14.568 0.133 15.408 ;
     RECT  0.084 15.408 0.133 15.432 ;
     RECT  0.06 15.432 0.133 15.504 ;
     RECT  0.084 15.504 0.133 15.528 ;
     RECT  0.06 15.528 0.133 15.6 ;
     RECT  0.084 15.6 0.133 15.624 ;
     RECT  0.06 15.624 0.133 15.696 ;
     RECT  0.084 15.696 0.133 15.72 ;
     RECT  0.06 15.72 0.133 15.792 ;
     RECT  0.084 15.792 0.133 15.816 ;
     RECT  0.06 15.816 0.133 15.888 ;
     RECT  0.084 15.888 0.133 15.912 ;
     RECT  0.06 15.912 0.133 15.984 ;
     RECT  0.084 15.984 0.133 16.008 ;
     RECT  0.06 16.008 0.133 16.08 ;
     RECT  0.084 16.08 0.133 16.104 ;
     RECT  0.06 16.104 0.133 16.176 ;
     RECT  0.084 16.176 0.133 16.2 ;
     RECT  0.06 16.2 0.133 16.272 ;
     RECT  0.084 16.272 0.133 16.296 ;
     RECT  0.06 16.296 0.133 16.368 ;
     RECT  0.084 16.368 0.133 16.392 ;
     RECT  0.06 16.392 0.133 16.464 ;
     RECT  0.084 16.464 0.133 16.488 ;
     RECT  0.06 16.488 0.133 16.56 ;
     RECT  0.084 16.56 0.133 16.584 ;
     RECT  0.06 16.584 0.133 16.656 ;
     RECT  0.084 16.656 0.133 16.68 ;
     RECT  0.06 16.68 0.133 16.752 ;
     RECT  0.084 16.752 0.133 16.776 ;
     RECT  0.06 16.776 0.133 16.848 ;
     RECT  0.084 16.848 0.133 16.872 ;
     RECT  0.06 16.872 0.133 16.944 ;
     RECT  0.084 16.944 0.133 16.968 ;
     RECT  0.06 16.968 0.133 17.04 ;
     RECT  0.084 17.04 0.133 17.064 ;
     RECT  0.06 17.064 0.133 17.136 ;
     RECT  0.084 17.136 0.133 17.16 ;
     RECT  0.06 17.16 0.133 17.232 ;
     RECT  0.084 17.232 0.133 17.256 ;
     RECT  0.06 17.256 0.133 17.328 ;
     RECT  0.084 17.328 0.133 17.352 ;
     RECT  0.06 17.352 0.133 17.424 ;
     RECT  0.084 17.424 0.133 17.448 ;
     RECT  0.06 17.448 0.133 17.52 ;
     RECT  0.084 17.52 0.133 17.544 ;
     RECT  0.06 17.544 0.133 17.616 ;
     RECT  0.084 17.616 0.133 17.64 ;
     RECT  0.06 17.64 0.133 17.712 ;
     RECT  0.084 17.712 0.133 17.736 ;
     RECT  0.06 17.736 0.133 17.808 ;
     RECT  0.084 17.808 0.133 17.832 ;
     RECT  0.06 17.832 0.133 17.904 ;
     RECT  0.084 17.904 0.133 17.928 ;
     RECT  0.06 17.928 0.133 18 ;
     RECT  0.084 18 0.133 18.024 ;
     RECT  0.06 18.024 0.133 18.096 ;
     RECT  0.084 18.096 0.133 18.12 ;
     RECT  0.06 18.12 0.133 18.192 ;
     RECT  0.084 18.192 0.133 18.216 ;
     RECT  0.06 18.216 0.133 18.288 ;
     RECT  0.084 18.288 0.133 18.312 ;
     RECT  0.06 18.312 0.133 18.384 ;
     RECT  0.084 18.384 0.133 18.408 ;
     RECT  0.06 18.408 0.133 18.48 ;
     RECT  0.084 18.48 0.133 18.504 ;
     RECT  0.06 18.504 0.133 18.576 ;
     RECT  0.084 18.576 0.133 18.6 ;
     RECT  0.06 18.6 0.133 18.672 ;
     RECT  0.084 18.672 0.133 18.696 ;
     RECT  0.06 18.696 0.133 18.768 ;
     RECT  0.084 18.768 0.133 18.792 ;
     RECT  0.06 18.792 0.133 18.864 ;
     RECT  0.084 18.864 0.133 18.888 ;
     RECT  0.06 18.888 0.133 18.96 ;
     RECT  0.084 18.96 0.133 18.984 ;
     RECT  0.06 18.984 0.133 19.056 ;
     RECT  0.084 19.056 0.133 19.08 ;
     RECT  0.06 19.08 0.133 19.152 ;
     RECT  0.084 19.152 0.133 19.176 ;
     RECT  0.06 19.176 0.133 19.248 ;
     RECT  0.084 19.248 0.133 19.272 ;
     RECT  0.06 19.272 0.133 19.344 ;
     RECT  0.084 19.344 0.133 19.368 ;
     RECT  0.06 19.368 0.133 19.44 ;
     RECT  0.084 19.44 0.133 19.464 ;
     RECT  0.06 19.464 0.133 19.536 ;
     RECT  0.084 19.536 0.133 19.56 ;
     RECT  0.06 19.56 0.133 19.632 ;
     RECT  0.084 19.632 0.133 19.656 ;
     RECT  0.06 19.656 0.133 19.728 ;
     RECT  0.084 19.728 0.133 19.752 ;
     RECT  0.06 19.752 0.133 19.824 ;
     RECT  0.084 19.824 0.133 19.848 ;
     RECT  0.06 19.848 0.133 19.92 ;
     RECT  0.084 19.92 0.133 19.944 ;
     RECT  0.06 19.944 0.133 20.016 ;
     RECT  0.084 20.016 0.133 20.04 ;
     RECT  0.06 20.04 0.133 20.112 ;
     RECT  0.084 20.112 0.133 20.136 ;
     RECT  0.06 20.136 0.133 20.208 ;
     RECT  0.084 20.208 0.133 20.232 ;
     RECT  0.06 20.232 0.133 20.304 ;
     RECT  0.084 20.304 0.133 20.328 ;
     RECT  0.06 20.328 0.133 20.4 ;
     RECT  0.084 20.4 0.133 20.424 ;
     RECT  0.06 20.424 0.133 20.496 ;
     RECT  0.084 20.496 0.133 20.52 ;
     RECT  0.06 20.52 0.133 20.592 ;
     RECT  0.084 20.592 0.133 20.616 ;
     RECT  0.06 20.616 0.133 20.688 ;
     RECT  0.084 20.688 0.133 20.712 ;
     RECT  0.06 20.712 0.133 20.784 ;
     RECT  0.084 20.784 0.133 20.808 ;
     RECT  0.06 20.808 0.133 20.88 ;
     RECT  0.084 20.88 0.133 20.904 ;
     RECT  0.06 20.904 0.133 20.976 ;
     RECT  0.084 20.976 0.133 21 ;
     RECT  0.06 21 0.133 21.072 ;
     RECT  0.084 21.072 0.133 21.096 ;
     RECT  0.06 21.096 0.133 21.168 ;
     RECT  0.084 21.168 0.133 21.192 ;
     RECT  0.06 21.192 0.133 21.264 ;
     RECT  0.084 21.264 0.133 21.288 ;
     RECT  0.06 21.288 0.133 21.36 ;
     RECT  0.084 21.36 0.133 21.384 ;
     RECT  0.06 21.384 0.133 21.456 ;
     RECT  0.084 21.456 0.133 21.48 ;
     RECT  0.06 21.48 0.133 21.552 ;
     RECT  0.084 21.552 0.133 21.576 ;
     RECT  0.06 21.576 0.133 21.648 ;
     RECT  0.084 21.648 0.133 21.672 ;
     RECT  0.06 21.672 0.133 21.744 ;
     RECT  0.084 21.744 0.133 21.768 ;
     RECT  0.06 21.768 0.133 21.84 ;
     RECT  0.084 21.84 0.133 21.864 ;
     RECT  0.06 21.864 0.133 21.936 ;
     RECT  0.084 21.936 0.133 21.96 ;
     RECT  0.06 21.96 0.133 22.032 ;
     RECT  0.084 22.032 0.133 22.056 ;
     RECT  0.06 22.056 0.133 22.128 ;
     RECT  0.084 22.128 0.133 22.152 ;
     RECT  0.06 22.152 0.133 22.224 ;
     RECT  0.084 22.224 0.133 22.248 ;
     RECT  0.06 22.248 0.133 22.32 ;
     RECT  0.084 22.32 0.133 22.344 ;
     RECT  0.06 22.344 0.133 22.416 ;
     RECT  0.084 22.416 0.133 22.44 ;
     RECT  0.06 22.44 0.133 22.512 ;
     RECT  0.084 22.512 0.133 22.536 ;
     RECT  0.06 22.536 0.133 22.608 ;
     RECT  0.084 22.608 0.133 22.632 ;
     RECT  0.06 22.632 0.133 22.704 ;
     RECT  0.084 22.704 0.133 22.728 ;
     RECT  0.06 22.728 0.133 22.8 ;
     RECT  0.084 22.8 0.133 22.824 ;
     RECT  0.06 22.824 0.133 22.896 ;
     RECT  0.084 22.896 0.133 22.92 ;
     RECT  0.06 22.92 0.133 22.992 ;
     RECT  0.084 22.992 0.133 23.016 ;
     RECT  0.06 23.016 0.133 23.088 ;
     RECT  0.084 23.088 0.133 23.112 ;
     RECT  0.06 23.112 0.133 23.184 ;
     RECT  0.084 23.184 0.133 23.208 ;
     RECT  0.06 23.208 0.133 23.28 ;
     RECT  0.084 23.28 0.133 23.304 ;
     RECT  0.06 23.304 0.133 23.376 ;
     RECT  0.084 23.376 0.133 23.4 ;
     RECT  0.06 23.4 0.133 23.472 ;
     RECT  0.084 23.472 0.133 23.496 ;
     RECT  0.06 23.496 0.133 23.568 ;
     RECT  0.084 23.568 0.133 23.592 ;
     RECT  0.06 23.592 0.133 23.664 ;
     RECT  0.084 23.664 0.133 23.688 ;
     RECT  0.06 23.688 0.133 23.76 ;
     RECT  0.084 23.76 0.133 23.784 ;
     RECT  0.06 23.784 0.133 23.856 ;
     RECT  0.084 23.856 0.133 23.88 ;
     RECT  0.06 23.88 0.133 23.952 ;
     RECT  0.084 23.952 0.133 23.976 ;
     RECT  0.06 23.976 0.133 24.048 ;
     RECT  0.084 24.048 0.133 24.072 ;
     RECT  0.06 24.072 0.133 24.144 ;
     RECT  0.084 24.144 0.133 24.168 ;
     RECT  0.06 24.168 0.133 24.24 ;
     RECT  0.084 24.24 0.133 24.264 ;
     RECT  0.06 24.264 0.133 24.336 ;
     RECT  0.084 24.336 0.133 24.36 ;
     RECT  0.06 24.36 0.133 24.432 ;
     RECT  0.084 24.432 0.133 24.456 ;
     RECT  0.06 24.456 0.133 24.528 ;
     RECT  0.084 24.528 0.133 24.552 ;
     RECT  0.06 24.552 0.133 24.624 ;
     RECT  0.084 24.624 0.133 24.648 ;
     RECT  0.06 24.648 0.133 24.72 ;
     RECT  0.084 24.72 0.133 24.744 ;
     RECT  0.06 24.744 0.133 24.816 ;
     RECT  0.084 24.816 0.133 24.84 ;
     RECT  0.06 24.84 0.133 24.912 ;
     RECT  0.084 24.912 0.133 24.936 ;
     RECT  0.06 24.936 0.133 25.008 ;
     RECT  0.084 25.008 0.133 25.032 ;
     RECT  0.06 25.032 0.133 25.104 ;
     RECT  0.084 25.104 0.133 25.128 ;
     RECT  0.06 25.128 0.133 25.2 ;
     RECT  0.084 25.2 0.133 25.224 ;
     RECT  0.06 25.224 0.133 25.296 ;
     RECT  0.084 25.296 0.133 25.32 ;
     RECT  0.06 25.32 0.133 25.392 ;
     RECT  0.084 25.392 0.133 25.416 ;
     RECT  0.06 25.416 0.133 25.488 ;
     RECT  0.084 25.488 0.133 25.512 ;
     RECT  0.06 25.512 0.133 25.584 ;
     RECT  0.084 25.584 0.133 25.608 ;
     RECT  0.06 25.608 0.133 25.68 ;
     RECT  0.084 25.68 0.133 25.704 ;
     RECT  0.06 25.704 0.133 25.776 ;
     RECT  0.084 25.776 0.133 25.8 ;
     RECT  0.06 25.8 0.133 25.872 ;
     RECT  0.084 25.872 0.133 25.896 ;
     RECT  0.06 25.896 0.133 25.968 ;
     RECT  0.084 25.968 0.133 25.992 ;
     RECT  0.06 25.992 0.133 26.064 ;
     RECT  0.084 26.064 0.133 26.088 ;
     RECT  0.06 26.088 0.133 26.16 ;
     RECT  0.084 26.16 0.133 26.184 ;
     RECT  0.06 26.184 0.133 26.256 ;
     RECT  0.084 26.256 0.133 26.28 ;
     RECT  0.06 26.28 0.133 26.352 ;
     RECT  0.084 26.352 0.133 26.376 ;
     RECT  0.06 26.376 0.133 26.448 ;
     RECT  0.084 26.448 0.133 26.472 ;
     RECT  0.06 26.472 0.133 26.544 ;
     RECT  0.084 26.544 0.133 26.568 ;
     RECT  0.06 26.568 0.133 26.64 ;
     RECT  0.084 26.64 0.133 26.664 ;
     RECT  0.06 26.664 0.133 26.736 ;
     RECT  0.084 26.736 0.133 26.76 ;
     RECT  0.06 26.76 0.133 26.832 ;
     RECT  0.084 26.832 0.133 26.856 ;
     RECT  0.06 26.856 0.133 26.928 ;
     RECT  0.084 26.928 0.133 26.952 ;
     RECT  0.06 26.952 0.133 27.024 ;
     RECT  0.084 27.024 0.133 27.048 ;
     RECT  0.06 27.048 0.133 27.12 ;
     RECT  0.084 27.12 0.133 27.144 ;
     RECT  0.06 27.144 0.133 27.216 ;
     RECT  0.084 27.216 0.133 27.24 ;
     RECT  0.06 27.24 0.133 27.312 ;
     RECT  0.084 27.312 0.133 27.336 ;
     RECT  0.06 27.336 0.133 27.408 ;
     RECT  0.084 27.408 0.133 27.432 ;
     RECT  0.06 27.432 0.133 27.504 ;
     RECT  0.084 27.504 0.133 27.528 ;
     RECT  0.06 27.528 0.133 27.6 ;
     RECT  0.084 27.6 0.133 27.624 ;
     RECT  0.06 27.624 0.133 27.696 ;
     RECT  0.084 27.696 0.133 27.72 ;
     RECT  0.06 27.72 0.133 27.792 ;
     RECT  0.084 27.792 0.133 27.816 ;
     RECT  0.06 27.816 0.133 27.888 ;
     RECT  0.084 27.888 0.133 27.912 ;
     RECT  0.06 27.912 0.133 27.984 ;
     RECT  0.084 27.984 0.133 28.008 ;
     RECT  0.06 28.008 0.133 28.08 ;
     RECT  0.084 28.08 0.133 28.104 ;
     RECT  0.06 28.104 0.133 28.176 ;
     RECT  0.084 28.176 0.133 28.2 ;
     RECT  0.06 28.2 0.133 28.272 ;
     RECT  0.084 28.272 0.133 28.296 ;
     RECT  0.06 28.296 0.133 28.368 ;
     RECT  0.084 28.368 0.133 28.392 ;
     RECT  0.06 28.392 0.133 28.464 ;
     RECT  0.084 28.464 0.133 28.488 ;
     RECT  0.06 28.488 0.133 28.56 ;
     RECT  0.084 28.56 0.133 28.584 ;
     RECT  0.06 28.584 0.133 28.656 ;
     RECT  0.084 28.656 0.133 28.68 ;
     RECT  0.06 28.68 0.133 28.752 ;
     RECT  0.084 28.752 0.133 28.776 ;
     RECT  0.06 28.776 0.133 28.848 ;
     RECT  0.084 28.848 0.133 28.872 ;
     RECT  0.06 28.872 0.133 28.944 ;
     RECT  0.084 28.944 0.133 28.968 ;
     RECT  0.06 28.968 0.133 29.04 ;
     RECT  0.084 29.04 0.133 29.064 ;
     RECT  0.06 29.064 0.133 29.136 ;
     RECT  0.084 29.136 0.133 29.16 ;
     RECT  0.06 29.16 0.133 29.232 ;
     RECT  0.084 29.232 0.133 29.256 ;
     RECT  0.06 29.256 0.133 29.328 ;
     RECT  0.084 29.328 0.133 29.352 ;
     RECT  0.06 29.352 0.133 29.424 ;
     RECT  0.084 29.424 0.133 29.448 ;
     RECT  0.06 29.448 0.133 29.52 ;
     RECT  0.084 29.52 0.133 29.544 ;
     RECT  0.06 29.544 0.133 29.616 ;
     RECT  0.084 29.616 0.133 29.64 ;
     RECT  0.06 29.64 0.133 29.712 ;
     RECT  0.084 29.712 0.133 29.736 ;
     RECT  0.06 29.736 0.133 29.808 ;
     RECT  0.084 29.808 0.133 29.832 ;
     RECT  0.06 29.832 0.133 29.904 ;
     RECT  0.084 29.904 0.133 29.928 ;
     RECT  0.06 29.928 0.133 30 ;
     RECT  0.084 30 0.133 30.024 ;
     RECT  0.06 30.024 0.133 30.096 ;
     RECT  0.084 30.096 0.133 30.12 ;
     RECT  0.06 30.12 0.133 30.192 ;
     RECT  0.084 30.192 0.133 30.216 ;
     RECT  0.06 30.216 0.133 30.288 ;
     RECT  0.084 30.288 0.133 30.312 ;
     RECT  0.06 30.312 0.133 30.384 ;
     RECT  0.084 30.384 0.133 30.408 ;
     RECT  0.06 30.408 0.133 30.48 ;
     RECT  0.084 30.48 0.133 30.504 ;
     RECT  0.06 30.504 0.133 30.576 ;
     RECT  0.084 30.576 0.133 30.6 ;
     RECT  0.06 30.6 0.133 30.672 ;
     RECT  0.084 30.672 0.133 30.696 ;
     RECT  0.06 30.696 0.133 30.768 ;
     RECT  0.084 30.768 0.133 30.792 ;
     RECT  0.06 30.792 0.133 30.864 ;
     RECT  0.084 30.864 0.133 30.888 ;
     RECT  0.06 30.888 0.133 30.96 ;
     RECT  0.084 30.96 0.133 30.984 ;
     RECT  0.06 30.984 0.133 31.056 ;
     RECT  0.084 31.056 0.133 31.08 ;
     RECT  0.06 31.08 0.133 31.152 ;
     RECT  0.084 31.152 0.133 31.176 ;
     RECT  0.06 31.176 0.133 31.248 ;
     RECT  0.084 31.248 0.133 31.272 ;
     RECT  0.06 31.272 0.133 31.344 ;
     RECT  0.084 31.344 0.133 31.368 ;
     RECT  0.06 31.368 0.133 31.44 ;
     RECT  0.084 31.44 0.133 31.464 ;
     RECT  0.06 31.464 0.133 31.536 ;
     RECT  0.084 31.536 0.133 31.56 ;
     RECT  0.06 31.56 0.133 31.632 ;
     RECT  0.084 31.632 0.133 31.656 ;
     RECT  0.06 31.656 0.133 31.728 ;
     RECT  0.084 31.728 0.133 31.752 ;
     RECT  0.06 31.752 0.133 31.824 ;
     RECT  0.084 31.824 0.133 31.848 ;
     RECT  0.06 31.848 0.133 31.92 ;
     RECT  0.084 31.92 0.133 31.944 ;
     RECT  0.06 31.944 0.133 32.016 ;
     RECT  0.084 32.016 0.133 32.04 ;
     RECT  0.06 32.04 0.133 32.112 ;
     RECT  0.084 32.112 0.133 32.136 ;
     RECT  0.06 32.136 0.133 32.208 ;
     RECT  0.084 32.208 0.133 32.232 ;
     RECT  0.06 32.232 0.133 32.304 ;
     RECT  0.084 32.304 0.133 32.328 ;
     RECT  0.06 32.328 0.133 32.4 ;
     RECT  0.084 32.4 0.133 32.424 ;
     RECT  0.06 32.424 0.133 32.496 ;
     RECT  0.084 32.496 0.133 32.52 ;
     RECT  0.06 32.52 0.133 32.592 ;
     RECT  0.084 32.592 0.133 32.616 ;
     RECT  0.06 32.616 0.133 32.688 ;
     RECT  0.084 32.688 0.133 32.712 ;
     RECT  0.06 32.712 0.133 32.784 ;
     RECT  0.084 32.784 0.133 32.808 ;
     RECT  0.06 32.808 0.133 32.88 ;
     RECT  0.084 32.88 0.133 32.904 ;
     RECT  0.06 32.904 0.133 32.976 ;
     RECT  0.084 32.976 0.133 33 ;
     RECT  0.06 33 0.133 33.072 ;
     RECT  0.084 33.072 0.133 33.096 ;
     RECT  0.06 33.096 0.133 33.168 ;
     RECT  0.084 33.168 0.133 33.192 ;
     RECT  0.06 33.192 0.133 33.264 ;
     RECT  0.084 33.264 0.133 33.288 ;
     RECT  0.06 33.288 0.133 33.36 ;
     RECT  0.084 33.36 0.133 33.384 ;
     RECT  0.06 33.384 0.133 33.456 ;
     RECT  0.084 33.456 0.133 33.48 ;
     RECT  0.06 33.48 0.133 33.552 ;
     RECT  0.084 33.552 0.133 33.576 ;
     RECT  0.06 33.576 0.133 33.648 ;
     RECT  0.084 33.648 0.133 33.672 ;
     RECT  0.06 33.672 0.133 33.744 ;
     RECT  0.084 33.744 0.133 33.768 ;
     RECT  0.133 3.36 0.181 33.768 ;
     RECT  0.181 2.784 0.421 33.768 ;
     RECT  0.421 2.496 2.293 33.768 ;
     RECT  2.293 2.352 2.408 33.768 ;
     RECT  2.408 2.148 2.512 33.768 ;
     RECT  2.512 2.352 2.585 33.768 ;
     RECT  2.585 2.418 2.704 33.768 ;
     RECT  2.704 2.496 3.125 33.768 ;
     RECT  3.125 2.736 3.557 33.768 ;
     RECT  3.557 2.736 3.593 33.096 ;
     RECT  3.593 3.024 3.845 33.096 ;
     RECT  3.845 3.024 5.108 32.472 ;
     RECT  5.108 2.148 5.212 32.472 ;
     RECT  5.212 2.418 6.217 32.472 ;
     RECT  6.217 2.016 7.733 32.472 ;
     RECT  7.733 2.016 7.765 32.412 ;
     RECT  7.765 1.968 7.912 32.412 ;
     RECT  7.912 1.968 9.245 32.328 ;
     RECT  9.245 1.968 9.601 32.232 ;
     RECT  9.601 1.92 9.637 32.232 ;
     RECT  9.637 1.488 10.508 32.232 ;
     RECT  10.508 1.488 10.612 32.412 ;
     RECT  10.612 1.488 11.257 32.232 ;
     RECT  11.257 1.2 11.329 32.232 ;
     RECT  11.329 0.816 12.445 32.232 ;
     RECT  12.445 0.096 12.947 32.232 ;
     RECT  12.947 0.816 13.093 32.232 ;
     RECT  13.093 0.816 13.208 32.328 ;
     RECT  13.208 0.816 13.312 32.412 ;
     RECT  13.312 0.816 15.908 32.328 ;
     RECT  15.908 0.816 16.012 32.412 ;
     RECT  16.012 0.816 17.129 32.328 ;
     RECT  17.129 0.816 18.608 31.944 ;
     RECT  18.608 0.816 18.712 32.412 ;
     RECT  18.712 0.816 18.904 32.142 ;
     RECT  18.904 0.816 19.325 31.8 ;
     RECT  19.325 0.816 19.897 30.696 ;
     RECT  19.897 0.72 21.409 30.696 ;
     RECT  21.409 0.72 21.491 30.792 ;
     RECT  21.491 0.72 21.516 0.744 ;
     RECT  21.491 0.744 21.564 0.816 ;
     RECT  21.491 0.816 21.516 0.84 ;
     RECT  21.491 0.84 21.564 0.912 ;
     RECT  21.491 0.912 21.516 0.936 ;
     RECT  21.491 0.936 21.564 1.008 ;
     RECT  21.491 1.008 21.516 1.032 ;
     RECT  21.491 1.032 21.564 1.104 ;
     RECT  21.491 1.104 21.516 1.128 ;
     RECT  21.491 1.128 21.564 1.2 ;
     RECT  21.491 1.2 21.516 1.224 ;
     RECT  21.491 1.224 21.564 1.296 ;
     RECT  21.491 1.296 21.516 1.32 ;
     RECT  21.491 1.32 21.564 1.392 ;
     RECT  21.491 1.392 21.516 1.416 ;
     RECT  21.491 1.416 21.564 1.488 ;
     RECT  21.491 1.488 21.516 1.512 ;
     RECT  21.491 1.512 21.564 1.584 ;
     RECT  21.491 1.584 21.516 1.608 ;
     RECT  21.491 1.608 21.564 1.68 ;
     RECT  21.491 1.68 21.516 1.704 ;
     RECT  21.491 1.704 21.564 1.776 ;
     RECT  21.491 1.776 21.516 1.8 ;
     RECT  21.491 1.8 21.564 1.872 ;
     RECT  21.491 1.872 21.516 1.896 ;
     RECT  21.491 1.896 21.564 1.968 ;
     RECT  21.491 1.968 21.516 1.992 ;
     RECT  21.491 1.992 21.564 2.064 ;
     RECT  21.491 2.064 21.516 2.088 ;
     RECT  21.491 2.088 21.564 2.16 ;
     RECT  21.491 2.16 21.516 2.184 ;
     RECT  21.491 2.184 21.564 2.256 ;
     RECT  21.491 2.256 21.516 2.28 ;
     RECT  21.491 2.28 21.564 2.352 ;
     RECT  21.491 2.352 21.516 2.376 ;
     RECT  21.491 2.376 21.564 2.448 ;
     RECT  21.491 2.448 21.516 2.472 ;
     RECT  21.491 2.472 21.564 2.544 ;
     RECT  21.491 2.544 21.516 2.568 ;
     RECT  21.491 2.568 21.564 2.64 ;
     RECT  21.491 2.64 21.516 2.664 ;
     RECT  21.491 2.664 21.564 2.736 ;
     RECT  21.491 2.736 21.516 2.76 ;
     RECT  21.491 2.76 21.564 2.832 ;
     RECT  21.491 2.832 21.516 2.856 ;
     RECT  21.491 2.856 21.564 2.928 ;
     RECT  21.491 2.928 21.516 2.952 ;
     RECT  21.491 2.952 21.564 3.024 ;
     RECT  21.491 3.024 21.516 3.048 ;
     RECT  21.491 3.048 21.564 3.12 ;
     RECT  21.491 3.12 21.516 3.144 ;
     RECT  21.491 3.144 21.564 3.216 ;
     RECT  21.491 3.216 21.516 3.24 ;
     RECT  21.491 3.24 21.564 3.312 ;
     RECT  21.491 3.312 21.516 3.336 ;
     RECT  21.491 3.336 21.564 3.408 ;
     RECT  21.491 3.408 21.516 3.432 ;
     RECT  21.491 3.432 21.564 3.504 ;
     RECT  21.491 3.504 21.516 3.528 ;
     RECT  21.491 3.528 21.564 3.6 ;
     RECT  21.491 3.6 21.516 3.624 ;
     RECT  21.491 3.624 21.564 3.696 ;
     RECT  21.491 3.696 21.516 3.72 ;
     RECT  21.491 3.72 21.564 3.792 ;
     RECT  21.491 3.792 21.516 3.816 ;
     RECT  21.491 3.816 21.564 3.888 ;
     RECT  21.491 3.888 21.516 3.912 ;
     RECT  21.491 3.912 21.564 3.984 ;
     RECT  21.491 3.984 21.516 4.008 ;
     RECT  21.491 4.008 21.564 4.08 ;
     RECT  21.491 4.08 21.516 4.104 ;
     RECT  21.491 4.104 21.564 4.176 ;
     RECT  21.491 4.176 21.516 4.2 ;
     RECT  21.491 4.2 21.564 4.272 ;
     RECT  21.491 4.272 21.516 4.296 ;
     RECT  21.491 4.296 21.564 4.368 ;
     RECT  21.491 4.368 21.516 4.392 ;
     RECT  21.491 4.392 21.564 4.464 ;
     RECT  21.491 4.464 21.516 4.488 ;
     RECT  21.491 4.488 21.564 4.56 ;
     RECT  21.491 4.56 21.516 4.584 ;
     RECT  21.491 4.584 21.564 4.656 ;
     RECT  21.491 4.656 21.516 4.68 ;
     RECT  21.491 4.68 21.564 4.752 ;
     RECT  21.491 4.752 21.516 4.776 ;
     RECT  21.491 4.776 21.564 4.848 ;
     RECT  21.491 4.848 21.516 4.872 ;
     RECT  21.491 4.872 21.564 4.944 ;
     RECT  21.491 4.944 21.516 4.968 ;
     RECT  21.491 4.968 21.564 5.04 ;
     RECT  21.491 5.04 21.516 5.064 ;
     RECT  21.491 5.064 21.564 5.136 ;
     RECT  21.491 5.136 21.516 5.16 ;
     RECT  21.491 5.16 21.564 5.232 ;
     RECT  21.491 5.232 21.516 5.256 ;
     RECT  21.491 5.256 21.564 5.328 ;
     RECT  21.491 5.328 21.516 5.352 ;
     RECT  21.491 5.352 21.564 5.424 ;
     RECT  21.491 5.424 21.516 5.448 ;
     RECT  21.491 5.448 21.564 5.52 ;
     RECT  21.491 5.52 21.516 5.544 ;
     RECT  21.491 5.544 21.564 5.616 ;
     RECT  21.491 5.616 21.516 5.64 ;
     RECT  21.491 5.64 21.564 5.712 ;
     RECT  21.491 5.712 21.516 5.736 ;
     RECT  21.491 5.736 21.564 5.808 ;
     RECT  21.491 5.808 21.516 5.832 ;
     RECT  21.491 5.832 21.564 5.904 ;
     RECT  21.491 5.904 21.516 5.928 ;
     RECT  21.491 5.928 21.564 6 ;
     RECT  21.491 6 21.516 6.024 ;
     RECT  21.491 6.024 21.564 6.096 ;
     RECT  21.491 6.096 21.516 6.12 ;
     RECT  21.491 6.12 21.564 6.192 ;
     RECT  21.491 6.192 21.516 6.216 ;
     RECT  21.491 6.216 21.564 6.288 ;
     RECT  21.491 6.288 21.516 6.312 ;
     RECT  21.491 6.312 21.564 6.384 ;
     RECT  21.491 6.384 21.516 6.408 ;
     RECT  21.491 6.408 21.564 6.48 ;
     RECT  21.491 6.48 21.516 6.504 ;
     RECT  21.491 6.504 21.564 6.576 ;
     RECT  21.491 6.576 21.516 6.6 ;
     RECT  21.491 6.6 21.564 6.672 ;
     RECT  21.491 6.672 21.516 6.696 ;
     RECT  21.491 6.696 21.564 6.768 ;
     RECT  21.491 6.768 21.516 6.792 ;
     RECT  21.491 6.792 21.564 6.864 ;
     RECT  21.491 6.864 21.516 6.888 ;
     RECT  21.491 6.888 21.564 6.96 ;
     RECT  21.491 6.96 21.516 6.984 ;
     RECT  21.491 6.984 21.564 7.056 ;
     RECT  21.491 7.056 21.516 7.08 ;
     RECT  21.491 7.08 21.564 7.152 ;
     RECT  21.491 7.152 21.516 7.176 ;
     RECT  21.491 7.176 21.564 7.248 ;
     RECT  21.491 7.248 21.516 7.272 ;
     RECT  21.491 7.272 21.564 7.344 ;
     RECT  21.491 7.344 21.516 7.368 ;
     RECT  21.491 7.368 21.564 7.44 ;
     RECT  21.491 7.44 21.516 7.464 ;
     RECT  21.491 7.464 21.564 7.536 ;
     RECT  21.491 7.536 21.516 7.56 ;
     RECT  21.491 7.56 21.564 7.632 ;
     RECT  21.491 7.632 21.516 7.656 ;
     RECT  21.491 7.656 21.564 7.728 ;
     RECT  21.491 7.728 21.516 7.752 ;
     RECT  21.491 7.752 21.564 7.824 ;
     RECT  21.491 7.824 21.516 7.848 ;
     RECT  21.491 7.848 21.564 7.92 ;
     RECT  21.491 7.92 21.516 7.944 ;
     RECT  21.491 7.944 21.564 8.016 ;
     RECT  21.491 8.016 21.516 8.04 ;
     RECT  21.491 8.04 21.564 8.112 ;
     RECT  21.491 8.112 21.516 8.136 ;
     RECT  21.491 8.136 21.564 8.208 ;
     RECT  21.491 8.208 21.516 8.232 ;
     RECT  21.491 8.232 21.564 8.304 ;
     RECT  21.491 8.304 21.516 8.328 ;
     RECT  21.491 8.328 21.564 8.4 ;
     RECT  21.491 8.4 21.516 8.424 ;
     RECT  21.491 8.424 21.564 8.496 ;
     RECT  21.491 8.496 21.516 8.52 ;
     RECT  21.491 8.52 21.564 8.592 ;
     RECT  21.491 8.592 21.516 8.616 ;
     RECT  21.491 8.616 21.564 8.688 ;
     RECT  21.491 8.688 21.516 8.712 ;
     RECT  21.491 8.712 21.564 8.784 ;
     RECT  21.491 8.784 21.516 8.808 ;
     RECT  21.491 8.808 21.564 8.88 ;
     RECT  21.491 8.88 21.516 8.904 ;
     RECT  21.491 8.904 21.564 8.976 ;
     RECT  21.491 8.976 21.516 9 ;
     RECT  21.491 9 21.564 9.072 ;
     RECT  21.491 9.072 21.516 9.096 ;
     RECT  21.491 9.096 21.564 9.168 ;
     RECT  21.491 9.168 21.516 9.192 ;
     RECT  21.491 9.192 21.564 9.264 ;
     RECT  21.491 9.264 21.516 9.288 ;
     RECT  21.491 9.288 21.564 9.36 ;
     RECT  21.491 9.36 21.516 9.384 ;
     RECT  21.491 9.384 21.564 9.456 ;
     RECT  21.491 9.456 21.516 9.48 ;
     RECT  21.491 9.48 21.564 9.552 ;
     RECT  21.491 9.552 21.516 9.576 ;
     RECT  21.491 9.576 21.564 9.648 ;
     RECT  21.491 9.648 21.516 9.672 ;
     RECT  21.491 9.672 21.564 9.744 ;
     RECT  21.491 9.744 21.516 9.768 ;
     RECT  21.491 9.768 21.564 9.84 ;
     RECT  21.491 9.84 21.516 9.864 ;
     RECT  21.491 9.864 21.564 9.936 ;
     RECT  21.491 9.936 21.516 9.96 ;
     RECT  21.491 9.96 21.564 10.032 ;
     RECT  21.491 10.032 21.516 10.056 ;
     RECT  21.491 10.056 21.564 10.128 ;
     RECT  21.491 10.128 21.516 10.152 ;
     RECT  21.491 10.152 21.564 10.224 ;
     RECT  21.491 10.224 21.516 10.248 ;
     RECT  21.491 10.248 21.564 10.32 ;
     RECT  21.491 10.32 21.516 10.344 ;
     RECT  21.491 10.344 21.564 10.416 ;
     RECT  21.491 10.416 21.516 10.44 ;
     RECT  21.491 10.44 21.564 10.512 ;
     RECT  21.491 10.512 21.516 10.536 ;
     RECT  21.491 10.536 21.564 10.608 ;
     RECT  21.491 10.608 21.516 10.632 ;
     RECT  21.491 10.632 21.564 10.704 ;
     RECT  21.491 10.704 21.516 10.728 ;
     RECT  21.491 10.728 21.564 10.8 ;
     RECT  21.491 10.8 21.516 10.824 ;
     RECT  21.491 10.824 21.564 10.896 ;
     RECT  21.491 10.896 21.516 10.92 ;
     RECT  21.491 10.92 21.564 10.992 ;
     RECT  21.491 10.992 21.516 11.016 ;
     RECT  21.491 11.016 21.564 11.088 ;
     RECT  21.491 11.088 21.516 11.112 ;
     RECT  21.491 11.112 21.564 11.184 ;
     RECT  21.491 11.184 21.516 11.208 ;
     RECT  21.491 11.208 21.564 11.28 ;
     RECT  21.491 11.28 21.516 11.304 ;
     RECT  21.491 11.304 21.564 11.376 ;
     RECT  21.491 11.376 21.516 11.4 ;
     RECT  21.491 11.4 21.564 11.472 ;
     RECT  21.491 11.472 21.516 11.496 ;
     RECT  21.491 11.496 21.564 11.568 ;
     RECT  21.491 11.568 21.516 11.592 ;
     RECT  21.491 11.592 21.564 11.664 ;
     RECT  21.491 11.664 21.516 11.688 ;
     RECT  21.491 11.688 21.564 11.76 ;
     RECT  21.491 11.76 21.516 11.784 ;
     RECT  21.491 11.784 21.564 11.856 ;
     RECT  21.491 11.856 21.516 11.88 ;
     RECT  21.491 11.88 21.564 11.952 ;
     RECT  21.491 11.952 21.516 11.976 ;
     RECT  21.491 11.976 21.564 12.048 ;
     RECT  21.491 12.048 21.516 12.072 ;
     RECT  21.491 12.072 21.564 12.144 ;
     RECT  21.491 12.144 21.516 12.168 ;
     RECT  21.491 12.168 21.564 12.24 ;
     RECT  21.491 12.24 21.516 12.264 ;
     RECT  21.491 12.264 21.564 12.336 ;
     RECT  21.491 12.336 21.516 12.36 ;
     RECT  21.491 12.36 21.564 12.432 ;
     RECT  21.491 12.432 21.516 12.456 ;
     RECT  21.491 12.456 21.564 12.528 ;
     RECT  21.491 12.528 21.516 12.552 ;
     RECT  21.491 12.552 21.564 12.624 ;
     RECT  21.491 12.624 21.516 12.648 ;
     RECT  21.491 12.648 21.564 12.72 ;
     RECT  21.491 12.72 21.516 12.744 ;
     RECT  21.491 12.744 21.564 12.816 ;
     RECT  21.491 12.816 21.516 12.84 ;
     RECT  21.491 12.84 21.564 12.912 ;
     RECT  21.491 12.912 21.516 12.936 ;
     RECT  21.491 12.936 21.564 13.008 ;
     RECT  21.491 13.008 21.516 13.032 ;
     RECT  21.491 13.032 21.564 13.104 ;
     RECT  21.491 13.104 21.516 13.128 ;
     RECT  21.491 13.128 21.564 13.2 ;
     RECT  21.491 13.2 21.516 13.224 ;
     RECT  21.491 13.224 21.564 13.296 ;
     RECT  21.491 13.296 21.516 13.32 ;
     RECT  21.491 13.32 21.564 13.392 ;
     RECT  21.491 13.392 21.516 13.416 ;
     RECT  21.491 13.416 21.564 13.488 ;
     RECT  21.491 13.488 21.516 13.512 ;
     RECT  21.491 13.512 21.564 13.584 ;
     RECT  21.491 13.584 21.516 13.608 ;
     RECT  21.491 13.608 21.564 13.68 ;
     RECT  21.491 13.68 21.516 13.704 ;
     RECT  21.491 13.704 21.564 13.776 ;
     RECT  21.491 13.776 21.516 13.8 ;
     RECT  21.491 13.8 21.564 13.872 ;
     RECT  21.491 13.872 21.516 13.896 ;
     RECT  21.491 13.896 21.564 13.968 ;
     RECT  21.491 13.968 21.516 13.992 ;
     RECT  21.491 13.992 21.564 14.064 ;
     RECT  21.491 14.064 21.516 14.088 ;
     RECT  21.491 14.088 21.564 14.16 ;
     RECT  21.491 14.16 21.516 14.184 ;
     RECT  21.491 14.184 21.564 14.256 ;
     RECT  21.491 14.256 21.516 14.28 ;
     RECT  21.491 14.28 21.564 14.352 ;
     RECT  21.491 14.352 21.516 14.376 ;
     RECT  21.491 14.376 21.564 14.448 ;
     RECT  21.491 14.448 21.516 14.472 ;
     RECT  21.491 14.472 21.564 14.544 ;
     RECT  21.491 14.544 21.516 14.568 ;
     RECT  21.491 14.568 21.564 14.64 ;
     RECT  21.491 14.64 21.516 14.664 ;
     RECT  21.491 14.664 21.564 14.736 ;
     RECT  21.491 14.736 21.516 14.76 ;
     RECT  21.491 14.76 21.564 14.832 ;
     RECT  21.491 14.832 21.516 14.856 ;
     RECT  21.491 14.856 21.564 14.928 ;
     RECT  21.491 14.928 21.516 14.952 ;
     RECT  21.491 14.952 21.564 15.024 ;
     RECT  21.491 15.024 21.516 15.048 ;
     RECT  21.491 15.048 21.564 15.12 ;
     RECT  21.491 15.12 21.516 15.144 ;
     RECT  21.491 15.144 21.564 15.216 ;
     RECT  21.491 15.216 21.516 15.24 ;
     RECT  21.491 15.24 21.564 15.312 ;
     RECT  21.491 15.312 21.516 15.336 ;
     RECT  21.491 15.336 21.564 15.408 ;
     RECT  21.491 15.408 21.516 15.432 ;
     RECT  21.491 15.432 21.564 15.504 ;
     RECT  21.491 15.504 21.516 15.528 ;
     RECT  21.491 15.528 21.564 15.6 ;
     RECT  21.491 15.6 21.516 15.624 ;
     RECT  21.491 15.624 21.564 15.696 ;
     RECT  21.491 15.696 21.516 15.72 ;
     RECT  21.491 15.72 21.564 15.792 ;
     RECT  21.491 15.792 21.516 15.816 ;
     RECT  21.491 15.816 21.564 15.888 ;
     RECT  21.491 15.888 21.516 15.912 ;
     RECT  21.491 15.912 21.564 15.984 ;
     RECT  21.491 15.984 21.516 16.008 ;
     RECT  21.491 16.008 21.564 16.08 ;
     RECT  21.491 16.08 21.516 16.104 ;
     RECT  21.491 16.104 21.564 16.176 ;
     RECT  21.491 16.176 21.516 16.2 ;
     RECT  21.491 16.2 21.564 16.272 ;
     RECT  21.491 16.272 21.516 16.296 ;
     RECT  21.491 16.296 21.564 16.368 ;
     RECT  21.491 16.368 21.516 16.392 ;
     RECT  21.491 16.392 21.564 16.464 ;
     RECT  21.491 16.464 21.516 16.488 ;
     RECT  21.491 16.488 21.564 16.56 ;
     RECT  21.491 16.56 21.516 16.584 ;
     RECT  21.491 16.584 21.564 16.656 ;
     RECT  21.491 16.656 21.516 16.68 ;
     RECT  21.491 16.68 21.564 16.752 ;
     RECT  21.491 16.752 21.516 16.776 ;
     RECT  21.491 16.776 21.564 16.848 ;
     RECT  21.491 16.848 21.516 16.872 ;
     RECT  21.491 16.872 21.564 16.944 ;
     RECT  21.491 16.944 21.516 16.968 ;
     RECT  21.491 16.968 21.564 17.04 ;
     RECT  21.491 17.04 21.516 17.064 ;
     RECT  21.491 17.064 21.564 17.136 ;
     RECT  21.491 17.136 21.516 17.16 ;
     RECT  21.491 17.16 21.564 17.232 ;
     RECT  21.491 17.232 21.516 17.256 ;
     RECT  21.491 17.256 21.564 17.328 ;
     RECT  21.491 17.328 21.516 17.352 ;
     RECT  21.491 17.352 21.564 17.424 ;
     RECT  21.491 17.424 21.516 17.448 ;
     RECT  21.491 17.448 21.564 17.52 ;
     RECT  21.491 17.52 21.516 17.544 ;
     RECT  21.491 17.544 21.564 17.616 ;
     RECT  21.491 17.616 21.516 17.64 ;
     RECT  21.491 17.64 21.564 17.712 ;
     RECT  21.491 17.712 21.516 17.736 ;
     RECT  21.491 17.736 21.564 17.808 ;
     RECT  21.491 17.808 21.516 17.832 ;
     RECT  21.491 17.832 21.564 17.904 ;
     RECT  21.491 17.904 21.516 17.928 ;
     RECT  21.491 17.928 21.564 18 ;
     RECT  21.491 18 21.516 18.024 ;
     RECT  21.491 18.024 21.564 18.096 ;
     RECT  21.491 18.096 21.516 18.12 ;
     RECT  21.491 18.12 21.564 18.192 ;
     RECT  21.491 18.192 21.516 18.216 ;
     RECT  21.491 18.216 21.564 18.288 ;
     RECT  21.491 18.288 21.516 18.312 ;
     RECT  21.491 18.312 21.564 18.384 ;
     RECT  21.491 18.384 21.516 18.408 ;
     RECT  21.491 18.408 21.564 18.48 ;
     RECT  21.491 18.48 21.516 18.504 ;
     RECT  21.491 18.504 21.564 18.576 ;
     RECT  21.491 18.576 21.516 18.6 ;
     RECT  21.491 18.6 21.564 18.672 ;
     RECT  21.491 18.672 21.516 18.696 ;
     RECT  21.491 18.696 21.564 18.768 ;
     RECT  21.491 18.768 21.516 18.792 ;
     RECT  21.491 18.792 21.564 18.864 ;
     RECT  21.491 18.864 21.516 18.888 ;
     RECT  21.491 18.888 21.564 18.96 ;
     RECT  21.491 18.96 21.516 18.984 ;
     RECT  21.491 18.984 21.564 19.056 ;
     RECT  21.491 19.056 21.516 19.08 ;
     RECT  21.491 19.08 21.564 19.92 ;
     RECT  21.491 19.92 21.516 19.944 ;
     RECT  21.491 19.944 21.564 20.016 ;
     RECT  21.491 20.016 21.516 20.04 ;
     RECT  21.491 20.04 21.564 20.112 ;
     RECT  21.491 20.112 21.516 20.136 ;
     RECT  21.491 20.136 21.564 20.208 ;
     RECT  21.491 20.208 21.516 20.232 ;
     RECT  21.491 20.232 21.564 20.304 ;
     RECT  21.491 20.304 21.516 20.328 ;
     RECT  21.491 20.328 21.564 20.4 ;
     RECT  21.491 20.4 21.516 20.424 ;
     RECT  21.491 20.424 21.564 20.496 ;
     RECT  21.491 20.496 21.516 20.52 ;
     RECT  21.491 20.52 21.564 20.592 ;
     RECT  21.491 20.592 21.516 20.616 ;
     RECT  21.491 20.616 21.564 20.688 ;
     RECT  21.491 20.688 21.516 20.712 ;
     RECT  21.491 20.712 21.564 20.784 ;
     RECT  21.491 20.784 21.516 20.808 ;
     RECT  21.491 20.808 21.564 20.88 ;
     RECT  21.491 20.88 21.516 20.904 ;
     RECT  21.491 20.904 21.564 20.976 ;
     RECT  21.491 20.976 21.516 21 ;
     RECT  21.491 21 21.564 21.072 ;
     RECT  21.491 21.072 21.516 21.096 ;
     RECT  21.491 21.096 21.564 21.168 ;
     RECT  21.491 21.168 21.516 21.192 ;
     RECT  21.491 21.192 21.564 21.264 ;
     RECT  21.491 21.264 21.516 21.288 ;
     RECT  21.491 21.288 21.564 21.36 ;
     RECT  21.491 21.36 21.516 21.384 ;
     RECT  21.491 21.384 21.564 21.456 ;
     RECT  21.491 21.456 21.516 21.48 ;
     RECT  21.491 21.48 21.564 21.552 ;
     RECT  21.491 21.552 21.516 21.576 ;
     RECT  21.491 21.576 21.564 21.648 ;
     RECT  21.491 21.648 21.516 21.672 ;
     RECT  21.491 21.672 21.564 21.744 ;
     RECT  21.491 21.744 21.516 21.768 ;
     RECT  21.491 21.768 21.564 21.84 ;
     RECT  21.491 21.84 21.516 21.864 ;
     RECT  21.491 21.864 21.564 21.936 ;
     RECT  21.491 21.936 21.516 21.96 ;
     RECT  21.491 21.96 21.564 22.032 ;
     RECT  21.491 22.032 21.516 22.056 ;
     RECT  21.491 22.056 21.564 22.128 ;
     RECT  21.491 22.128 21.516 22.152 ;
     RECT  21.491 22.152 21.564 22.224 ;
     RECT  21.491 22.224 21.516 22.248 ;
     RECT  21.491 22.248 21.564 22.32 ;
     RECT  21.491 22.32 21.516 22.344 ;
     RECT  21.491 22.344 21.564 22.416 ;
     RECT  21.491 22.416 21.516 22.44 ;
     RECT  21.491 22.44 21.564 22.512 ;
     RECT  21.491 22.512 21.516 22.536 ;
     RECT  21.491 22.536 21.564 22.608 ;
     RECT  21.491 22.608 21.516 22.632 ;
     RECT  21.491 22.632 21.564 22.704 ;
     RECT  21.491 22.704 21.516 22.728 ;
     RECT  21.491 22.728 21.564 22.8 ;
     RECT  21.491 22.8 21.516 22.824 ;
     RECT  21.491 22.824 21.564 22.896 ;
     RECT  21.491 22.896 21.516 22.92 ;
     RECT  21.491 22.92 21.564 22.992 ;
     RECT  21.491 22.992 21.516 23.016 ;
     RECT  21.491 23.016 21.564 23.088 ;
     RECT  21.491 23.088 21.516 23.112 ;
     RECT  21.491 23.112 21.564 23.184 ;
     RECT  21.491 23.184 21.516 23.208 ;
     RECT  21.491 23.208 21.564 23.28 ;
     RECT  21.491 23.28 21.516 23.304 ;
     RECT  21.491 23.304 21.564 23.376 ;
     RECT  21.491 23.376 21.516 23.4 ;
     RECT  21.491 23.4 21.564 23.472 ;
     RECT  21.491 23.472 21.516 23.496 ;
     RECT  21.491 23.496 21.564 23.568 ;
     RECT  21.491 23.568 21.516 23.592 ;
     RECT  21.491 23.592 21.564 23.664 ;
     RECT  21.491 23.664 21.516 23.688 ;
     RECT  21.491 23.688 21.564 23.76 ;
     RECT  21.491 23.76 21.516 23.784 ;
     RECT  21.491 23.784 21.564 23.856 ;
     RECT  21.491 23.856 21.516 23.88 ;
     RECT  21.491 23.88 21.564 23.952 ;
     RECT  21.491 23.952 21.516 23.976 ;
     RECT  21.491 23.976 21.564 24.048 ;
     RECT  21.491 24.048 21.516 24.072 ;
     RECT  21.491 24.072 21.564 24.144 ;
     RECT  21.491 24.144 21.516 24.168 ;
     RECT  21.491 24.168 21.564 24.24 ;
     RECT  21.491 24.24 21.516 24.264 ;
     RECT  21.491 24.264 21.564 24.336 ;
     RECT  21.491 24.336 21.516 24.36 ;
     RECT  21.491 24.36 21.564 24.432 ;
     RECT  21.491 24.432 21.516 24.456 ;
     RECT  21.491 24.456 21.564 24.528 ;
     RECT  21.491 24.528 21.516 24.552 ;
     RECT  21.491 24.552 21.564 24.624 ;
     RECT  21.491 24.624 21.516 24.648 ;
     RECT  21.491 24.648 21.564 24.72 ;
     RECT  21.491 24.72 21.516 24.744 ;
     RECT  21.491 24.744 21.564 24.816 ;
     RECT  21.491 24.816 21.516 24.84 ;
     RECT  21.491 24.84 21.564 24.912 ;
     RECT  21.491 24.912 21.516 24.936 ;
     RECT  21.491 24.936 21.564 25.008 ;
     RECT  21.491 25.008 21.516 25.032 ;
     RECT  21.491 25.032 21.564 25.104 ;
     RECT  21.491 25.104 21.516 25.128 ;
     RECT  21.491 25.128 21.564 25.2 ;
     RECT  21.491 25.2 21.516 25.224 ;
     RECT  21.491 25.224 21.564 25.296 ;
     RECT  21.491 25.296 21.516 25.32 ;
     RECT  21.491 25.32 21.564 25.392 ;
     RECT  21.491 25.392 21.516 25.416 ;
     RECT  21.491 25.416 21.564 25.488 ;
     RECT  21.491 25.488 21.516 25.512 ;
     RECT  21.491 25.512 21.564 25.584 ;
     RECT  21.491 25.584 21.516 25.608 ;
     RECT  21.491 25.608 21.564 25.68 ;
     RECT  21.491 25.68 21.516 25.704 ;
     RECT  21.491 25.704 21.564 25.776 ;
     RECT  21.491 25.776 21.516 25.8 ;
     RECT  21.491 25.8 21.564 25.872 ;
     RECT  21.491 25.872 21.516 25.896 ;
     RECT  21.491 25.896 21.564 25.968 ;
     RECT  21.491 25.968 21.516 25.992 ;
     RECT  21.491 25.992 21.564 26.064 ;
     RECT  21.491 26.064 21.516 26.088 ;
     RECT  21.491 26.088 21.564 26.16 ;
     RECT  21.491 26.16 21.516 26.184 ;
     RECT  21.491 26.184 21.564 26.256 ;
     RECT  21.491 26.256 21.516 26.28 ;
     RECT  21.491 26.28 21.564 26.352 ;
     RECT  21.491 26.352 21.516 26.376 ;
     RECT  21.491 26.376 21.564 26.448 ;
     RECT  21.491 26.448 21.516 26.472 ;
     RECT  21.491 26.472 21.564 26.544 ;
     RECT  21.491 26.544 21.516 26.568 ;
     RECT  21.491 26.568 21.564 26.64 ;
     RECT  21.491 26.64 21.516 26.664 ;
     RECT  21.491 26.664 21.564 26.736 ;
     RECT  21.491 26.736 21.516 26.76 ;
     RECT  21.491 26.76 21.564 26.832 ;
     RECT  21.491 26.832 21.516 26.856 ;
     RECT  21.491 26.856 21.564 26.928 ;
     RECT  21.491 26.928 21.516 26.952 ;
     RECT  21.491 26.952 21.564 27.024 ;
     RECT  21.491 27.024 21.516 27.048 ;
     RECT  21.491 27.048 21.564 27.12 ;
     RECT  21.491 27.12 21.516 27.144 ;
     RECT  21.491 27.144 21.564 27.216 ;
     RECT  21.491 27.216 21.516 27.24 ;
     RECT  21.491 27.24 21.564 27.312 ;
     RECT  21.491 27.312 21.516 27.336 ;
     RECT  21.491 27.336 21.564 27.408 ;
     RECT  21.491 27.408 21.516 27.432 ;
     RECT  21.491 27.432 21.564 27.504 ;
     RECT  21.491 27.504 21.516 27.528 ;
     RECT  21.491 27.528 21.564 27.6 ;
     RECT  21.491 27.6 21.516 27.624 ;
     RECT  21.491 27.624 21.564 27.696 ;
     RECT  21.491 27.696 21.516 27.72 ;
     RECT  21.491 27.72 21.564 27.792 ;
     RECT  21.491 27.792 21.516 27.816 ;
     RECT  21.491 27.816 21.564 27.888 ;
     RECT  21.491 27.888 21.516 27.912 ;
     RECT  21.491 27.912 21.564 27.984 ;
     RECT  21.491 27.984 21.516 28.008 ;
     RECT  21.491 28.008 21.564 28.08 ;
     RECT  21.491 28.08 21.516 28.104 ;
     RECT  21.491 28.104 21.564 28.176 ;
     RECT  21.491 28.176 21.516 28.2 ;
     RECT  21.491 28.2 21.564 28.272 ;
     RECT  21.491 28.272 21.516 28.296 ;
     RECT  21.491 28.296 21.564 28.368 ;
     RECT  21.491 28.368 21.516 28.392 ;
     RECT  21.491 28.392 21.564 28.464 ;
     RECT  21.491 28.464 21.516 28.488 ;
     RECT  21.491 28.488 21.564 28.56 ;
     RECT  21.491 28.56 21.516 28.584 ;
     RECT  21.491 28.584 21.564 28.656 ;
     RECT  21.491 28.656 21.516 28.68 ;
     RECT  21.491 28.68 21.564 28.752 ;
     RECT  21.491 28.752 21.516 28.776 ;
     RECT  21.491 28.776 21.564 28.848 ;
     RECT  21.491 28.848 21.516 28.872 ;
     RECT  21.491 28.872 21.564 28.944 ;
     RECT  21.491 28.944 21.516 28.968 ;
     RECT  21.491 28.968 21.564 29.04 ;
     RECT  21.491 29.04 21.516 29.064 ;
     RECT  21.491 29.064 21.564 29.136 ;
     RECT  21.491 29.136 21.516 29.16 ;
     RECT  21.491 29.16 21.564 29.232 ;
     RECT  21.491 29.232 21.516 29.256 ;
     RECT  21.491 29.256 21.564 29.328 ;
     RECT  21.491 29.328 21.516 29.352 ;
     RECT  21.491 29.352 21.564 29.424 ;
     RECT  21.491 29.424 21.516 29.448 ;
     RECT  21.491 29.448 21.564 29.52 ;
     RECT  21.491 29.52 21.516 29.544 ;
     RECT  21.491 29.544 21.564 29.616 ;
     RECT  21.491 29.616 21.516 29.64 ;
     RECT  21.491 29.64 21.564 29.712 ;
     RECT  21.491 29.712 21.516 29.736 ;
     RECT  21.491 29.736 21.564 29.808 ;
     RECT  21.491 29.808 21.516 29.832 ;
     RECT  21.491 29.832 21.564 29.904 ;
     RECT  21.491 29.904 21.516 29.928 ;
     RECT  21.491 29.928 21.564 30 ;
     RECT  21.491 30 21.516 30.024 ;
     RECT  21.491 30.024 21.564 30.096 ;
     RECT  21.491 30.096 21.516 30.12 ;
     RECT  21.491 30.12 21.564 30.192 ;
     RECT  21.491 30.192 21.516 30.216 ;
     RECT  21.491 30.216 21.564 30.288 ;
     RECT  21.491 30.288 21.516 30.312 ;
     RECT  21.491 30.312 21.564 30.384 ;
     RECT  21.491 30.384 21.516 30.408 ;
     RECT  21.491 30.408 21.564 30.48 ;
     RECT  21.491 30.48 21.516 30.504 ;
     RECT  21.491 30.504 21.564 30.576 ;
     RECT  21.491 30.576 21.516 30.6 ;
     RECT  21.491 30.6 21.564 30.672 ;
     RECT  21.491 30.672 21.516 30.696 ;
    LAYER M5 ;
     RECT  12.84 0.016 12.912 0.084 ;
     RECT  12.816 0.084 12.936 0.131 ;
     RECT  11.376 0.997 11.4 1.717 ;
     RECT  12.816 0.131 12.84 1.717 ;
     RECT  18 1.909 18.024 2.053 ;
     RECT  11.376 1.717 12.84 2.101 ;
     RECT  14.112 1.285 14.136 2.101 ;
     RECT  11.376 2.101 14.136 2.137 ;
     RECT  18 2.053 18.168 2.137 ;
     RECT  2.4 2.137 2.52 2.151 ;
     RECT  5.1 2.137 5.22 2.151 ;
     RECT  7.8 2.137 7.92 2.151 ;
     RECT  18 2.137 18.72 2.151 ;
     RECT  5.1 2.151 5.412 2.245 ;
     RECT  6.432 2.053 6.456 2.245 ;
     RECT  2.4 2.151 2.712 2.341 ;
     RECT  7.8 2.151 8.112 2.341 ;
     RECT  9.408 2.245 9.432 2.341 ;
     RECT  0.432 2.485 0.456 2.533 ;
     RECT  10.5 2.137 14.136 2.533 ;
     RECT  0.432 2.533 0.888 2.581 ;
     RECT  2.304 2.341 2.712 2.581 ;
     RECT  15.792 2.005 16.488 2.581 ;
     RECT  10.5 2.533 14.232 2.629 ;
     RECT  7.8 2.341 9.432 2.677 ;
     RECT  10.5 2.629 14.664 2.677 ;
     RECT  2.304 2.581 2.808 2.725 ;
     RECT  0.432 2.581 0.984 2.773 ;
     RECT  7.8 2.677 14.808 2.773 ;
     RECT  15.792 2.581 16.824 2.773 ;
     RECT  7.8 2.773 16.824 3.013 ;
     RECT  18 2.151 18.912 3.013 ;
     RECT  5.1 2.245 6.456 3.109 ;
     RECT  2.304 2.725 3.576 3.205 ;
     RECT  0.192 2.773 0.984 3.349 ;
     RECT  7.44 3.013 18.912 3.493 ;
     RECT  7.44 3.493 19.08 3.683 ;
     RECT  2.304 3.205 3.624 3.733 ;
     RECT  4.992 3.109 6.456 3.733 ;
     RECT  0.144 3.349 0.984 4.307 ;
     RECT  21.408 4.165 21.432 4.451 ;
     RECT  0.144 4.307 0.888 4.691 ;
     RECT  2.304 3.733 6.456 5.509 ;
     RECT  7.44 3.683 18.912 5.509 ;
     RECT  2.304 5.509 18.912 5.701 ;
     RECT  21.408 5.845 21.432 6.131 ;
     RECT  0.144 4.691 0.696 6.227 ;
     RECT  2.304 5.701 19.368 6.323 ;
     RECT  21.408 7.189 21.432 7.379 ;
     RECT  2.4 6.323 19.368 8.051 ;
     RECT  2.4 8.051 18.912 8.821 ;
     RECT  0.144 6.227 0.552 9.061 ;
     RECT  21.36 10.117 21.384 10.259 ;
     RECT  0.144 9.061 0.6 10.451 ;
     RECT  2.304 8.821 18.912 10.453 ;
     RECT  2.304 10.453 19.32 11.509 ;
     RECT  21.408 11.509 21.432 11.699 ;
     RECT  2.16 11.509 19.32 11.941 ;
     RECT  2.064 11.941 19.32 13.763 ;
     RECT  0.144 10.451 0.552 14.867 ;
     RECT  21.408 14.581 21.432 15.683 ;
     RECT  0.144 14.867 0.456 16.261 ;
     RECT  0.144 16.261 0.552 17.077 ;
     RECT  2.064 13.763 18.912 17.077 ;
     RECT  0.144 17.077 18.912 17.219 ;
     RECT  0.144 17.219 0.552 18.181 ;
     RECT  0.144 18.181 0.936 18.421 ;
     RECT  2.064 17.219 18.912 18.421 ;
     RECT  21.408 17.845 21.432 18.803 ;
     RECT  0.144 18.421 18.912 19.909 ;
     RECT  0.144 19.909 19.032 20.677 ;
     RECT  0.144 20.677 19.32 20.867 ;
     RECT  0.144 20.867 19.032 21.683 ;
     RECT  0.144 21.683 18.912 22.739 ;
     RECT  2.064 22.739 18.912 22.741 ;
     RECT  0.144 22.739 0.84 22.931 ;
     RECT  0.144 22.931 0.6 23.123 ;
     RECT  0.144 23.123 0.552 23.411 ;
     RECT  2.064 22.741 19.368 23.699 ;
     RECT  0.144 23.411 0.408 23.891 ;
     RECT  0.192 23.891 0.408 24.179 ;
     RECT  0.192 24.179 0.36 24.853 ;
     RECT  2.064 23.699 19.176 24.901 ;
     RECT  0.144 24.853 0.36 25.235 ;
     RECT  2.064 24.901 19.368 25.283 ;
     RECT  0.192 25.235 0.36 25.765 ;
     RECT  0.192 25.765 0.408 26.149 ;
     RECT  0.192 26.149 0.552 26.485 ;
     RECT  2.064 25.283 19.176 27.013 ;
     RECT  0.144 26.485 0.552 27.491 ;
     RECT  0.144 27.491 0.504 28.019 ;
     RECT  0.144 28.019 0.408 28.595 ;
     RECT  21.408 29.221 21.432 29.507 ;
     RECT  0.144 28.595 0.312 29.557 ;
     RECT  0.144 29.557 0.456 29.989 ;
     RECT  2.064 27.013 19.368 30.083 ;
     RECT  2.304 30.083 19.368 30.275 ;
     RECT  0.144 29.989 0.504 30.371 ;
     RECT  2.304 30.275 18.912 30.467 ;
     RECT  21.456 30.469 21.48 30.803 ;
     RECT  2.4 30.467 18.912 31.379 ;
     RECT  0.192 30.371 0.504 31.429 ;
     RECT  2.4 31.379 9.144 31.571 ;
     RECT  13.2 31.379 14.76 31.571 ;
     RECT  13.2 31.571 14.568 31.715 ;
     RECT  13.2 31.715 13.608 31.763 ;
     RECT  15.9 31.379 18.912 31.763 ;
     RECT  11.856 31.379 12.072 31.811 ;
     RECT  10.272 31.379 10.812 31.859 ;
     RECT  6.96 31.571 9.144 31.907 ;
     RECT  0.144 31.429 0.504 31.909 ;
     RECT  0.144 31.909 0.552 31.955 ;
     RECT  7.056 31.907 9.144 31.955 ;
     RECT  15.9 31.763 17.496 31.955 ;
     RECT  2.4 31.571 5.976 32.003 ;
     RECT  7.8 31.955 8.232 32.003 ;
     RECT  12.048 31.811 12.072 32.051 ;
     RECT  2.4 32.003 5.412 32.147 ;
     RECT  15.9 31.955 16.632 32.243 ;
     RECT  2.4 32.147 3.432 32.291 ;
     RECT  5.1 32.147 5.412 32.409 ;
     RECT  7.8 32.003 8.112 32.409 ;
     RECT  10.5 31.859 10.812 32.409 ;
     RECT  13.2 31.763 13.512 32.409 ;
     RECT  15.9 32.243 16.212 32.409 ;
     RECT  18.6 31.763 18.912 32.409 ;
     RECT  2.4 32.291 3 32.423 ;
     RECT  5.1 32.409 5.22 32.423 ;
     RECT  7.8 32.409 7.92 32.423 ;
     RECT  10.5 32.409 10.62 32.423 ;
     RECT  13.2 32.409 13.32 32.423 ;
     RECT  15.9 32.409 16.02 32.423 ;
     RECT  18.6 32.409 18.72 32.423 ;
     RECT  2.976 32.423 3 32.483 ;
     RECT  0.192 31.955 0.552 32.627 ;
     RECT  0.24 32.627 0.552 33.203 ;
     RECT  0.288 33.203 0.552 33.395 ;
     RECT  0.336 33.395 0.552 33.491 ;
     RECT  0.336 33.491 0.504 33.587 ;
     RECT  0.48 33.587 0.504 33.683 ;
     RECT  12.84 0.18 12.936 1.285 ;
     RECT  11.4 0.997 12.816 1.717 ;
     RECT  12.84 1.285 14.112 2.101 ;
     RECT  16.488 2.005 18 2.581 ;
     RECT  5.22 2.137 6.432 2.151 ;
     RECT  6.456 2.137 7.8 3.013 ;
     RECT  5.412 2.151 6.432 2.245 ;
     RECT  8.112 2.245 9.408 2.341 ;
     RECT  9.432 2.245 10.5 2.677 ;
     RECT  0.888 2.533 2.304 2.581 ;
     RECT  0.984 2.581 2.304 4.307 ;
     RECT  16.824 2.581 18 3.013 ;
     RECT  14.664 2.629 15.792 2.677 ;
     RECT  14.808 2.677 15.792 2.773 ;
     RECT  3.576 2.725 5.1 3.109 ;
     RECT  6.456 3.013 7.44 5.509 ;
     RECT  3.576 3.109 4.992 3.205 ;
     RECT  3.624 3.205 4.992 3.733 ;
     RECT  0.888 4.307 2.304 4.691 ;
     RECT  21.408 4.451 21.42 5.845 ;
     RECT  21.408 6.131 21.42 7.189 ;
     RECT  0.552 10.451 0.6 11.941 ;
     RECT  0.552 11.941 2.064 14.867 ;
     RECT  0.456 14.867 2.064 16.261 ;
     RECT  0.552 16.261 2.064 17.077 ;
     RECT  0.552 17.219 2.064 18.181 ;
     RECT  0.936 18.181 2.064 18.421 ;
     RECT  18.912 21.683 19.032 22.741 ;
     RECT  0.84 22.739 2.064 22.931 ;
     RECT  0.6 22.931 2.064 23.123 ;
     RECT  0.552 23.123 2.064 23.411 ;
     RECT  19.176 23.699 19.368 24.901 ;
     RECT  0.18 23.891 0.192 24.853 ;
     RECT  0.18 25.235 0.192 26.485 ;
     RECT  0.552 26.149 2.064 27.491 ;
     RECT  0.312 28.595 0.408 29.557 ;
     RECT  0.18 30.371 0.192 31.429 ;
     RECT  9.144 31.379 10.272 31.859 ;
     RECT  10.812 31.379 11.856 31.811 ;
     RECT  12.072 31.379 13.2 32.051 ;
     RECT  14.76 31.379 15.9 31.571 ;
     RECT  5.976 31.571 6.96 31.907 ;
     RECT  14.568 31.571 15.9 31.715 ;
     RECT  17.496 31.763 18.6 31.955 ;
     RECT  10.812 31.811 12.048 32.051 ;
     RECT  9.144 31.859 10.5 31.955 ;
     RECT  5.976 31.907 7.056 31.955 ;
  END
END hbfd_rly_304_WE_rfc
END LIBRARY
